##
## LEF for PtnCells ;
## created by Encounter v13.10-p003_1 on Wed Aug 21 15:55:13 2013
##

VERSION 5.6 ;

BUSBITCHARS "[]" ;
DIVIDERCHAR "/" ;

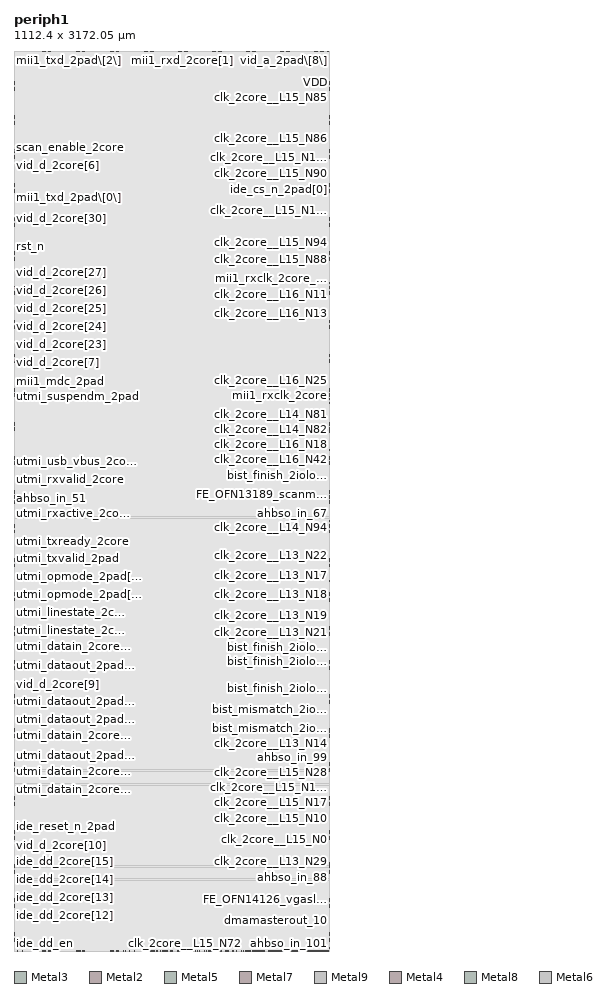
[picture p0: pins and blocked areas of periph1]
MACRO periph1
  CLASS BLOCK ;
  FOREIGN periph1 0 0 ;
  ORIGIN 0.0000 0.0000 ;
  SIZE 1112.4000 BY 3172.0500 ;
  SYMMETRY X Y R90 ;
  PIN n_28347
    DIRECTION OUTPUT ;
    USE SIGNAL ;
    PORT
      LAYER Metal3 ;
        RECT 1112.1100 1866.4300 1112.4000 1866.5000 ;
    END
  END n_28347
  PIN n_28315
    DIRECTION OUTPUT ;
    USE SIGNAL ;
    PORT
      LAYER Metal3 ;
        RECT 1112.1100 1633.8700 1112.4000 1633.9400 ;
    END
  END n_28315
  PIN n_28247
    DIRECTION OUTPUT ;
    USE SIGNAL ;
    PORT
      LAYER Metal3 ;
        RECT 1112.1100 1931.4100 1112.4000 1931.4800 ;
    END
  END n_28247
  PIN n_28215
    DIRECTION OUTPUT ;
    USE SIGNAL ;
    PORT
      LAYER Metal3 ;
        RECT 1112.1100 1936.3500 1112.4000 1936.4200 ;
    END
  END n_28215
  PIN n_27984
    DIRECTION OUTPUT ;
    USE SIGNAL ;
    PORT
      LAYER Metal2 ;
        RECT 1034.8650 0.0000 1034.9350 0.2900 ;
    END
  END n_27984
  PIN n_27896
    DIRECTION OUTPUT ;
    USE SIGNAL ;
    PORT
      LAYER Metal3 ;
        RECT 1112.1100 1681.9400 1112.4000 1682.0100 ;
    END
  END n_27896
  PIN n_27776
    DIRECTION OUTPUT ;
    USE SIGNAL ;
    PORT
      LAYER Metal5 ;
        RECT 1112.1100 1669.7800 1112.4000 1669.8500 ;
    END
  END n_27776
  PIN n_27342
    DIRECTION OUTPUT ;
    USE SIGNAL ;
    PORT
      LAYER Metal7 ;
        RECT 1112.1100 1657.7150 1112.4000 1657.7850 ;
    END
  END n_27342
  PIN n_27252
    DIRECTION OUTPUT ;
    USE SIGNAL ;
    PORT
      LAYER Metal3 ;
        RECT 1112.1100 1649.2600 1112.4000 1649.3300 ;
    END
  END n_27252
  PIN n_27085
    DIRECTION OUTPUT ;
    USE SIGNAL ;
    PORT
      LAYER Metal3 ;
        RECT 1112.1100 845.3700 1112.4000 845.4400 ;
    END
  END n_27085
  PIN n_26776
    DIRECTION OUTPUT ;
    USE SIGNAL ;
    PORT
      LAYER Metal3 ;
        RECT 1112.1100 1197.8200 1112.4000 1197.8900 ;
    END
  END n_26776
  PIN n_20111
    DIRECTION INPUT ;
    USE SIGNAL ;
    PORT
      LAYER Metal5 ;
        RECT 1112.1100 1.0100 1112.4000 1.0800 ;
    END
  END n_20111
  PIN mii2_mdio_en_n
    DIRECTION OUTPUT ;
    USE SIGNAL ;
    PORT
      LAYER Metal9 ;
        RECT 1112.1100 1817.7900 1112.4000 1817.8600 ;
    END
  END mii2_mdio_en_n
  PIN mii2_mdio_2pad
    DIRECTION OUTPUT ;
    USE SIGNAL ;
    PORT
      LAYER Metal9 ;
        RECT 1112.1100 1819.3100 1112.4000 1819.3800 ;
    END
  END mii2_mdio_2pad
  PIN mii2_mdc_2pad
    DIRECTION OUTPUT ;
    USE SIGNAL ;
    PORT
      LAYER Metal9 ;
        RECT 1112.1100 1805.2500 1112.4000 1805.3200 ;
    END
  END mii2_mdc_2pad
  PIN mii2_mdio_2core
    DIRECTION INPUT ;
    USE SIGNAL ;
    PORT
      LAYER Metal9 ;
        RECT 1112.1100 1822.7300 1112.4000 1822.8000 ;
    END
  END mii2_mdio_2core
  PIN mii2_rxerr_2core
    DIRECTION INPUT ;
    USE SIGNAL ;
    PORT
      LAYER Metal4 ;
        RECT 1106.6650 3171.7600 1106.7350 3172.0500 ;
    END
  END mii2_rxerr_2core
  PIN mii2_rxdv_2core
    DIRECTION INPUT ;
    USE SIGNAL ;
    PORT
      LAYER Metal3 ;
        RECT 1112.1100 2779.5700 1112.4000 2779.6400 ;
    END
  END mii2_rxdv_2core
  PIN mii2_rxclk_2core
    DIRECTION INPUT ;
    USE SIGNAL ;
    PORT
      LAYER Metal5 ;
        RECT 1112.1100 1593.2100 1112.4000 1593.2800 ;
    END
  END mii2_rxclk_2core
  PIN mii2_crs_2core
    DIRECTION INPUT ;
    USE SIGNAL ;
    PORT
      LAYER Metal9 ;
        RECT 1112.1100 1874.4100 1112.4000 1874.4800 ;
    END
  END mii2_crs_2core
  PIN mii2_col_2core
    DIRECTION INPUT ;
    USE SIGNAL ;
    PORT
      LAYER Metal9 ;
        RECT 1112.1100 1527.4700 1112.4000 1527.5400 ;
    END
  END mii2_col_2core
  PIN n_28314
    DIRECTION OUTPUT ;
    USE SIGNAL ;
    PORT
      LAYER Metal5 ;
        RECT 1112.1100 1634.0600 1112.4000 1634.1300 ;
    END
  END n_28314
  PIN n_28346
    DIRECTION OUTPUT ;
    USE SIGNAL ;
    PORT
      LAYER Metal5 ;
        RECT 1112.1100 1866.6200 1112.4000 1866.6900 ;
    END
  END n_28346
  PIN mii2_txclk_2core
    DIRECTION INPUT ;
    USE SIGNAL ;
    PORT
      LAYER Metal3 ;
        RECT 1112.1100 1444.2500 1112.4000 1444.3200 ;
    END
  END mii2_txclk_2core
  PIN mii1_mdio_en_n
    DIRECTION OUTPUT ;
    USE SIGNAL ;
    PORT
      LAYER Metal9 ;
        RECT 1112.1100 1786.2500 1112.4000 1786.3200 ;
    END
  END mii1_mdio_en_n
  PIN mii1_mdio_2pad
    DIRECTION OUTPUT ;
    USE SIGNAL ;
    PORT
      LAYER Metal9 ;
        RECT 1112.1100 1772.9500 1112.4000 1773.0200 ;
    END
  END mii1_mdio_2pad
  PIN mii1_mdc_2pad
    DIRECTION OUTPUT ;
    USE SIGNAL ;
    PORT
      LAYER Metal9 ;
        RECT 0.0000 2036.2900 0.2900 2036.3600 ;
    END
  END mii1_mdc_2pad
  PIN mii1_mdio_2core
    DIRECTION INPUT ;
    USE SIGNAL ;
    PORT
      LAYER Metal9 ;
        RECT 1112.1100 1791.9500 1112.4000 1792.0200 ;
    END
  END mii1_mdio_2core
  PIN mii1_rxerr_2core
    DIRECTION INPUT ;
    USE SIGNAL ;
    PORT
      LAYER Metal8 ;
        RECT 977.6650 3171.7600 977.7350 3172.0500 ;
    END
  END mii1_rxerr_2core
  PIN mii1_rxdv_2core
    DIRECTION INPUT ;
    USE SIGNAL ;
    PORT
      LAYER Metal8 ;
        RECT 900.8650 3171.7600 900.9350 3172.0500 ;
    END
  END mii1_rxdv_2core
  PIN mii1_rxclk_2core
    DIRECTION INPUT ;
    USE SIGNAL ;
    PORT
      LAYER Metal3 ;
        RECT 1112.1100 1956.6800 1112.4000 1956.7500 ;
    END
  END mii1_rxclk_2core
  PIN mii1_crs_2core
    DIRECTION INPUT ;
    USE SIGNAL ;
    PORT
      LAYER Metal9 ;
        RECT 1112.1100 1846.2900 1112.4000 1846.3600 ;
    END
  END mii1_crs_2core
  PIN mii1_col_2core
    DIRECTION INPUT ;
    USE SIGNAL ;
    PORT
      LAYER Metal2 ;
        RECT 363.0650 3171.7600 363.1350 3172.0500 ;
    END
  END mii1_col_2core
  PIN n_28214
    DIRECTION OUTPUT ;
    USE SIGNAL ;
    PORT
      LAYER Metal5 ;
        RECT 1112.1100 1936.3500 1112.4000 1936.4200 ;
    END
  END n_28214
  PIN n_28246
    DIRECTION OUTPUT ;
    USE SIGNAL ;
    PORT
      LAYER Metal5 ;
        RECT 1112.1100 1931.6000 1112.4000 1931.6700 ;
    END
  END n_28246
  PIN mii1_txclk_2core
    DIRECTION INPUT ;
    USE SIGNAL ;
    PORT
      LAYER Metal3 ;
        RECT 1112.1100 1553.1200 1112.4000 1553.1900 ;
    END
  END mii1_txclk_2core
  PIN dma_irq
    DIRECTION OUTPUT ;
    USE SIGNAL ;
    PORT
      LAYER Metal3 ;
        RECT 1112.1100 561.1300 1112.4000 561.2000 ;
    END
  END dma_irq
  PIN pio_2pad_1
    DIRECTION INPUT ;
    USE SIGNAL ;
    PORT
      LAYER Metal4 ;
        RECT 1056.8650 0.0000 1056.9350 0.2900 ;
    END
  END pio_2pad_1
  PIN dmaslavein_0
    DIRECTION INPUT ;
    USE SIGNAL ;
    PORT
      LAYER Metal2 ;
        RECT 990.4650 0.0000 990.5350 0.2900 ;
    END
  END dmaslavein_0
  PIN dmaslavein_1
    DIRECTION INPUT ;
    USE SIGNAL ;
    PORT
      LAYER Metal2 ;
        RECT 975.0650 0.0000 975.1350 0.2900 ;
    END
  END dmaslavein_1
  PIN dmaslavein_2
    DIRECTION INPUT ;
    USE SIGNAL ;
    PORT
      LAYER Metal4 ;
        RECT 975.4650 0.0000 975.5350 0.2900 ;
    END
  END dmaslavein_2
  PIN dmaslavein_3
    DIRECTION INPUT ;
    USE SIGNAL ;
    PORT
      LAYER Metal6 ;
        RECT 975.2650 0.0000 975.3350 0.2900 ;
    END
  END dmaslavein_3
  PIN dmaslavein_4
    DIRECTION INPUT ;
    USE SIGNAL ;
    PORT
      LAYER Metal2 ;
        RECT 972.2650 0.0000 972.3350 0.2900 ;
    END
  END dmaslavein_4
  PIN dmaslavein_5
    DIRECTION INPUT ;
    USE SIGNAL ;
    PORT
      LAYER Metal4 ;
        RECT 972.4650 0.0000 972.5350 0.2900 ;
    END
  END dmaslavein_5
  PIN dmaslavein_6
    DIRECTION INPUT ;
    USE SIGNAL ;
    PORT
      LAYER Metal2 ;
        RECT 982.8650 0.0000 982.9350 0.2900 ;
    END
  END dmaslavein_6
  PIN dmaslavein_7
    DIRECTION INPUT ;
    USE SIGNAL ;
    PORT
      LAYER Metal2 ;
        RECT 978.8650 0.0000 978.9350 0.2900 ;
    END
  END dmaslavein_7
  PIN dmaslavein_8
    DIRECTION INPUT ;
    USE SIGNAL ;
    PORT
      LAYER Metal3 ;
        RECT 1112.1100 335.4100 1112.4000 335.4800 ;
    END
  END dmaslavein_8
  PIN dmaslavein_9
    DIRECTION INPUT ;
    USE SIGNAL ;
    PORT
      LAYER Metal2 ;
        RECT 977.4650 0.0000 977.5350 0.2900 ;
    END
  END dmaslavein_9
  PIN dmaslavein_10
    DIRECTION INPUT ;
    USE SIGNAL ;
    PORT
      LAYER Metal3 ;
        RECT 1112.1100 329.3300 1112.4000 329.4000 ;
    END
  END dmaslavein_10
  PIN dmaslavein_11
    DIRECTION INPUT ;
    USE SIGNAL ;
    PORT
      LAYER Metal2 ;
        RECT 975.6650 0.0000 975.7350 0.2900 ;
    END
  END dmaslavein_11
  PIN dmaslavein_12
    DIRECTION INPUT ;
    USE SIGNAL ;
    PORT
      LAYER Metal4 ;
        RECT 973.4650 0.0000 973.5350 0.2900 ;
    END
  END dmaslavein_12
  PIN dmaslavein_13
    DIRECTION INPUT ;
    USE SIGNAL ;
    PORT
      LAYER Metal3 ;
        RECT 1112.1100 316.4100 1112.4000 316.4800 ;
    END
  END dmaslavein_13
  PIN dmaslavein_14
    DIRECTION INPUT ;
    USE SIGNAL ;
    PORT
      LAYER Metal2 ;
        RECT 976.6650 0.0000 976.7350 0.2900 ;
    END
  END dmaslavein_14
  PIN dmaslavein_15
    DIRECTION INPUT ;
    USE SIGNAL ;
    PORT
      LAYER Metal4 ;
        RECT 977.8650 0.0000 977.9350 0.2900 ;
    END
  END dmaslavein_15
  PIN dmaslavein_16
    DIRECTION INPUT ;
    USE SIGNAL ;
    PORT
      LAYER Metal2 ;
        RECT 985.8650 0.0000 985.9350 0.2900 ;
    END
  END dmaslavein_16
  PIN dmaslavein_17
    DIRECTION INPUT ;
    USE SIGNAL ;
    PORT
      LAYER Metal2 ;
        RECT 987.8650 0.0000 987.9350 0.2900 ;
    END
  END dmaslavein_17
  PIN dmaslavein_18
    DIRECTION INPUT ;
    USE SIGNAL ;
    PORT
      LAYER Metal2 ;
        RECT 988.8650 0.0000 988.9350 0.2900 ;
    END
  END dmaslavein_18
  PIN dmaslavein_19
    DIRECTION INPUT ;
    USE SIGNAL ;
    PORT
      LAYER Metal2 ;
        RECT 987.4650 0.0000 987.5350 0.2900 ;
    END
  END dmaslavein_19
  PIN dmaslavein_20
    DIRECTION INPUT ;
    USE SIGNAL ;
    PORT
      LAYER Metal2 ;
        RECT 988.4650 0.0000 988.5350 0.2900 ;
    END
  END dmaslavein_20
  PIN dmaslavein_21
    DIRECTION INPUT ;
    USE SIGNAL ;
    PORT
      LAYER Metal2 ;
        RECT 991.8650 0.0000 991.9350 0.2900 ;
    END
  END dmaslavein_21
  PIN dmaslavein_22
    DIRECTION INPUT ;
    USE SIGNAL ;
    PORT
      LAYER Metal2 ;
        RECT 991.4650 0.0000 991.5350 0.2900 ;
    END
  END dmaslavein_22
  PIN dmaslavein_23
    DIRECTION INPUT ;
    USE SIGNAL ;
    PORT
      LAYER Metal4 ;
        RECT 990.6650 0.0000 990.7350 0.2900 ;
    END
  END dmaslavein_23
  PIN dmaslavein_24
    DIRECTION INPUT ;
    USE SIGNAL ;
    PORT
      LAYER Metal4 ;
        RECT 986.0650 0.0000 986.1350 0.2900 ;
    END
  END dmaslavein_24
  PIN dmaslavein_25
    DIRECTION INPUT ;
    USE SIGNAL ;
    PORT
      LAYER Metal2 ;
        RECT 980.2650 0.0000 980.3350 0.2900 ;
    END
  END dmaslavein_25
  PIN dmaslavein_26
    DIRECTION INPUT ;
    USE SIGNAL ;
    PORT
      LAYER Metal2 ;
        RECT 983.2650 0.0000 983.3350 0.2900 ;
    END
  END dmaslavein_26
  PIN dmaslavein_27
    DIRECTION INPUT ;
    USE SIGNAL ;
    PORT
      LAYER Metal3 ;
        RECT 1112.1100 268.5300 1112.4000 268.6000 ;
    END
  END dmaslavein_27
  PIN dmaslavein_28
    DIRECTION INPUT ;
    USE SIGNAL ;
    PORT
      LAYER Metal2 ;
        RECT 981.6650 0.0000 981.7350 0.2900 ;
    END
  END dmaslavein_28
  PIN dmaslavein_29
    DIRECTION INPUT ;
    USE SIGNAL ;
    PORT
      LAYER Metal4 ;
        RECT 987.6650 0.0000 987.7350 0.2900 ;
    END
  END dmaslavein_29
  PIN dmaslavein_30
    DIRECTION INPUT ;
    USE SIGNAL ;
    PORT
      LAYER Metal4 ;
        RECT 986.6650 0.0000 986.7350 0.2900 ;
    END
  END dmaslavein_30
  PIN dmaslavein_31
    DIRECTION INPUT ;
    USE SIGNAL ;
    PORT
      LAYER Metal2 ;
        RECT 984.8650 0.0000 984.9350 0.2900 ;
    END
  END dmaslavein_31
  PIN dmaslavein_32
    DIRECTION INPUT ;
    USE SIGNAL ;
    PORT
      LAYER Metal2 ;
        RECT 1101.8650 0.0000 1101.9350 0.2900 ;
    END
  END dmaslavein_32
  PIN dmaslavein_33
    DIRECTION INPUT ;
    USE SIGNAL ;
    PORT
      LAYER Metal3 ;
        RECT 1112.1100 10.5100 1112.4000 10.5800 ;
    END
  END dmaslavein_33
  PIN dmaslavein_34
    DIRECTION INPUT ;
    USE SIGNAL ;
    PORT
      LAYER Metal3 ;
        RECT 1112.1100 225.9700 1112.4000 226.0400 ;
    END
  END dmaslavein_34
  PIN dmaslavein_35
    DIRECTION INPUT ;
    USE SIGNAL ;
    PORT
      LAYER Metal2 ;
        RECT 1077.8650 0.0000 1077.9350 0.2900 ;
    END
  END dmaslavein_35
  PIN dmaslavein_36
    DIRECTION INPUT ;
    USE SIGNAL ;
    PORT
      LAYER Metal2 ;
        RECT 1078.4650 0.0000 1078.5350 0.2900 ;
    END
  END dmaslavein_36
  PIN dmaslavein_37
    DIRECTION INPUT ;
    USE SIGNAL ;
    PORT
      LAYER Metal2 ;
        RECT 1095.4650 0.0000 1095.5350 0.2900 ;
    END
  END dmaslavein_37
  PIN dmaslavein_38
    DIRECTION INPUT ;
    USE SIGNAL ;
    PORT
      LAYER Metal2 ;
        RECT 1095.0650 0.0000 1095.1350 0.2900 ;
    END
  END dmaslavein_38
  PIN dmaslavein_39
    DIRECTION INPUT ;
    USE SIGNAL ;
    PORT
      LAYER Metal2 ;
        RECT 1096.0650 0.0000 1096.1350 0.2900 ;
    END
  END dmaslavein_39
  PIN dmaslavein_40
    DIRECTION INPUT ;
    USE SIGNAL ;
    PORT
      LAYER Metal2 ;
        RECT 1089.0650 0.0000 1089.1350 0.2900 ;
    END
  END dmaslavein_40
  PIN dmaslavein_41
    DIRECTION INPUT ;
    USE SIGNAL ;
    PORT
      LAYER Metal4 ;
        RECT 1089.0650 0.0000 1089.1350 0.2900 ;
    END
  END dmaslavein_41
  PIN dmaslavein_42
    DIRECTION INPUT ;
    USE SIGNAL ;
    PORT
      LAYER Metal2 ;
        RECT 1090.2650 0.0000 1090.3350 0.2900 ;
    END
  END dmaslavein_42
  PIN dmaslavein_43
    DIRECTION INPUT ;
    USE SIGNAL ;
    PORT
      LAYER Metal6 ;
        RECT 1098.8650 0.0000 1098.9350 0.2900 ;
    END
  END dmaslavein_43
  PIN dmaslavein_44
    DIRECTION INPUT ;
    USE SIGNAL ;
    PORT
      LAYER Metal3 ;
        RECT 1112.1100 7.2800 1112.4000 7.3500 ;
    END
  END dmaslavein_44
  PIN dmaslavein_45
    DIRECTION INPUT ;
    USE SIGNAL ;
    PORT
      LAYER Metal5 ;
        RECT 1112.1100 7.0900 1112.4000 7.1600 ;
    END
  END dmaslavein_45
  PIN dmaslavein_46
    DIRECTION INPUT ;
    USE SIGNAL ;
    PORT
      LAYER Metal5 ;
        RECT 1112.1100 7.8500 1112.4000 7.9200 ;
    END
  END dmaslavein_46
  PIN dmaslavein_47
    DIRECTION INPUT ;
    USE SIGNAL ;
    PORT
      LAYER Metal2 ;
        RECT 1106.8650 0.0000 1106.9350 0.2900 ;
    END
  END dmaslavein_47
  PIN dmaslavein_48
    DIRECTION INPUT ;
    USE SIGNAL ;
    PORT
      LAYER Metal3 ;
        RECT 1112.1100 9.7500 1112.4000 9.8200 ;
    END
  END dmaslavein_48
  PIN dmaslavein_49
    DIRECTION INPUT ;
    USE SIGNAL ;
    PORT
      LAYER Metal4 ;
        RECT 1102.0650 0.0000 1102.1350 0.2900 ;
    END
  END dmaslavein_49
  PIN dmaslavein_50
    DIRECTION INPUT ;
    USE SIGNAL ;
    PORT
      LAYER Metal5 ;
        RECT 1112.1100 9.3700 1112.4000 9.4400 ;
    END
  END dmaslavein_50
  PIN dmaslavein_51
    DIRECTION INPUT ;
    USE SIGNAL ;
    PORT
      LAYER Metal4 ;
        RECT 1102.6650 0.0000 1102.7350 0.2900 ;
    END
  END dmaslavein_51
  PIN dmaslavein_52
    DIRECTION INPUT ;
    USE SIGNAL ;
    PORT
      LAYER Metal4 ;
        RECT 1106.6650 0.0000 1106.7350 0.2900 ;
    END
  END dmaslavein_52
  PIN dmaslavein_53
    DIRECTION INPUT ;
    USE SIGNAL ;
    PORT
      LAYER Metal2 ;
        RECT 1106.4650 0.0000 1106.5350 0.2900 ;
    END
  END dmaslavein_53
  PIN dmaslavein_54
    DIRECTION INPUT ;
    USE SIGNAL ;
    PORT
      LAYER Metal2 ;
        RECT 1105.4650 0.0000 1105.5350 0.2900 ;
    END
  END dmaslavein_54
  PIN dmaslavein_55
    DIRECTION INPUT ;
    USE SIGNAL ;
    PORT
      LAYER Metal3 ;
        RECT 1112.1100 8.9900 1112.4000 9.0600 ;
    END
  END dmaslavein_55
  PIN dmaslavein_56
    DIRECTION INPUT ;
    USE SIGNAL ;
    PORT
      LAYER Metal4 ;
        RECT 1106.2650 0.0000 1106.3350 0.2900 ;
    END
  END dmaslavein_56
  PIN dmaslavein_57
    DIRECTION INPUT ;
    USE SIGNAL ;
    PORT
      LAYER Metal6 ;
        RECT 1106.8650 0.0000 1106.9350 0.2900 ;
    END
  END dmaslavein_57
  PIN dmaslavein_58
    DIRECTION INPUT ;
    USE SIGNAL ;
    PORT
      LAYER Metal3 ;
        RECT 1112.1100 10.8900 1112.4000 10.9600 ;
    END
  END dmaslavein_58
  PIN dmaslavein_59
    DIRECTION INPUT ;
    USE SIGNAL ;
    PORT
      LAYER Metal4 ;
        RECT 1105.2650 0.0000 1105.3350 0.2900 ;
    END
  END dmaslavein_59
  PIN dmaslavein_60
    DIRECTION INPUT ;
    USE SIGNAL ;
    PORT
      LAYER Metal8 ;
        RECT 1103.6650 0.0000 1103.7350 0.2900 ;
    END
  END dmaslavein_60
  PIN dmaslavein_61
    DIRECTION INPUT ;
    USE SIGNAL ;
    PORT
      LAYER Metal3 ;
        RECT 1112.1100 8.2300 1112.4000 8.3000 ;
    END
  END dmaslavein_61
  PIN dmaslavein_62
    DIRECTION INPUT ;
    USE SIGNAL ;
    PORT
      LAYER Metal5 ;
        RECT 1112.1100 7.4700 1112.4000 7.5400 ;
    END
  END dmaslavein_62
  PIN dmaslavein_63
    DIRECTION INPUT ;
    USE SIGNAL ;
    PORT
      LAYER Metal6 ;
        RECT 1102.8650 0.0000 1102.9350 0.2900 ;
    END
  END dmaslavein_63
  PIN dmaslavein_73
    DIRECTION INPUT ;
    USE SIGNAL ;
    PORT
      LAYER Metal3 ;
        RECT 1112.1100 232.0500 1112.4000 232.1200 ;
    END
  END dmaslavein_73
  PIN dmaslavein_74
    DIRECTION INPUT ;
    USE SIGNAL ;
    PORT
      LAYER Metal2 ;
        RECT 1091.4650 0.0000 1091.5350 0.2900 ;
    END
  END dmaslavein_74
  PIN dmaslavein_75
    DIRECTION INPUT ;
    USE SIGNAL ;
    PORT
      LAYER Metal2 ;
        RECT 1083.4650 0.0000 1083.5350 0.2900 ;
    END
  END dmaslavein_75
  PIN dmaslavein_76
    DIRECTION INPUT ;
    USE SIGNAL ;
    PORT
      LAYER Metal3 ;
        RECT 1112.1100 229.3900 1112.4000 229.4600 ;
    END
  END dmaslavein_76
  PIN dmaslavein_77
    DIRECTION INPUT ;
    USE SIGNAL ;
    PORT
      LAYER Metal2 ;
        RECT 1090.8650 0.0000 1090.9350 0.2900 ;
    END
  END dmaslavein_77
  PIN dmaslavein_78
    DIRECTION INPUT ;
    USE SIGNAL ;
    PORT
      LAYER Metal4 ;
        RECT 1091.6650 0.0000 1091.7350 0.2900 ;
    END
  END dmaslavein_78
  PIN dmaslavein_80
    DIRECTION INPUT ;
    USE SIGNAL ;
    PORT
      LAYER Metal2 ;
        RECT 1081.6650 0.0000 1081.7350 0.2900 ;
    END
  END dmaslavein_80
  PIN dmaslavein_81
    DIRECTION INPUT ;
    USE SIGNAL ;
    PORT
      LAYER Metal2 ;
        RECT 1071.8650 0.0000 1071.9350 0.2900 ;
    END
  END dmaslavein_81
  PIN dmaslavein_82
    DIRECTION INPUT ;
    USE SIGNAL ;
    PORT
      LAYER Metal6 ;
        RECT 1091.4650 0.0000 1091.5350 0.2900 ;
    END
  END dmaslavein_82
  PIN dmaslavein_83
    DIRECTION INPUT ;
    USE SIGNAL ;
    PORT
      LAYER Metal3 ;
        RECT 1112.1100 244.5900 1112.4000 244.6600 ;
    END
  END dmaslavein_83
  PIN dmamasterout_0
    DIRECTION OUTPUT ;
    USE SIGNAL ;
    PORT
      LAYER Metal6 ;
        RECT 1091.8650 0.0000 1091.9350 0.2900 ;
    END
  END dmamasterout_0
  PIN dmamasterout_1
    DIRECTION OUTPUT ;
    USE SIGNAL ;
    PORT
      LAYER Metal4 ;
        RECT 1099.0650 0.0000 1099.1350 0.2900 ;
    END
  END dmamasterout_1
  PIN dmamasterout_2
    DIRECTION OUTPUT ;
    USE SIGNAL ;
    PORT
      LAYER Metal8 ;
        RECT 1098.2650 0.0000 1098.3350 0.2900 ;
    END
  END dmamasterout_2
  PIN dmamasterout_3
    DIRECTION OUTPUT ;
    USE SIGNAL ;
    PORT
      LAYER Metal6 ;
        RECT 1101.6650 0.0000 1101.7350 0.2900 ;
    END
  END dmamasterout_3
  PIN dmamasterout_4
    DIRECTION OUTPUT ;
    USE SIGNAL ;
    PORT
      LAYER Metal6 ;
        RECT 1095.0650 0.0000 1095.1350 0.2900 ;
    END
  END dmamasterout_4
  PIN dmamasterout_5
    DIRECTION OUTPUT ;
    USE SIGNAL ;
    PORT
      LAYER Metal8 ;
        RECT 1101.6650 0.0000 1101.7350 0.2900 ;
    END
  END dmamasterout_5
  PIN dmamasterout_6
    DIRECTION OUTPUT ;
    USE SIGNAL ;
    PORT
      LAYER Metal2 ;
        RECT 1096.8650 0.0000 1096.9350 0.2900 ;
    END
  END dmamasterout_6
  PIN dmamasterout_7
    DIRECTION OUTPUT ;
    USE SIGNAL ;
    PORT
      LAYER Metal8 ;
        RECT 1101.2650 0.0000 1101.3350 0.2900 ;
    END
  END dmamasterout_7
  PIN dmamasterout_8
    DIRECTION OUTPUT ;
    USE SIGNAL ;
    PORT
      LAYER Metal4 ;
        RECT 1095.4650 0.0000 1095.5350 0.2900 ;
    END
  END dmamasterout_8
  PIN dmamasterout_9
    DIRECTION OUTPUT ;
    USE SIGNAL ;
    PORT
      LAYER Metal8 ;
        RECT 1100.8650 0.0000 1100.9350 0.2900 ;
    END
  END dmamasterout_9
  PIN dmamasterout_10
    DIRECTION OUTPUT ;
    USE SIGNAL ;
    PORT
      LAYER Metal3 ;
        RECT 1112.1100 135.1500 1112.4000 135.2200 ;
    END
  END dmamasterout_10
  PIN dmamasterout_11
    DIRECTION OUTPUT ;
    USE SIGNAL ;
    PORT
      LAYER Metal2 ;
        RECT 1099.8650 0.0000 1099.9350 0.2900 ;
    END
  END dmamasterout_11
  PIN dmamasterout_12
    DIRECTION OUTPUT ;
    USE SIGNAL ;
    PORT
      LAYER Metal6 ;
        RECT 1100.6650 0.0000 1100.7350 0.2900 ;
    END
  END dmamasterout_12
  PIN dmamasterout_13
    DIRECTION OUTPUT ;
    USE SIGNAL ;
    PORT
      LAYER Metal8 ;
        RECT 1100.4650 0.0000 1100.5350 0.2900 ;
    END
  END dmamasterout_13
  PIN dmamasterout_14
    DIRECTION OUTPUT ;
    USE SIGNAL ;
    PORT
      LAYER Metal4 ;
        RECT 1096.6650 0.0000 1096.7350 0.2900 ;
    END
  END dmamasterout_14
  PIN dmamasterout_15
    DIRECTION OUTPUT ;
    USE SIGNAL ;
    PORT
      LAYER Metal6 ;
        RECT 1100.2650 0.0000 1100.3350 0.2900 ;
    END
  END dmamasterout_15
  PIN dmamasterout_16
    DIRECTION OUTPUT ;
    USE SIGNAL ;
    PORT
      LAYER Metal8 ;
        RECT 1100.0650 0.0000 1100.1350 0.2900 ;
    END
  END dmamasterout_16
  PIN dmamasterout_17
    DIRECTION OUTPUT ;
    USE SIGNAL ;
    PORT
      LAYER Metal6 ;
        RECT 1099.8650 0.0000 1099.9350 0.2900 ;
    END
  END dmamasterout_17
  PIN dmamasterout_18
    DIRECTION OUTPUT ;
    USE SIGNAL ;
    PORT
      LAYER Metal2 ;
        RECT 1094.0650 0.0000 1094.1350 0.2900 ;
    END
  END dmamasterout_18
  PIN dmamasterout_19
    DIRECTION OUTPUT ;
    USE SIGNAL ;
    PORT
      LAYER Metal4 ;
        RECT 1096.2650 0.0000 1096.3350 0.2900 ;
    END
  END dmamasterout_19
  PIN dmamasterout_20
    DIRECTION OUTPUT ;
    USE SIGNAL ;
    PORT
      LAYER Metal8 ;
        RECT 1099.6650 0.0000 1099.7350 0.2900 ;
    END
  END dmamasterout_20
  PIN dmamasterout_21
    DIRECTION OUTPUT ;
    USE SIGNAL ;
    PORT
      LAYER Metal6 ;
        RECT 1099.4650 0.0000 1099.5350 0.2900 ;
    END
  END dmamasterout_21
  PIN dmamasterout_22
    DIRECTION OUTPUT ;
    USE SIGNAL ;
    PORT
      LAYER Metal4 ;
        RECT 1090.4650 0.0000 1090.5350 0.2900 ;
    END
  END dmamasterout_22
  PIN dmamasterout_23
    DIRECTION OUTPUT ;
    USE SIGNAL ;
    PORT
      LAYER Metal8 ;
        RECT 1099.2650 0.0000 1099.3350 0.2900 ;
    END
  END dmamasterout_23
  PIN dmamasterout_24
    DIRECTION OUTPUT ;
    USE SIGNAL ;
    PORT
      LAYER Metal4 ;
        RECT 1097.0650 0.0000 1097.1350 0.2900 ;
    END
  END dmamasterout_24
  PIN dmamasterout_25
    DIRECTION OUTPUT ;
    USE SIGNAL ;
    PORT
      LAYER Metal3 ;
        RECT 1112.1100 137.0500 1112.4000 137.1200 ;
    END
  END dmamasterout_25
  PIN dmamasterout_26
    DIRECTION OUTPUT ;
    USE SIGNAL ;
    PORT
      LAYER Metal6 ;
        RECT 1108.4650 0.0000 1108.5350 0.2900 ;
    END
  END dmamasterout_26
  PIN dmamasterout_27
    DIRECTION OUTPUT ;
    USE SIGNAL ;
    PORT
      LAYER Metal6 ;
        RECT 1097.8650 0.0000 1097.9350 0.2900 ;
    END
  END dmamasterout_27
  PIN dmamasterout_28
    DIRECTION OUTPUT ;
    USE SIGNAL ;
    PORT
      LAYER Metal3 ;
        RECT 1112.1100 131.7300 1112.4000 131.8000 ;
    END
  END dmamasterout_28
  PIN dmamasterout_29
    DIRECTION OUTPUT ;
    USE SIGNAL ;
    PORT
      LAYER Metal8 ;
        RECT 1108.4650 0.0000 1108.5350 0.2900 ;
    END
  END dmamasterout_29
  PIN dmamasterout_30
    DIRECTION OUTPUT ;
    USE SIGNAL ;
    PORT
      LAYER Metal3 ;
        RECT 1112.1100 130.2100 1112.4000 130.2800 ;
    END
  END dmamasterout_30
  PIN dmamasterout_31
    DIRECTION OUTPUT ;
    USE SIGNAL ;
    PORT
      LAYER Metal8 ;
        RECT 1097.8650 0.0000 1097.9350 0.2900 ;
    END
  END dmamasterout_31
  PIN dmamasterout_32
    DIRECTION OUTPUT ;
    USE SIGNAL ;
    PORT
      LAYER Metal4 ;
        RECT 1094.2650 0.0000 1094.3350 0.2900 ;
    END
  END dmamasterout_32
  PIN dmamasterout_33
    DIRECTION OUTPUT ;
    USE SIGNAL ;
    PORT
      LAYER Metal4 ;
        RECT 1097.4650 0.0000 1097.5350 0.2900 ;
    END
  END dmamasterout_33
  PIN dmamasterout_34
    DIRECTION OUTPUT ;
    USE SIGNAL ;
    PORT
      LAYER Metal6 ;
        RECT 1097.4650 0.0000 1097.5350 0.2900 ;
    END
  END dmamasterout_34
  PIN dmamasterout_35
    DIRECTION OUTPUT ;
    USE SIGNAL ;
    PORT
      LAYER Metal6 ;
        RECT 1094.4650 0.0000 1094.5350 0.2900 ;
    END
  END dmamasterout_35
  PIN dmamasterout_36
    DIRECTION OUTPUT ;
    USE SIGNAL ;
    PORT
      LAYER Metal8 ;
        RECT 1097.2650 0.0000 1097.3350 0.2900 ;
    END
  END dmamasterout_36
  PIN dmamasterout_37
    DIRECTION OUTPUT ;
    USE SIGNAL ;
    PORT
      LAYER Metal6 ;
        RECT 1096.0650 0.0000 1096.1350 0.2900 ;
    END
  END dmamasterout_37
  PIN dmamasterout_38
    DIRECTION OUTPUT ;
    USE SIGNAL ;
    PORT
      LAYER Metal4 ;
        RECT 1092.8650 0.0000 1092.9350 0.2900 ;
    END
  END dmamasterout_38
  PIN dmamasterout_39
    DIRECTION OUTPUT ;
    USE SIGNAL ;
    PORT
      LAYER Metal2 ;
        RECT 1108.6650 0.0000 1108.7350 0.2900 ;
    END
  END dmamasterout_39
  PIN dmamasterout_40
    DIRECTION OUTPUT ;
    USE SIGNAL ;
    PORT
      LAYER Metal6 ;
        RECT 1097.0650 0.0000 1097.1350 0.2900 ;
    END
  END dmamasterout_40
  PIN dmamasterout_41
    DIRECTION OUTPUT ;
    USE SIGNAL ;
    PORT
      LAYER Metal8 ;
        RECT 1094.8650 0.0000 1094.9350 0.2900 ;
    END
  END dmamasterout_41
  PIN dmamasterout_42
    DIRECTION OUTPUT ;
    USE SIGNAL ;
    PORT
      LAYER Metal8 ;
        RECT 1094.4650 0.0000 1094.5350 0.2900 ;
    END
  END dmamasterout_42
  PIN dmamasterout_43
    DIRECTION OUTPUT ;
    USE SIGNAL ;
    PORT
      LAYER Metal4 ;
        RECT 1093.6650 0.0000 1093.7350 0.2900 ;
    END
  END dmamasterout_43
  PIN dmamasterout_44
    DIRECTION OUTPUT ;
    USE SIGNAL ;
    PORT
      LAYER Metal4 ;
        RECT 1108.6650 0.0000 1108.7350 0.2900 ;
    END
  END dmamasterout_44
  PIN dmamasterout_45
    DIRECTION OUTPUT ;
    USE SIGNAL ;
    PORT
      LAYER Metal3 ;
        RECT 1112.1100 142.3700 1112.4000 142.4400 ;
    END
  END dmamasterout_45
  PIN dmamasterout_46
    DIRECTION OUTPUT ;
    USE SIGNAL ;
    PORT
      LAYER Metal3 ;
        RECT 1112.1100 141.9900 1112.4000 142.0600 ;
    END
  END dmamasterout_46
  PIN dmamasterout_47
    DIRECTION OUTPUT ;
    USE SIGNAL ;
    PORT
      LAYER Metal3 ;
        RECT 1112.1100 140.4700 1112.4000 140.5400 ;
    END
  END dmamasterout_47
  PIN dmamasterout_48
    DIRECTION OUTPUT ;
    USE SIGNAL ;
    PORT
      LAYER Metal6 ;
        RECT 1093.8650 0.0000 1093.9350 0.2900 ;
    END
  END dmamasterout_48
  PIN dmamasterout_49
    DIRECTION OUTPUT ;
    USE SIGNAL ;
    PORT
      LAYER Metal8 ;
        RECT 1096.8650 0.0000 1096.9350 0.2900 ;
    END
  END dmamasterout_49
  PIN dmamasterout_50
    DIRECTION OUTPUT ;
    USE SIGNAL ;
    PORT
      LAYER Metal3 ;
        RECT 1112.1100 147.3100 1112.4000 147.3800 ;
    END
  END dmamasterout_50
  PIN dmamasterout_51
    DIRECTION OUTPUT ;
    USE SIGNAL ;
    PORT
      LAYER Metal8 ;
        RECT 1095.4650 0.0000 1095.5350 0.2900 ;
    END
  END dmamasterout_51
  PIN dmamasterout_52
    DIRECTION OUTPUT ;
    USE SIGNAL ;
    PORT
      LAYER Metal6 ;
        RECT 1096.6650 0.0000 1096.7350 0.2900 ;
    END
  END dmamasterout_52
  PIN dmamasterout_53
    DIRECTION OUTPUT ;
    USE SIGNAL ;
    PORT
      LAYER Metal8 ;
        RECT 1096.4650 0.0000 1096.5350 0.2900 ;
    END
  END dmamasterout_53
  PIN dmamasterout_54
    DIRECTION OUTPUT ;
    USE SIGNAL ;
    PORT
      LAYER Metal8 ;
        RECT 1094.0650 0.0000 1094.1350 0.2900 ;
    END
  END dmamasterout_54
  PIN dmamasterout_55
    DIRECTION OUTPUT ;
    USE SIGNAL ;
    PORT
      LAYER Metal6 ;
        RECT 1108.8650 0.0000 1108.9350 0.2900 ;
    END
  END dmamasterout_55
  PIN dmamasterout_56
    DIRECTION OUTPUT ;
    USE SIGNAL ;
    PORT
      LAYER Metal3 ;
        RECT 1112.1100 149.2100 1112.4000 149.2800 ;
    END
  END dmamasterout_56
  PIN dmamasterout_57
    DIRECTION OUTPUT ;
    USE SIGNAL ;
    PORT
      LAYER Metal8 ;
        RECT 1093.6650 0.0000 1093.7350 0.2900 ;
    END
  END dmamasterout_57
  PIN dmamasterout_58
    DIRECTION OUTPUT ;
    USE SIGNAL ;
    PORT
      LAYER Metal6 ;
        RECT 1093.4650 0.0000 1093.5350 0.2900 ;
    END
  END dmamasterout_58
  PIN dmamasterout_59
    DIRECTION OUTPUT ;
    USE SIGNAL ;
    PORT
      LAYER Metal8 ;
        RECT 1108.8650 0.0000 1108.9350 0.2900 ;
    END
  END dmamasterout_59
  PIN dmamasterout_60
    DIRECTION OUTPUT ;
    USE SIGNAL ;
    PORT
      LAYER Metal4 ;
        RECT 1093.2650 0.0000 1093.3350 0.2900 ;
    END
  END dmamasterout_60
  PIN dmamasterout_61
    DIRECTION OUTPUT ;
    USE SIGNAL ;
    PORT
      LAYER Metal8 ;
        RECT 1093.2650 0.0000 1093.3350 0.2900 ;
    END
  END dmamasterout_61
  PIN dmamasterout_62
    DIRECTION OUTPUT ;
    USE SIGNAL ;
    PORT
      LAYER Metal3 ;
        RECT 1112.1100 148.8300 1112.4000 148.9000 ;
    END
  END dmamasterout_62
  PIN dmamasterout_63
    DIRECTION OUTPUT ;
    USE SIGNAL ;
    PORT
      LAYER Metal8 ;
        RECT 1091.8650 0.0000 1091.9350 0.2900 ;
    END
  END dmamasterout_63
  PIN dmamasterout_64
    DIRECTION OUTPUT ;
    USE SIGNAL ;
    PORT
      LAYER Metal3 ;
        RECT 1112.1100 224.0700 1112.4000 224.1400 ;
    END
  END dmamasterout_64
  PIN dmamasterout_65
    DIRECTION OUTPUT ;
    USE SIGNAL ;
    PORT
      LAYER Metal3 ;
        RECT 1112.1100 222.9300 1112.4000 223.0000 ;
    END
  END dmamasterout_65
  PIN dmamasterout_66
    DIRECTION OUTPUT ;
    USE SIGNAL ;
    PORT
      LAYER Metal3 ;
        RECT 1112.1100 143.8900 1112.4000 143.9600 ;
    END
  END dmamasterout_66
  PIN dmamasterout_67
    DIRECTION OUTPUT ;
    USE SIGNAL ;
    PORT
      LAYER Metal2 ;
        RECT 1109.0650 0.0000 1109.1350 0.2900 ;
    END
  END dmamasterout_67
  PIN dmamasterout_68
    DIRECTION OUTPUT ;
    USE SIGNAL ;
    PORT
      LAYER Metal4 ;
        RECT 1032.8650 0.0000 1032.9350 0.2900 ;
    END
  END dmamasterout_68
  PIN dmamasterout_71
    DIRECTION OUTPUT ;
    USE SIGNAL ;
    PORT
      LAYER Metal4 ;
        RECT 1057.8650 0.0000 1057.9350 0.2900 ;
    END
  END dmamasterout_71
  PIN dmamasterout_72
    DIRECTION OUTPUT ;
    USE SIGNAL ;
    PORT
      LAYER Metal6 ;
        RECT 1047.6650 0.0000 1047.7350 0.2900 ;
    END
  END dmamasterout_72
  PIN dmamasterout_73
    DIRECTION OUTPUT ;
    USE SIGNAL ;
    PORT
      LAYER Metal4 ;
        RECT 1048.8650 0.0000 1048.9350 0.2900 ;
    END
  END dmamasterout_73
  PIN dmamasterout_74
    DIRECTION OUTPUT ;
    USE SIGNAL ;
    PORT
      LAYER Metal3 ;
        RECT 1112.1100 150.7300 1112.4000 150.8000 ;
    END
  END dmamasterout_74
  PIN dmamasterout_75
    DIRECTION OUTPUT ;
    USE SIGNAL ;
    PORT
      LAYER Metal8 ;
        RECT 1091.4650 0.0000 1091.5350 0.2900 ;
    END
  END dmamasterout_75
  PIN dmamasterout_76
    DIRECTION OUTPUT ;
    USE SIGNAL ;
    PORT
      LAYER Metal2 ;
        RECT 1093.0650 0.0000 1093.1350 0.2900 ;
    END
  END dmamasterout_76
  PIN dmamasterout_77
    DIRECTION OUTPUT ;
    USE SIGNAL ;
    PORT
      LAYER Metal3 ;
        RECT 1112.1100 340.3500 1112.4000 340.4200 ;
    END
  END dmamasterout_77
  PIN dmamasterout_78
    DIRECTION OUTPUT ;
    USE SIGNAL ;
    PORT
      LAYER Metal6 ;
        RECT 1092.4650 0.0000 1092.5350 0.2900 ;
    END
  END dmamasterout_78
  PIN dmamasterin_0
    DIRECTION INPUT ;
    USE SIGNAL ;
    PORT
      LAYER Metal3 ;
        RECT 1112.1100 1516.8300 1112.4000 1516.9000 ;
    END
  END dmamasterin_0
  PIN dmamasterin_1
    DIRECTION INPUT ;
    USE SIGNAL ;
    PORT
      LAYER Metal2 ;
        RECT 875.2650 0.0000 875.3350 0.2900 ;
    END
  END dmamasterin_1
  PIN dmamasterin_2
    DIRECTION INPUT ;
    USE SIGNAL ;
    PORT
      LAYER Metal2 ;
        RECT 878.8650 0.0000 878.9350 0.2900 ;
    END
  END dmamasterin_2
  PIN dmamasterin_3
    DIRECTION INPUT ;
    USE SIGNAL ;
    PORT
      LAYER Metal2 ;
        RECT 876.6650 0.0000 876.7350 0.2900 ;
    END
  END dmamasterin_3
  PIN dmamasterin_4
    DIRECTION INPUT ;
    USE SIGNAL ;
    PORT
      LAYER Metal4 ;
        RECT 875.4650 0.0000 875.5350 0.2900 ;
    END
  END dmamasterin_4
  PIN dmamasterin_5
    DIRECTION INPUT ;
    USE SIGNAL ;
    PORT
      LAYER Metal2 ;
        RECT 875.6650 0.0000 875.7350 0.2900 ;
    END
  END dmamasterin_5
  PIN dmamasterin_6
    DIRECTION INPUT ;
    USE SIGNAL ;
    PORT
      LAYER Metal2 ;
        RECT 862.8650 0.0000 862.9350 0.2900 ;
    END
  END dmamasterin_6
  PIN dmamasterin_7
    DIRECTION INPUT ;
    USE SIGNAL ;
    PORT
      LAYER Metal4 ;
        RECT 853.6650 0.0000 853.7350 0.2900 ;
    END
  END dmamasterin_7
  PIN dmamasterin_8
    DIRECTION INPUT ;
    USE SIGNAL ;
    PORT
      LAYER Metal5 ;
        RECT 1112.1100 1491.7500 1112.4000 1491.8200 ;
    END
  END dmamasterin_8
  PIN dmamasterin_9
    DIRECTION INPUT ;
    USE SIGNAL ;
    PORT
      LAYER Metal7 ;
        RECT 1112.1100 1492.1300 1112.4000 1492.2000 ;
    END
  END dmamasterin_9
  PIN dmamasterin_10
    DIRECTION INPUT ;
    USE SIGNAL ;
    PORT
      LAYER Metal2 ;
        RECT 851.8650 0.0000 851.9350 0.2900 ;
    END
  END dmamasterin_10
  PIN dmamasterin_11
    DIRECTION INPUT ;
    USE SIGNAL ;
    PORT
      LAYER Metal3 ;
        RECT 1112.1100 1491.7500 1112.4000 1491.8200 ;
    END
  END dmamasterin_11
  PIN dmamasterin_12
    DIRECTION INPUT ;
    USE SIGNAL ;
    PORT
      LAYER Metal3 ;
        RECT 1112.1100 232.8100 1112.4000 232.8800 ;
    END
  END dmamasterin_12
  PIN dmamasterin_13
    DIRECTION INPUT ;
    USE SIGNAL ;
    PORT
      LAYER Metal3 ;
        RECT 1112.1100 1491.3700 1112.4000 1491.4400 ;
    END
  END dmamasterin_13
  PIN dmamasterin_14
    DIRECTION INPUT ;
    USE SIGNAL ;
    PORT
      LAYER Metal5 ;
        RECT 1112.1100 1492.1300 1112.4000 1492.2000 ;
    END
  END dmamasterin_14
  PIN dmamasterin_15
    DIRECTION INPUT ;
    USE SIGNAL ;
    PORT
      LAYER Metal2 ;
        RECT 851.4650 0.0000 851.5350 0.2900 ;
    END
  END dmamasterin_15
  PIN dmamasterin_16
    DIRECTION INPUT ;
    USE SIGNAL ;
    PORT
      LAYER Metal4 ;
        RECT 851.6650 0.0000 851.7350 0.2900 ;
    END
  END dmamasterin_16
  PIN dmamasterin_17
    DIRECTION INPUT ;
    USE SIGNAL ;
    PORT
      LAYER Metal3 ;
        RECT 1112.1100 1485.2900 1112.4000 1485.3600 ;
    END
  END dmamasterin_17
  PIN dmamasterin_18
    DIRECTION INPUT ;
    USE SIGNAL ;
    PORT
      LAYER Metal3 ;
        RECT 1112.1100 1471.9900 1112.4000 1472.0600 ;
    END
  END dmamasterin_18
  PIN dmamasterin_19
    DIRECTION INPUT ;
    USE SIGNAL ;
    PORT
      LAYER Metal3 ;
        RECT 1112.1100 1471.6100 1112.4000 1471.6800 ;
    END
  END dmamasterin_19
  PIN dmamasterin_20
    DIRECTION INPUT ;
    USE SIGNAL ;
    PORT
      LAYER Metal3 ;
        RECT 1112.1100 1471.2300 1112.4000 1471.3000 ;
    END
  END dmamasterin_20
  PIN dmamasterin_21
    DIRECTION INPUT ;
    USE SIGNAL ;
    PORT
      LAYER Metal3 ;
        RECT 1112.1100 1470.8500 1112.4000 1470.9200 ;
    END
  END dmamasterin_21
  PIN dmamasterin_22
    DIRECTION INPUT ;
    USE SIGNAL ;
    PORT
      LAYER Metal6 ;
        RECT 851.4650 0.0000 851.5350 0.2900 ;
    END
  END dmamasterin_22
  PIN dmamasterin_23
    DIRECTION INPUT ;
    USE SIGNAL ;
    PORT
      LAYER Metal3 ;
        RECT 1112.1100 233.9500 1112.4000 234.0200 ;
    END
  END dmamasterin_23
  PIN dmamasterin_24
    DIRECTION INPUT ;
    USE SIGNAL ;
    PORT
      LAYER Metal4 ;
        RECT 856.6650 0.0000 856.7350 0.2900 ;
    END
  END dmamasterin_24
  PIN dmamasterin_25
    DIRECTION INPUT ;
    USE SIGNAL ;
    PORT
      LAYER Metal4 ;
        RECT 860.6650 0.0000 860.7350 0.2900 ;
    END
  END dmamasterin_25
  PIN dmamasterin_26
    DIRECTION INPUT ;
    USE SIGNAL ;
    PORT
      LAYER Metal4 ;
        RECT 863.4650 0.0000 863.5350 0.2900 ;
    END
  END dmamasterin_26
  PIN dmamasterin_27
    DIRECTION INPUT ;
    USE SIGNAL ;
    PORT
      LAYER Metal2 ;
        RECT 867.8650 0.0000 867.9350 0.2900 ;
    END
  END dmamasterin_27
  PIN dmamasterin_28
    DIRECTION INPUT ;
    USE SIGNAL ;
    PORT
      LAYER Metal5 ;
        RECT 1112.1100 1491.3700 1112.4000 1491.4400 ;
    END
  END dmamasterin_28
  PIN dmamasterin_29
    DIRECTION INPUT ;
    USE SIGNAL ;
    PORT
      LAYER Metal2 ;
        RECT 874.8650 0.0000 874.9350 0.2900 ;
    END
  END dmamasterin_29
  PIN dmamasterin_30
    DIRECTION INPUT ;
    USE SIGNAL ;
    PORT
      LAYER Metal4 ;
        RECT 876.8650 0.0000 876.9350 0.2900 ;
    END
  END dmamasterin_30
  PIN dmamasterin_31
    DIRECTION INPUT ;
    USE SIGNAL ;
    PORT
      LAYER Metal2 ;
        RECT 986.4650 0.0000 986.5350 0.2900 ;
    END
  END dmamasterin_31
  PIN dmamasterin_32
    DIRECTION INPUT ;
    USE SIGNAL ;
    PORT
      LAYER Metal2 ;
        RECT 1099.4650 0.0000 1099.5350 0.2900 ;
    END
  END dmamasterin_32
  PIN dmamasterin_33
    DIRECTION INPUT ;
    USE SIGNAL ;
    PORT
      LAYER Metal4 ;
        RECT 1099.6650 0.0000 1099.7350 0.2900 ;
    END
  END dmamasterin_33
  PIN dmamasterin_35
    DIRECTION INPUT ;
    USE SIGNAL ;
    PORT
      LAYER Metal2 ;
        RECT 1036.6650 0.0000 1036.7350 0.2900 ;
    END
  END dmamasterin_35
  PIN dmamasterin_36
    DIRECTION INPUT ;
    USE SIGNAL ;
    PORT
      LAYER Metal2 ;
        RECT 1055.8650 0.0000 1055.9350 0.2900 ;
    END
  END dmamasterin_36
  PIN n_20008
    DIRECTION INPUT ;
    USE SIGNAL ;
    PORT
      LAYER Metal5 ;
        RECT 1112.1100 1.3900 1112.4000 1.4600 ;
    END
  END n_20008
  PIN n_28353
    DIRECTION OUTPUT ;
    USE SIGNAL ;
    PORT
      LAYER Metal3 ;
        RECT 1112.1100 857.7200 1112.4000 857.7900 ;
    END
  END n_28353
  PIN n_26795
    DIRECTION OUTPUT ;
    USE SIGNAL ;
    PORT
      LAYER Metal3 ;
        RECT 1112.1100 511.3500 1112.4000 511.4200 ;
    END
  END n_26795
  PIN n_26787
    DIRECTION INPUT ;
    USE SIGNAL ;
    PORT
      LAYER Metal4 ;
        RECT 1054.8650 0.0000 1054.9350 0.2900 ;
    END
  END n_26787
  PIN utmi_usb_vbus_2core
    DIRECTION INPUT ;
    USE SIGNAL ;
    PORT
      LAYER Metal9 ;
        RECT 0.0000 1696.5700 0.2900 1696.6400 ;
    END
  END utmi_usb_vbus_2core
  PIN utmi_suspendm_2pad
    DIRECTION OUTPUT ;
    USE SIGNAL ;
    PORT
      LAYER Metal9 ;
        RECT 0.0000 1952.6900 0.2900 1952.7600 ;
    END
  END utmi_suspendm_2pad
  PIN n_28391
    DIRECTION OUTPUT ;
    USE SIGNAL ;
    PORT
      LAYER Metal3 ;
        RECT 1112.1100 900.0900 1112.4000 900.1600 ;
    END
  END n_28391
  PIN n_28352
    DIRECTION OUTPUT ;
    USE SIGNAL ;
    PORT
      LAYER Metal5 ;
        RECT 1112.1100 857.7200 1112.4000 857.7900 ;
    END
  END n_28352
  PIN utmi_rxactive_2core
    DIRECTION INPUT ;
    USE SIGNAL ;
    PORT
      LAYER Metal9 ;
        RECT 0.0000 1570.4100 0.2900 1570.4800 ;
    END
  END utmi_rxactive_2core
  PIN utmi_rxvalid_2core
    DIRECTION INPUT ;
    USE SIGNAL ;
    PORT
      LAYER Metal9 ;
        RECT 0.0000 1633.4900 0.2900 1633.5600 ;
    END
  END utmi_rxvalid_2core
  PIN utmi_txready_2core
    DIRECTION INPUT ;
    USE SIGNAL ;
    PORT
      LAYER Metal9 ;
        RECT 0.0000 1443.8700 0.2900 1443.9400 ;
    END
  END utmi_txready_2core
  PIN utmi_txvalid_2pad
    DIRECTION OUTPUT ;
    USE SIGNAL ;
    PORT
      LAYER Metal9 ;
        RECT 0.0000 1384.2100 0.2900 1384.2800 ;
    END
  END utmi_txvalid_2pad
  PIN utmi_phy_rst_2pad
    DIRECTION OUTPUT ;
    USE SIGNAL ;
    PORT
      LAYER Metal7 ;
        RECT 0.0000 1588.1750 0.2900 1588.2450 ;
    END
  END utmi_phy_rst_2pad
  PIN utmi_phy_clk_2core
    DIRECTION INPUT ;
    USE SIGNAL ;
    PORT
      LAYER Metal8 ;
        RECT 423.6650 0.0000 423.7350 0.2900 ;
    END
  END utmi_phy_clk_2core
  PIN usbslaveout_0
    DIRECTION OUTPUT ;
    USE SIGNAL ;
    PORT
      LAYER Metal7 ;
        RECT 1112.1100 10.4150 1112.4000 10.4850 ;
    END
  END usbslaveout_0
  PIN usbslaveout_1
    DIRECTION OUTPUT ;
    USE SIGNAL ;
    PORT
      LAYER Metal3 ;
        RECT 1112.1100 8.6100 1112.4000 8.6800 ;
    END
  END usbslaveout_1
  PIN usbslaveout_2
    DIRECTION OUTPUT ;
    USE SIGNAL ;
    PORT
      LAYER Metal2 ;
        RECT 947.2650 0.0000 947.3350 0.2900 ;
    END
  END usbslaveout_2
  PIN usbslaveout_3
    DIRECTION OUTPUT ;
    USE SIGNAL ;
    PORT
      LAYER Metal4 ;
        RECT 947.8650 0.0000 947.9350 0.2900 ;
    END
  END usbslaveout_3
  PIN usbslaveout_4
    DIRECTION OUTPUT ;
    USE SIGNAL ;
    PORT
      LAYER Metal5 ;
        RECT 1112.1100 15.0700 1112.4000 15.1400 ;
    END
  END usbslaveout_4
  PIN usbslaveout_5
    DIRECTION OUTPUT ;
    USE SIGNAL ;
    PORT
      LAYER Metal3 ;
        RECT 1112.1100 15.4500 1112.4000 15.5200 ;
    END
  END usbslaveout_5
  PIN usbslaveout_6
    DIRECTION OUTPUT ;
    USE SIGNAL ;
    PORT
      LAYER Metal2 ;
        RECT 941.0650 0.0000 941.1350 0.2900 ;
    END
  END usbslaveout_6
  PIN usbslaveout_7
    DIRECTION OUTPUT ;
    USE SIGNAL ;
    PORT
      LAYER Metal2 ;
        RECT 936.8650 0.0000 936.9350 0.2900 ;
    END
  END usbslaveout_7
  PIN usbslaveout_8
    DIRECTION OUTPUT ;
    USE SIGNAL ;
    PORT
      LAYER Metal2 ;
        RECT 932.8650 0.0000 932.9350 0.2900 ;
    END
  END usbslaveout_8
  PIN usbslaveout_9
    DIRECTION OUTPUT ;
    USE SIGNAL ;
    PORT
      LAYER Metal2 ;
        RECT 925.8650 0.0000 925.9350 0.2900 ;
    END
  END usbslaveout_9
  PIN usbslaveout_10
    DIRECTION OUTPUT ;
    USE SIGNAL ;
    PORT
      LAYER Metal2 ;
        RECT 924.8650 0.0000 924.9350 0.2900 ;
    END
  END usbslaveout_10
  PIN usbslaveout_11
    DIRECTION OUTPUT ;
    USE SIGNAL ;
    PORT
      LAYER Metal4 ;
        RECT 918.6650 0.0000 918.7350 0.2900 ;
    END
  END usbslaveout_11
  PIN usbslaveout_12
    DIRECTION OUTPUT ;
    USE SIGNAL ;
    PORT
      LAYER Metal2 ;
        RECT 920.8650 0.0000 920.9350 0.2900 ;
    END
  END usbslaveout_12
  PIN usbslaveout_13
    DIRECTION OUTPUT ;
    USE SIGNAL ;
    PORT
      LAYER Metal2 ;
        RECT 929.8650 0.0000 929.9350 0.2900 ;
    END
  END usbslaveout_13
  PIN usbslaveout_14
    DIRECTION OUTPUT ;
    USE SIGNAL ;
    PORT
      LAYER Metal2 ;
        RECT 934.0650 0.0000 934.1350 0.2900 ;
    END
  END usbslaveout_14
  PIN usbslaveout_15
    DIRECTION OUTPUT ;
    USE SIGNAL ;
    PORT
      LAYER Metal2 ;
        RECT 941.8650 0.0000 941.9350 0.2900 ;
    END
  END usbslaveout_15
  PIN usbslaveout_16
    DIRECTION OUTPUT ;
    USE SIGNAL ;
    PORT
      LAYER Metal4 ;
        RECT 940.4650 0.0000 940.5350 0.2900 ;
    END
  END usbslaveout_16
  PIN usbslaveout_17
    DIRECTION OUTPUT ;
    USE SIGNAL ;
    PORT
      LAYER Metal6 ;
        RECT 940.6650 0.0000 940.7350 0.2900 ;
    END
  END usbslaveout_17
  PIN usbslaveout_18
    DIRECTION OUTPUT ;
    USE SIGNAL ;
    PORT
      LAYER Metal4 ;
        RECT 940.8650 0.0000 940.9350 0.2900 ;
    END
  END usbslaveout_18
  PIN usbslaveout_19
    DIRECTION OUTPUT ;
    USE SIGNAL ;
    PORT
      LAYER Metal2 ;
        RECT 940.0650 0.0000 940.1350 0.2900 ;
    END
  END usbslaveout_19
  PIN usbslaveout_20
    DIRECTION OUTPUT ;
    USE SIGNAL ;
    PORT
      LAYER Metal4 ;
        RECT 945.4650 0.0000 945.5350 0.2900 ;
    END
  END usbslaveout_20
  PIN usbslaveout_21
    DIRECTION OUTPUT ;
    USE SIGNAL ;
    PORT
      LAYER Metal4 ;
        RECT 947.4650 0.0000 947.5350 0.2900 ;
    END
  END usbslaveout_21
  PIN usbslaveout_22
    DIRECTION OUTPUT ;
    USE SIGNAL ;
    PORT
      LAYER Metal6 ;
        RECT 940.2650 0.0000 940.3350 0.2900 ;
    END
  END usbslaveout_22
  PIN usbslaveout_23
    DIRECTION OUTPUT ;
    USE SIGNAL ;
    PORT
      LAYER Metal3 ;
        RECT 1112.1100 25.7100 1112.4000 25.7800 ;
    END
  END usbslaveout_23
  PIN usbslaveout_24
    DIRECTION OUTPUT ;
    USE SIGNAL ;
    PORT
      LAYER Metal4 ;
        RECT 933.8650 0.0000 933.9350 0.2900 ;
    END
  END usbslaveout_24
  PIN usbslaveout_25
    DIRECTION OUTPUT ;
    USE SIGNAL ;
    PORT
      LAYER Metal6 ;
        RECT 928.8650 0.0000 928.9350 0.2900 ;
    END
  END usbslaveout_25
  PIN usbslaveout_26
    DIRECTION OUTPUT ;
    USE SIGNAL ;
    PORT
      LAYER Metal2 ;
        RECT 927.8650 0.0000 927.9350 0.2900 ;
    END
  END usbslaveout_26
  PIN usbslaveout_27
    DIRECTION OUTPUT ;
    USE SIGNAL ;
    PORT
      LAYER Metal3 ;
        RECT 1112.1100 26.4700 1112.4000 26.5400 ;
    END
  END usbslaveout_27
  PIN usbslaveout_28
    DIRECTION OUTPUT ;
    USE SIGNAL ;
    PORT
      LAYER Metal3 ;
        RECT 1112.1100 21.1500 1112.4000 21.2200 ;
    END
  END usbslaveout_28
  PIN usbslaveout_29
    DIRECTION OUTPUT ;
    USE SIGNAL ;
    PORT
      LAYER Metal3 ;
        RECT 1112.1100 18.8700 1112.4000 18.9400 ;
    END
  END usbslaveout_29
  PIN usbslaveout_30
    DIRECTION OUTPUT ;
    USE SIGNAL ;
    PORT
      LAYER Metal7 ;
        RECT 1112.1100 15.8300 1112.4000 15.9000 ;
    END
  END usbslaveout_30
  PIN usbslaveout_31
    DIRECTION OUTPUT ;
    USE SIGNAL ;
    PORT
      LAYER Metal3 ;
        RECT 1112.1100 17.3500 1112.4000 17.4200 ;
    END
  END usbslaveout_31
  PIN usbslaveout_32
    DIRECTION OUTPUT ;
    USE SIGNAL ;
    PORT
      LAYER Metal3 ;
        RECT 0.0000 1588.2700 0.2900 1588.3400 ;
    END
  END usbslaveout_32
  PIN usbslaveout_33
    DIRECTION OUTPUT ;
    USE SIGNAL ;
    PORT
      LAYER Metal5 ;
        RECT 0.0000 1588.2700 0.2900 1588.3400 ;
    END
  END usbslaveout_33
  PIN usbslaveout_34
    DIRECTION OUTPUT ;
    USE SIGNAL ;
    PORT
      LAYER Metal9 ;
        RECT 0.0000 1583.7100 0.2900 1583.7800 ;
    END
  END usbslaveout_34
  PIN usbslaveout_35
    DIRECTION OUTPUT ;
    USE SIGNAL ;
    PORT
      LAYER Metal9 ;
        RECT 0.0000 1588.2700 0.2900 1588.3400 ;
    END
  END usbslaveout_35
  PIN usbslaveout_36
    DIRECTION OUTPUT ;
    USE SIGNAL ;
    PORT
      LAYER Metal7 ;
        RECT 0.0000 1583.6150 0.2900 1583.6850 ;
    END
  END usbslaveout_36
  PIN usbslaveout_37
    DIRECTION OUTPUT ;
    USE SIGNAL ;
    PORT
      LAYER Metal7 ;
        RECT 0.0000 1588.7450 0.2900 1588.8150 ;
    END
  END usbslaveout_37
  PIN usbslaveout_38
    DIRECTION OUTPUT ;
    USE SIGNAL ;
    PORT
      LAYER Metal7 ;
        RECT 0.0000 1583.0450 0.2900 1583.1150 ;
    END
  END usbslaveout_38
  PIN usbslaveout_39
    DIRECTION OUTPUT ;
    USE SIGNAL ;
    PORT
      LAYER Metal9 ;
        RECT 0.0000 1582.9500 0.2900 1583.0200 ;
    END
  END usbslaveout_39
  PIN usbslaveout_40
    DIRECTION OUTPUT ;
    USE SIGNAL ;
    PORT
      LAYER Metal9 ;
        RECT 0.0000 1589.0300 0.2900 1589.1000 ;
    END
  END usbslaveout_40
  PIN usbslaveout_41
    DIRECTION OUTPUT ;
    USE SIGNAL ;
    PORT
      LAYER Metal3 ;
        RECT 0.0000 1582.7600 0.2900 1582.8300 ;
    END
  END usbslaveout_41
  PIN usbslaveout_42
    DIRECTION OUTPUT ;
    USE SIGNAL ;
    PORT
      LAYER Metal5 ;
        RECT 0.0000 1582.7600 0.2900 1582.8300 ;
    END
  END usbslaveout_42
  PIN usbslaveout_43
    DIRECTION OUTPUT ;
    USE SIGNAL ;
    PORT
      LAYER Metal7 ;
        RECT 0.0000 1589.3150 0.2900 1589.3850 ;
    END
  END usbslaveout_43
  PIN usbslaveout_44
    DIRECTION OUTPUT ;
    USE SIGNAL ;
    PORT
      LAYER Metal7 ;
        RECT 0.0000 1582.4750 0.2900 1582.5450 ;
    END
  END usbslaveout_44
  PIN usbslaveout_45
    DIRECTION OUTPUT ;
    USE SIGNAL ;
    PORT
      LAYER Metal9 ;
        RECT 0.0000 1582.1900 0.2900 1582.2600 ;
    END
  END usbslaveout_45
  PIN usbslaveout_46
    DIRECTION OUTPUT ;
    USE SIGNAL ;
    PORT
      LAYER Metal9 ;
        RECT 0.0000 1589.7900 0.2900 1589.8600 ;
    END
  END usbslaveout_46
  PIN usbslaveout_47
    DIRECTION OUTPUT ;
    USE SIGNAL ;
    PORT
      LAYER Metal7 ;
        RECT 0.0000 1589.8850 0.2900 1589.9550 ;
    END
  END usbslaveout_47
  PIN usbslaveout_48
    DIRECTION OUTPUT ;
    USE SIGNAL ;
    PORT
      LAYER Metal2 ;
        RECT 1067.2650 0.0000 1067.3350 0.2900 ;
    END
  END usbslaveout_48
  PIN usbslaveout_50
    DIRECTION OUTPUT ;
    USE SIGNAL ;
    PORT
      LAYER Metal4 ;
        RECT 1068.6650 0.0000 1068.7350 0.2900 ;
    END
  END usbslaveout_50
  PIN usbslavein_0
    DIRECTION INPUT ;
    USE SIGNAL ;
    PORT
      LAYER Metal3 ;
        RECT 1112.1100 26.0900 1112.4000 26.1600 ;
    END
  END usbslavein_0
  PIN usbslavein_1
    DIRECTION INPUT ;
    USE SIGNAL ;
    PORT
      LAYER Metal3 ;
        RECT 1112.1100 22.6700 1112.4000 22.7400 ;
    END
  END usbslavein_1
  PIN usbslavein_2
    DIRECTION INPUT ;
    USE SIGNAL ;
    PORT
      LAYER Metal3 ;
        RECT 1112.1100 21.5300 1112.4000 21.6000 ;
    END
  END usbslavein_2
  PIN usbslavein_3
    DIRECTION INPUT ;
    USE SIGNAL ;
    PORT
      LAYER Metal3 ;
        RECT 1112.1100 22.2900 1112.4000 22.3600 ;
    END
  END usbslavein_3
  PIN usbslavein_4
    DIRECTION INPUT ;
    USE SIGNAL ;
    PORT
      LAYER Metal3 ;
        RECT 1112.1100 31.4100 1112.4000 31.4800 ;
    END
  END usbslavein_4
  PIN usbslavein_5
    DIRECTION INPUT ;
    USE SIGNAL ;
    PORT
      LAYER Metal3 ;
        RECT 1112.1100 24.5700 1112.4000 24.6400 ;
    END
  END usbslavein_5
  PIN usbslavein_6
    DIRECTION INPUT ;
    USE SIGNAL ;
    PORT
      LAYER Metal3 ;
        RECT 1112.1100 17.7300 1112.4000 17.8000 ;
    END
  END usbslavein_6
  PIN usbslavein_7
    DIRECTION INPUT ;
    USE SIGNAL ;
    PORT
      LAYER Metal3 ;
        RECT 1112.1100 14.3100 1112.4000 14.3800 ;
    END
  END usbslavein_7
  PIN usbslavein_8
    DIRECTION INPUT ;
    USE SIGNAL ;
    PORT
      LAYER Metal3 ;
        RECT 1112.1100 13.9300 1112.4000 14.0000 ;
    END
  END usbslavein_8
  PIN usbslavein_9
    DIRECTION INPUT ;
    USE SIGNAL ;
    PORT
      LAYER Metal2 ;
        RECT 698.4650 0.0000 698.5350 0.2900 ;
    END
  END usbslavein_9
  PIN usbslavein_10
    DIRECTION INPUT ;
    USE SIGNAL ;
    PORT
      LAYER Metal2 ;
        RECT 695.8650 0.0000 695.9350 0.2900 ;
    END
  END usbslavein_10
  PIN usbslavein_11
    DIRECTION INPUT ;
    USE SIGNAL ;
    PORT
      LAYER Metal2 ;
        RECT 693.8650 0.0000 693.9350 0.2900 ;
    END
  END usbslavein_11
  PIN usbslavein_12
    DIRECTION INPUT ;
    USE SIGNAL ;
    PORT
      LAYER Metal2 ;
        RECT 689.8650 0.0000 689.9350 0.2900 ;
    END
  END usbslavein_12
  PIN usbslavein_13
    DIRECTION INPUT ;
    USE SIGNAL ;
    PORT
      LAYER Metal2 ;
        RECT 685.8650 0.0000 685.9350 0.2900 ;
    END
  END usbslavein_13
  PIN usbslavein_14
    DIRECTION INPUT ;
    USE SIGNAL ;
    PORT
      LAYER Metal3 ;
        RECT 1112.1100 6.3300 1112.4000 6.4000 ;
    END
  END usbslavein_14
  PIN usbslavein_15
    DIRECTION INPUT ;
    USE SIGNAL ;
    PORT
      LAYER Metal3 ;
        RECT 1112.1100 16.2100 1112.4000 16.2800 ;
    END
  END usbslavein_15
  PIN usbslavein_16
    DIRECTION INPUT ;
    USE SIGNAL ;
    PORT
      LAYER Metal3 ;
        RECT 1112.1100 31.7900 1112.4000 31.8600 ;
    END
  END usbslavein_16
  PIN usbslavein_17
    DIRECTION INPUT ;
    USE SIGNAL ;
    PORT
      LAYER Metal3 ;
        RECT 1112.1100 45.0900 1112.4000 45.1600 ;
    END
  END usbslavein_17
  PIN usbslavein_18
    DIRECTION INPUT ;
    USE SIGNAL ;
    PORT
      LAYER Metal3 ;
        RECT 1112.1100 46.6100 1112.4000 46.6800 ;
    END
  END usbslavein_18
  PIN usbslavein_19
    DIRECTION INPUT ;
    USE SIGNAL ;
    PORT
      LAYER Metal3 ;
        RECT 1112.1100 46.2300 1112.4000 46.3000 ;
    END
  END usbslavein_19
  PIN usbslavein_20
    DIRECTION INPUT ;
    USE SIGNAL ;
    PORT
      LAYER Metal3 ;
        RECT 1112.1100 51.9300 1112.4000 52.0000 ;
    END
  END usbslavein_20
  PIN usbslavein_21
    DIRECTION INPUT ;
    USE SIGNAL ;
    PORT
      LAYER Metal3 ;
        RECT 1112.1100 51.5500 1112.4000 51.6200 ;
    END
  END usbslavein_21
  PIN usbslavein_22
    DIRECTION INPUT ;
    USE SIGNAL ;
    PORT
      LAYER Metal2 ;
        RECT 711.6650 0.0000 711.7350 0.2900 ;
    END
  END usbslavein_22
  PIN usbslavein_23
    DIRECTION INPUT ;
    USE SIGNAL ;
    PORT
      LAYER Metal4 ;
        RECT 711.8650 0.0000 711.9350 0.2900 ;
    END
  END usbslavein_23
  PIN usbslavein_24
    DIRECTION INPUT ;
    USE SIGNAL ;
    PORT
      LAYER Metal2 ;
        RECT 698.0650 0.0000 698.1350 0.2900 ;
    END
  END usbslavein_24
  PIN usbslavein_25
    DIRECTION INPUT ;
    USE SIGNAL ;
    PORT
      LAYER Metal6 ;
        RECT 711.6650 0.0000 711.7350 0.2900 ;
    END
  END usbslavein_25
  PIN usbslavein_26
    DIRECTION INPUT ;
    USE SIGNAL ;
    PORT
      LAYER Metal8 ;
        RECT 711.8650 0.0000 711.9350 0.2900 ;
    END
  END usbslavein_26
  PIN usbslavein_27
    DIRECTION INPUT ;
    USE SIGNAL ;
    PORT
      LAYER Metal4 ;
        RECT 711.4650 0.0000 711.5350 0.2900 ;
    END
  END usbslavein_27
  PIN usbslavein_28
    DIRECTION INPUT ;
    USE SIGNAL ;
    PORT
      LAYER Metal3 ;
        RECT 1112.1100 48.1300 1112.4000 48.2000 ;
    END
  END usbslavein_28
  PIN usbslavein_29
    DIRECTION INPUT ;
    USE SIGNAL ;
    PORT
      LAYER Metal4 ;
        RECT 698.2650 0.0000 698.3350 0.2900 ;
    END
  END usbslavein_29
  PIN usbslavein_30
    DIRECTION INPUT ;
    USE SIGNAL ;
    PORT
      LAYER Metal3 ;
        RECT 1112.1100 31.0300 1112.4000 31.1000 ;
    END
  END usbslavein_30
  PIN usbslavein_31
    DIRECTION INPUT ;
    USE SIGNAL ;
    PORT
      LAYER Metal8 ;
        RECT 711.4650 0.0000 711.5350 0.2900 ;
    END
  END usbslavein_31
  PIN usbslavein_34
    DIRECTION INPUT ;
    USE SIGNAL ;
    PORT
      LAYER Metal4 ;
        RECT 1051.8650 0.0000 1051.9350 0.2900 ;
    END
  END usbslavein_34
  PIN usbslavein_35
    DIRECTION INPUT ;
    USE SIGNAL ;
    PORT
      LAYER Metal2 ;
        RECT 1048.8650 0.0000 1048.9350 0.2900 ;
    END
  END usbslavein_35
  PIN usbslavein_36
    DIRECTION INPUT ;
    USE SIGNAL ;
    PORT
      LAYER Metal2 ;
        RECT 1049.2650 0.0000 1049.3350 0.2900 ;
    END
  END usbslavein_36
  PIN usbslavein_37
    DIRECTION INPUT ;
    USE SIGNAL ;
    PORT
      LAYER Metal4 ;
        RECT 1047.6650 0.0000 1047.7350 0.2900 ;
    END
  END usbslavein_37
  PIN usbslavein_38
    DIRECTION INPUT ;
    USE SIGNAL ;
    PORT
      LAYER Metal2 ;
        RECT 1038.4650 0.0000 1038.5350 0.2900 ;
    END
  END usbslavein_38
  PIN usbslavein_39
    DIRECTION INPUT ;
    USE SIGNAL ;
    PORT
      LAYER Metal2 ;
        RECT 1039.8650 0.0000 1039.9350 0.2900 ;
    END
  END usbslavein_39
  PIN usbslavein_40
    DIRECTION INPUT ;
    USE SIGNAL ;
    PORT
      LAYER Metal2 ;
        RECT 1043.0650 0.0000 1043.1350 0.2900 ;
    END
  END usbslavein_40
  PIN usbslavein_41
    DIRECTION INPUT ;
    USE SIGNAL ;
    PORT
      LAYER Metal2 ;
        RECT 1026.2650 0.0000 1026.3350 0.2900 ;
    END
  END usbslavein_41
  PIN usbslavein_42
    DIRECTION INPUT ;
    USE SIGNAL ;
    PORT
      LAYER Metal2 ;
        RECT 1024.4650 0.0000 1024.5350 0.2900 ;
    END
  END usbslavein_42
  PIN usbslavein_43
    DIRECTION INPUT ;
    USE SIGNAL ;
    PORT
      LAYER Metal2 ;
        RECT 1020.2650 0.0000 1020.3350 0.2900 ;
    END
  END usbslavein_43
  PIN usbslavein_48
    DIRECTION INPUT ;
    USE SIGNAL ;
    PORT
      LAYER Metal2 ;
        RECT 1014.6650 0.0000 1014.7350 0.2900 ;
    END
  END usbslavein_48
  PIN usbslavein_76
    DIRECTION INPUT ;
    USE SIGNAL ;
    PORT
      LAYER Metal4 ;
        RECT 1095.8650 0.0000 1095.9350 0.2900 ;
    END
  END usbslavein_76
  PIN usbslavein_77
    DIRECTION INPUT ;
    USE SIGNAL ;
    PORT
      LAYER Metal4 ;
        RECT 1094.8650 0.0000 1094.9350 0.2900 ;
    END
  END usbslavein_77
  PIN usbslavein_78
    DIRECTION INPUT ;
    USE SIGNAL ;
    PORT
      LAYER Metal2 ;
        RECT 1094.4650 0.0000 1094.5350 0.2900 ;
    END
  END usbslavein_78
  PIN usbslavein_79
    DIRECTION INPUT ;
    USE SIGNAL ;
    PORT
      LAYER Metal6 ;
        RECT 1095.6650 0.0000 1095.7350 0.2900 ;
    END
  END usbslavein_79
  PIN usbslavein_80
    DIRECTION INPUT ;
    USE SIGNAL ;
    PORT
      LAYER Metal8 ;
        RECT 1095.8650 0.0000 1095.9350 0.2900 ;
    END
  END usbslavein_80
  PIN usbslavein_81
    DIRECTION INPUT ;
    USE SIGNAL ;
    PORT
      LAYER Metal2 ;
        RECT 1068.8650 0.0000 1068.9350 0.2900 ;
    END
  END usbslavein_81
  PIN usbslavein_82
    DIRECTION INPUT ;
    USE SIGNAL ;
    PORT
      LAYER Metal2 ;
        RECT 1066.2650 0.0000 1066.3350 0.2900 ;
    END
  END usbslavein_82
  PIN usbslavein_83
    DIRECTION INPUT ;
    USE SIGNAL ;
    PORT
      LAYER Metal2 ;
        RECT 1061.6650 0.0000 1061.7350 0.2900 ;
    END
  END usbslavein_83
  PIN n_28141
    DIRECTION OUTPUT ;
    USE SIGNAL ;
    PORT
      LAYER Metal3 ;
        RECT 1112.1100 1703.7900 1112.4000 1703.8600 ;
    END
  END n_28141
  PIN ide_diow_n_2pad
    DIRECTION OUTPUT ;
    USE SIGNAL ;
    PORT
      LAYER Metal2 ;
        RECT 783.0650 0.0000 783.1350 0.2900 ;
    END
  END ide_diow_n_2pad
  PIN ide_dior_n_2pad
    DIRECTION OUTPUT ;
    USE SIGNAL ;
    PORT
      LAYER Metal2 ;
        RECT 748.0650 0.0000 748.1350 0.2900 ;
    END
  END ide_dior_n_2pad
  PIN ide_dmack_n_2pad
    DIRECTION OUTPUT ;
    USE SIGNAL ;
    PORT
      LAYER Metal2 ;
        RECT 756.0650 0.0000 756.1350 0.2900 ;
    END
  END ide_dmack_n_2pad
  PIN ide_dd_en
    DIRECTION OUTPUT ;
    USE SIGNAL ;
    PORT
      LAYER Metal8 ;
        RECT 90.6650 0.0000 90.7350 0.2900 ;
    END
  END ide_dd_en
  PIN ide_reset_n_2pad
    DIRECTION OUTPUT ;
    USE SIGNAL ;
    PORT
      LAYER Metal9 ;
        RECT 0.0000 437.2500 0.2900 437.3200 ;
    END
  END ide_reset_n_2pad
  PIN ataslaveout_0
    DIRECTION OUTPUT ;
    USE SIGNAL ;
    PORT
      LAYER Metal2 ;
        RECT 1008.2650 0.0000 1008.3350 0.2900 ;
    END
  END ataslaveout_0
  PIN ataslaveout_1
    DIRECTION OUTPUT ;
    USE SIGNAL ;
    PORT
      LAYER Metal2 ;
        RECT 993.8650 0.0000 993.9350 0.2900 ;
    END
  END ataslaveout_1
  PIN ataslaveout_2
    DIRECTION OUTPUT ;
    USE SIGNAL ;
    PORT
      LAYER Metal2 ;
        RECT 992.4650 0.0000 992.5350 0.2900 ;
    END
  END ataslaveout_2
  PIN ataslaveout_3
    DIRECTION OUTPUT ;
    USE SIGNAL ;
    PORT
      LAYER Metal5 ;
        RECT 1112.1100 10.7000 1112.4000 10.7700 ;
    END
  END ataslaveout_3
  PIN ataslaveout_4
    DIRECTION OUTPUT ;
    USE SIGNAL ;
    PORT
      LAYER Metal6 ;
        RECT 986.6650 0.0000 986.7350 0.2900 ;
    END
  END ataslaveout_4
  PIN ataslaveout_5
    DIRECTION OUTPUT ;
    USE SIGNAL ;
    PORT
      LAYER Metal4 ;
        RECT 981.6650 0.0000 981.7350 0.2900 ;
    END
  END ataslaveout_5
  PIN ataslaveout_6
    DIRECTION OUTPUT ;
    USE SIGNAL ;
    PORT
      LAYER Metal6 ;
        RECT 974.2650 0.0000 974.3350 0.2900 ;
    END
  END ataslaveout_6
  PIN ataslaveout_7
    DIRECTION OUTPUT ;
    USE SIGNAL ;
    PORT
      LAYER Metal2 ;
        RECT 968.8650 0.0000 968.9350 0.2900 ;
    END
  END ataslaveout_7
  PIN ataslaveout_8
    DIRECTION OUTPUT ;
    USE SIGNAL ;
    PORT
      LAYER Metal2 ;
        RECT 963.0650 0.0000 963.1350 0.2900 ;
    END
  END ataslaveout_8
  PIN ataslaveout_9
    DIRECTION OUTPUT ;
    USE SIGNAL ;
    PORT
      LAYER Metal2 ;
        RECT 957.6650 0.0000 957.7350 0.2900 ;
    END
  END ataslaveout_9
  PIN ataslaveout_10
    DIRECTION OUTPUT ;
    USE SIGNAL ;
    PORT
      LAYER Metal4 ;
        RECT 952.6650 0.0000 952.7350 0.2900 ;
    END
  END ataslaveout_10
  PIN ataslaveout_11
    DIRECTION OUTPUT ;
    USE SIGNAL ;
    PORT
      LAYER Metal4 ;
        RECT 955.8650 0.0000 955.9350 0.2900 ;
    END
  END ataslaveout_11
  PIN ataslaveout_12
    DIRECTION OUTPUT ;
    USE SIGNAL ;
    PORT
      LAYER Metal4 ;
        RECT 957.8650 0.0000 957.9350 0.2900 ;
    END
  END ataslaveout_12
  PIN ataslaveout_13
    DIRECTION OUTPUT ;
    USE SIGNAL ;
    PORT
      LAYER Metal4 ;
        RECT 962.8650 0.0000 962.9350 0.2900 ;
    END
  END ataslaveout_13
  PIN ataslaveout_14
    DIRECTION OUTPUT ;
    USE SIGNAL ;
    PORT
      LAYER Metal2 ;
        RECT 963.8650 0.0000 963.9350 0.2900 ;
    END
  END ataslaveout_14
  PIN ataslaveout_15
    DIRECTION OUTPUT ;
    USE SIGNAL ;
    PORT
      LAYER Metal2 ;
        RECT 968.0650 0.0000 968.1350 0.2900 ;
    END
  END ataslaveout_15
  PIN ataslaveout_16
    DIRECTION OUTPUT ;
    USE SIGNAL ;
    PORT
      LAYER Metal4 ;
        RECT 968.6650 0.0000 968.7350 0.2900 ;
    END
  END ataslaveout_16
  PIN ataslaveout_17
    DIRECTION OUTPUT ;
    USE SIGNAL ;
    PORT
      LAYER Metal2 ;
        RECT 974.6650 0.0000 974.7350 0.2900 ;
    END
  END ataslaveout_17
  PIN ataslaveout_18
    DIRECTION OUTPUT ;
    USE SIGNAL ;
    PORT
      LAYER Metal4 ;
        RECT 982.6650 0.0000 982.7350 0.2900 ;
    END
  END ataslaveout_18
  PIN ataslaveout_19
    DIRECTION OUTPUT ;
    USE SIGNAL ;
    PORT
      LAYER Metal7 ;
        RECT 1112.1100 9.5600 1112.4000 9.6300 ;
    END
  END ataslaveout_19
  PIN ataslaveout_20
    DIRECTION OUTPUT ;
    USE SIGNAL ;
    PORT
      LAYER Metal4 ;
        RECT 981.2650 0.0000 981.3350 0.2900 ;
    END
  END ataslaveout_20
  PIN ataslaveout_21
    DIRECTION OUTPUT ;
    USE SIGNAL ;
    PORT
      LAYER Metal6 ;
        RECT 981.6650 0.0000 981.7350 0.2900 ;
    END
  END ataslaveout_21
  PIN ataslaveout_22
    DIRECTION OUTPUT ;
    USE SIGNAL ;
    PORT
      LAYER Metal2 ;
        RECT 973.6650 0.0000 973.7350 0.2900 ;
    END
  END ataslaveout_22
  PIN ataslaveout_23
    DIRECTION OUTPUT ;
    USE SIGNAL ;
    PORT
      LAYER Metal6 ;
        RECT 973.8650 0.0000 973.9350 0.2900 ;
    END
  END ataslaveout_23
  PIN ataslaveout_24
    DIRECTION OUTPUT ;
    USE SIGNAL ;
    PORT
      LAYER Metal4 ;
        RECT 983.4650 0.0000 983.5350 0.2900 ;
    END
  END ataslaveout_24
  PIN ataslaveout_25
    DIRECTION OUTPUT ;
    USE SIGNAL ;
    PORT
      LAYER Metal6 ;
        RECT 987.8650 0.0000 987.9350 0.2900 ;
    END
  END ataslaveout_25
  PIN ataslaveout_26
    DIRECTION OUTPUT ;
    USE SIGNAL ;
    PORT
      LAYER Metal4 ;
        RECT 992.6650 0.0000 992.7350 0.2900 ;
    END
  END ataslaveout_26
  PIN ataslaveout_27
    DIRECTION OUTPUT ;
    USE SIGNAL ;
    PORT
      LAYER Metal5 ;
        RECT 1112.1100 20.7700 1112.4000 20.8400 ;
    END
  END ataslaveout_27
  PIN ataslaveout_28
    DIRECTION OUTPUT ;
    USE SIGNAL ;
    PORT
      LAYER Metal3 ;
        RECT 1112.1100 20.0100 1112.4000 20.0800 ;
    END
  END ataslaveout_28
  PIN ataslaveout_29
    DIRECTION OUTPUT ;
    USE SIGNAL ;
    PORT
      LAYER Metal2 ;
        RECT 914.0650 0.0000 914.1350 0.2900 ;
    END
  END ataslaveout_29
  PIN ataslaveout_30
    DIRECTION OUTPUT ;
    USE SIGNAL ;
    PORT
      LAYER Metal4 ;
        RECT 912.0650 0.0000 912.1350 0.2900 ;
    END
  END ataslaveout_30
  PIN ataslaveout_31
    DIRECTION OUTPUT ;
    USE SIGNAL ;
    PORT
      LAYER Metal2 ;
        RECT 912.8650 0.0000 912.9350 0.2900 ;
    END
  END ataslaveout_31
  PIN ataslaveout_32
    DIRECTION OUTPUT ;
    USE SIGNAL ;
    PORT
      LAYER Metal7 ;
        RECT 0.0000 1581.9050 0.2900 1581.9750 ;
    END
  END ataslaveout_32
  PIN ataslaveout_33
    DIRECTION OUTPUT ;
    USE SIGNAL ;
    PORT
      LAYER Metal3 ;
        RECT 0.0000 1590.1700 0.2900 1590.2400 ;
    END
  END ataslaveout_33
  PIN ataslaveout_34
    DIRECTION OUTPUT ;
    USE SIGNAL ;
    PORT
      LAYER Metal5 ;
        RECT 0.0000 1590.1700 0.2900 1590.2400 ;
    END
  END ataslaveout_34
  PIN ataslaveout_35
    DIRECTION OUTPUT ;
    USE SIGNAL ;
    PORT
      LAYER Metal7 ;
        RECT 0.0000 1590.4550 0.2900 1590.5250 ;
    END
  END ataslaveout_35
  PIN ataslaveout_36
    DIRECTION OUTPUT ;
    USE SIGNAL ;
    PORT
      LAYER Metal9 ;
        RECT 0.0000 1581.4300 0.2900 1581.5000 ;
    END
  END ataslaveout_36
  PIN ataslaveout_37
    DIRECTION OUTPUT ;
    USE SIGNAL ;
    PORT
      LAYER Metal9 ;
        RECT 0.0000 1590.5500 0.2900 1590.6200 ;
    END
  END ataslaveout_37
  PIN ataslaveout_38
    DIRECTION OUTPUT ;
    USE SIGNAL ;
    PORT
      LAYER Metal7 ;
        RECT 0.0000 1581.3350 0.2900 1581.4050 ;
    END
  END ataslaveout_38
  PIN ataslaveout_39
    DIRECTION OUTPUT ;
    USE SIGNAL ;
    PORT
      LAYER Metal7 ;
        RECT 0.0000 1591.0250 0.2900 1591.0950 ;
    END
  END ataslaveout_39
  PIN ataslaveout_40
    DIRECTION OUTPUT ;
    USE SIGNAL ;
    PORT
      LAYER Metal3 ;
        RECT 0.0000 1580.8600 0.2900 1580.9300 ;
    END
  END ataslaveout_40
  PIN ataslaveout_41
    DIRECTION OUTPUT ;
    USE SIGNAL ;
    PORT
      LAYER Metal5 ;
        RECT 0.0000 1580.8600 0.2900 1580.9300 ;
    END
  END ataslaveout_41
  PIN ataslaveout_42
    DIRECTION OUTPUT ;
    USE SIGNAL ;
    PORT
      LAYER Metal7 ;
        RECT 0.0000 1580.7650 0.2900 1580.8350 ;
    END
  END ataslaveout_42
  PIN ataslaveout_43
    DIRECTION OUTPUT ;
    USE SIGNAL ;
    PORT
      LAYER Metal9 ;
        RECT 0.0000 1580.6700 0.2900 1580.7400 ;
    END
  END ataslaveout_43
  PIN ataslaveout_44
    DIRECTION OUTPUT ;
    USE SIGNAL ;
    PORT
      LAYER Metal9 ;
        RECT 0.0000 1591.3100 0.2900 1591.3800 ;
    END
  END ataslaveout_44
  PIN ataslaveout_45
    DIRECTION OUTPUT ;
    USE SIGNAL ;
    PORT
      LAYER Metal7 ;
        RECT 0.0000 1591.5950 0.2900 1591.6650 ;
    END
  END ataslaveout_45
  PIN ataslaveout_46
    DIRECTION OUTPUT ;
    USE SIGNAL ;
    PORT
      LAYER Metal7 ;
        RECT 0.0000 1580.1950 0.2900 1580.2650 ;
    END
  END ataslaveout_46
  PIN ataslaveout_47
    DIRECTION OUTPUT ;
    USE SIGNAL ;
    PORT
      LAYER Metal3 ;
        RECT 0.0000 1592.0700 0.2900 1592.1400 ;
    END
  END ataslaveout_47
  PIN ataslaveout_48
    DIRECTION OUTPUT ;
    USE SIGNAL ;
    PORT
      LAYER Metal4 ;
        RECT 1039.8650 0.0000 1039.9350 0.2900 ;
    END
  END ataslaveout_48
  PIN ataslaveout_50
    DIRECTION OUTPUT ;
    USE SIGNAL ;
    PORT
      LAYER Metal2 ;
        RECT 1038.8650 0.0000 1038.9350 0.2900 ;
    END
  END ataslaveout_50
  PIN ide_intrq_n_2core
    DIRECTION INPUT ;
    USE SIGNAL ;
    PORT
      LAYER Metal8 ;
        RECT 29.8650 0.0000 29.9350 0.2900 ;
    END
  END ide_intrq_n_2core
  PIN ide_iordy_2core
    DIRECTION INPUT ;
    USE SIGNAL ;
    PORT
      LAYER Metal2 ;
        RECT 774.8650 0.0000 774.9350 0.2900 ;
    END
  END ide_iordy_2core
  PIN ide_dmarq_2core
    DIRECTION INPUT ;
    USE SIGNAL ;
    PORT
      LAYER Metal2 ;
        RECT 774.2650 0.0000 774.3350 0.2900 ;
    END
  END ide_dmarq_2core
  PIN ataslavein_0
    DIRECTION INPUT ;
    USE SIGNAL ;
    PORT
      LAYER Metal2 ;
        RECT 879.6650 0.0000 879.7350 0.2900 ;
    END
  END ataslavein_0
  PIN ataslavein_1
    DIRECTION INPUT ;
    USE SIGNAL ;
    PORT
      LAYER Metal2 ;
        RECT 871.4650 0.0000 871.5350 0.2900 ;
    END
  END ataslavein_1
  PIN ataslavein_2
    DIRECTION INPUT ;
    USE SIGNAL ;
    PORT
      LAYER Metal2 ;
        RECT 864.8650 0.0000 864.9350 0.2900 ;
    END
  END ataslavein_2
  PIN ataslavein_3
    DIRECTION INPUT ;
    USE SIGNAL ;
    PORT
      LAYER Metal2 ;
        RECT 858.6650 0.0000 858.7350 0.2900 ;
    END
  END ataslavein_3
  PIN ataslavein_4
    DIRECTION INPUT ;
    USE SIGNAL ;
    PORT
      LAYER Metal2 ;
        RECT 860.8650 0.0000 860.9350 0.2900 ;
    END
  END ataslavein_4
  PIN ataslavein_5
    DIRECTION INPUT ;
    USE SIGNAL ;
    PORT
      LAYER Metal4 ;
        RECT 858.8650 0.0000 858.9350 0.2900 ;
    END
  END ataslavein_5
  PIN ataslavein_6
    DIRECTION INPUT ;
    USE SIGNAL ;
    PORT
      LAYER Metal3 ;
        RECT 1112.1100 23.8100 1112.4000 23.8800 ;
    END
  END ataslavein_6
  PIN ataslavein_7
    DIRECTION INPUT ;
    USE SIGNAL ;
    PORT
      LAYER Metal2 ;
        RECT 863.6650 0.0000 863.7350 0.2900 ;
    END
  END ataslavein_7
  PIN ataslavein_8
    DIRECTION INPUT ;
    USE SIGNAL ;
    PORT
      LAYER Metal5 ;
        RECT 1112.1100 5.5700 1112.4000 5.6400 ;
    END
  END ataslavein_8
  PIN ataslavein_9
    DIRECTION INPUT ;
    USE SIGNAL ;
    PORT
      LAYER Metal2 ;
        RECT 853.8650 0.0000 853.9350 0.2900 ;
    END
  END ataslavein_9
  PIN ataslavein_10
    DIRECTION INPUT ;
    USE SIGNAL ;
    PORT
      LAYER Metal2 ;
        RECT 856.8650 0.0000 856.9350 0.2900 ;
    END
  END ataslavein_10
  PIN ataslavein_11
    DIRECTION INPUT ;
    USE SIGNAL ;
    PORT
      LAYER Metal2 ;
        RECT 861.6650 0.0000 861.7350 0.2900 ;
    END
  END ataslavein_11
  PIN ataslavein_12
    DIRECTION INPUT ;
    USE SIGNAL ;
    PORT
      LAYER Metal3 ;
        RECT 1112.1100 5.1900 1112.4000 5.2600 ;
    END
  END ataslavein_12
  PIN ataslavein_13
    DIRECTION INPUT ;
    USE SIGNAL ;
    PORT
      LAYER Metal4 ;
        RECT 861.8650 0.0000 861.9350 0.2900 ;
    END
  END ataslavein_13
  PIN ataslavein_14
    DIRECTION INPUT ;
    USE SIGNAL ;
    PORT
      LAYER Metal2 ;
        RECT 880.8650 0.0000 880.9350 0.2900 ;
    END
  END ataslavein_14
  PIN ataslavein_15
    DIRECTION INPUT ;
    USE SIGNAL ;
    PORT
      LAYER Metal2 ;
        RECT 881.8650 0.0000 881.9350 0.2900 ;
    END
  END ataslavein_15
  PIN ataslavein_16
    DIRECTION INPUT ;
    USE SIGNAL ;
    PORT
      LAYER Metal2 ;
        RECT 974.2650 0.0000 974.3350 0.2900 ;
    END
  END ataslavein_16
  PIN ataslavein_17
    DIRECTION INPUT ;
    USE SIGNAL ;
    PORT
      LAYER Metal2 ;
        RECT 901.8650 0.0000 901.9350 0.2900 ;
    END
  END ataslavein_17
  PIN ataslavein_18
    DIRECTION INPUT ;
    USE SIGNAL ;
    PORT
      LAYER Metal2 ;
        RECT 903.8650 0.0000 903.9350 0.2900 ;
    END
  END ataslavein_18
  PIN ataslavein_19
    DIRECTION INPUT ;
    USE SIGNAL ;
    PORT
      LAYER Metal2 ;
        RECT 903.4650 0.0000 903.5350 0.2900 ;
    END
  END ataslavein_19
  PIN ataslavein_20
    DIRECTION INPUT ;
    USE SIGNAL ;
    PORT
      LAYER Metal2 ;
        RECT 904.6650 0.0000 904.7350 0.2900 ;
    END
  END ataslavein_20
  PIN ataslavein_21
    DIRECTION INPUT ;
    USE SIGNAL ;
    PORT
      LAYER Metal3 ;
        RECT 1112.1100 14.6900 1112.4000 14.7600 ;
    END
  END ataslavein_21
  PIN ataslavein_22
    DIRECTION INPUT ;
    USE SIGNAL ;
    PORT
      LAYER Metal2 ;
        RECT 905.6650 0.0000 905.7350 0.2900 ;
    END
  END ataslavein_22
  PIN ataslavein_23
    DIRECTION INPUT ;
    USE SIGNAL ;
    PORT
      LAYER Metal2 ;
        RECT 906.8650 0.0000 906.9350 0.2900 ;
    END
  END ataslavein_23
  PIN ataslavein_24
    DIRECTION INPUT ;
    USE SIGNAL ;
    PORT
      LAYER Metal4 ;
        RECT 904.8650 0.0000 904.9350 0.2900 ;
    END
  END ataslavein_24
  PIN ataslavein_25
    DIRECTION INPUT ;
    USE SIGNAL ;
    PORT
      LAYER Metal3 ;
        RECT 1112.1100 20.7700 1112.4000 20.8400 ;
    END
  END ataslavein_25
  PIN ataslavein_26
    DIRECTION INPUT ;
    USE SIGNAL ;
    PORT
      LAYER Metal3 ;
        RECT 1112.1100 24.1900 1112.4000 24.2600 ;
    END
  END ataslavein_26
  PIN ataslavein_27
    DIRECTION INPUT ;
    USE SIGNAL ;
    PORT
      LAYER Metal2 ;
        RECT 938.4650 0.0000 938.5350 0.2900 ;
    END
  END ataslavein_27
  PIN ataslavein_28
    DIRECTION INPUT ;
    USE SIGNAL ;
    PORT
      LAYER Metal2 ;
        RECT 928.4650 0.0000 928.5350 0.2900 ;
    END
  END ataslavein_28
  PIN ataslavein_29
    DIRECTION INPUT ;
    USE SIGNAL ;
    PORT
      LAYER Metal2 ;
        RECT 913.2650 0.0000 913.3350 0.2900 ;
    END
  END ataslavein_29
  PIN ataslavein_30
    DIRECTION INPUT ;
    USE SIGNAL ;
    PORT
      LAYER Metal2 ;
        RECT 906.4650 0.0000 906.5350 0.2900 ;
    END
  END ataslavein_30
  PIN ataslavein_31
    DIRECTION INPUT ;
    USE SIGNAL ;
    PORT
      LAYER Metal2 ;
        RECT 945.4650 0.0000 945.5350 0.2900 ;
    END
  END ataslavein_31
  PIN ataslavein_34
    DIRECTION INPUT ;
    USE SIGNAL ;
    PORT
      LAYER Metal2 ;
        RECT 1046.0650 0.0000 1046.1350 0.2900 ;
    END
  END ataslavein_34
  PIN ataslavein_35
    DIRECTION INPUT ;
    USE SIGNAL ;
    PORT
      LAYER Metal2 ;
        RECT 1047.6650 0.0000 1047.7350 0.2900 ;
    END
  END ataslavein_35
  PIN ataslavein_36
    DIRECTION INPUT ;
    USE SIGNAL ;
    PORT
      LAYER Metal3 ;
        RECT 1112.1100 7.6600 1112.4000 7.7300 ;
    END
  END ataslavein_36
  PIN ataslavein_37
    DIRECTION INPUT ;
    USE SIGNAL ;
    PORT
      LAYER Metal3 ;
        RECT 1112.1100 9.3700 1112.4000 9.4400 ;
    END
  END ataslavein_37
  PIN ataslavein_38
    DIRECTION INPUT ;
    USE SIGNAL ;
    PORT
      LAYER Metal2 ;
        RECT 1047.0650 0.0000 1047.1350 0.2900 ;
    END
  END ataslavein_38
  PIN ataslavein_76
    DIRECTION INPUT ;
    USE SIGNAL ;
    PORT
      LAYER Metal3 ;
        RECT 1112.1100 5.5700 1112.4000 5.6400 ;
    END
  END ataslavein_76
  PIN ataslavein_77
    DIRECTION INPUT ;
    USE SIGNAL ;
    PORT
      LAYER Metal2 ;
        RECT 1097.8650 0.0000 1097.9350 0.2900 ;
    END
  END ataslavein_77
  PIN ataslavein_78
    DIRECTION INPUT ;
    USE SIGNAL ;
    PORT
      LAYER Metal4 ;
        RECT 1098.0650 0.0000 1098.1350 0.2900 ;
    END
  END ataslavein_78
  PIN ataslavein_79
    DIRECTION INPUT ;
    USE SIGNAL ;
    PORT
      LAYER Metal2 ;
        RECT 1042.2650 0.0000 1042.3350 0.2900 ;
    END
  END ataslavein_79
  PIN ataslavein_80
    DIRECTION INPUT ;
    USE SIGNAL ;
    PORT
      LAYER Metal3 ;
        RECT 1112.1100 5.9500 1112.4000 6.0200 ;
    END
  END ataslavein_80
  PIN ataslavein_81
    DIRECTION INPUT ;
    USE SIGNAL ;
    PORT
      LAYER Metal3 ;
        RECT 1112.1100 11.2700 1112.4000 11.3400 ;
    END
  END ataslavein_81
  PIN ataslavein_82
    DIRECTION INPUT ;
    USE SIGNAL ;
    PORT
      LAYER Metal2 ;
        RECT 1034.0650 0.0000 1034.1350 0.2900 ;
    END
  END ataslavein_82
  PIN ataslavein_83
    DIRECTION INPUT ;
    USE SIGNAL ;
    PORT
      LAYER Metal4 ;
        RECT 1047.2650 0.0000 1047.3350 0.2900 ;
    END
  END ataslavein_83
  PIN uart_rxd_2core
    DIRECTION INPUT ;
    USE SIGNAL ;
    PORT
      LAYER Metal8 ;
        RECT 1107.2650 0.0000 1107.3350 0.2900 ;
    END
  END uart_rxd_2core
  PIN n_28010
    DIRECTION OUTPUT ;
    USE SIGNAL ;
    PORT
      LAYER Metal4 ;
        RECT 1109.0650 0.0000 1109.1350 0.2900 ;
    END
  END n_28010
  PIN n_27992
    DIRECTION OUTPUT ;
    USE SIGNAL ;
    PORT
      LAYER Metal3 ;
        RECT 1112.1100 1695.4300 1112.4000 1695.5000 ;
    END
  END n_27992
  PIN n_27782
    DIRECTION OUTPUT ;
    USE SIGNAL ;
    PORT
      LAYER Metal5 ;
        RECT 1112.1100 1676.6200 1112.4000 1676.6900 ;
    END
  END n_27782
  PIN n_27348
    DIRECTION OUTPUT ;
    USE SIGNAL ;
    PORT
      LAYER Metal3 ;
        RECT 1112.1100 1658.0000 1112.4000 1658.0700 ;
    END
  END n_27348
  PIN n_27258
    DIRECTION OUTPUT ;
    USE SIGNAL ;
    PORT
      LAYER Metal3 ;
        RECT 1112.1100 1652.6800 1112.4000 1652.7500 ;
    END
  END n_27258
  PIN n_27091
    DIRECTION OUTPUT ;
    USE SIGNAL ;
    PORT
      LAYER Metal3 ;
        RECT 1112.1100 1642.4200 1112.4000 1642.4900 ;
    END
  END n_27091
  PIN n_26809
    DIRECTION OUTPUT ;
    USE SIGNAL ;
    PORT
      LAYER Metal3 ;
        RECT 1112.1100 1148.2300 1112.4000 1148.3000 ;
    END
  END n_26809
  PIN n_26803
    DIRECTION OUTPUT ;
    USE SIGNAL ;
    PORT
      LAYER Metal3 ;
        RECT 1112.1100 1288.4500 1112.4000 1288.5200 ;
    END
  END n_26803
  PIN vid_blank_2pad
    DIRECTION OUTPUT ;
    USE SIGNAL ;
    PORT
      LAYER Metal8 ;
        RECT 1104.0650 0.0000 1104.1350 0.2900 ;
    END
  END vid_blank_2pad
  PIN vid_csync_2pad
    DIRECTION OUTPUT ;
    USE SIGNAL ;
    PORT
      LAYER Metal9 ;
        RECT 1112.1100 1613.3500 1112.4000 1613.4200 ;
    END
  END vid_csync_2pad
  PIN vid_vsync_2pad
    DIRECTION OUTPUT ;
    USE SIGNAL ;
    PORT
      LAYER Metal5 ;
        RECT 1112.1100 1613.5400 1112.4000 1613.6100 ;
    END
  END vid_vsync_2pad
  PIN n_28400
    DIRECTION OUTPUT ;
    USE SIGNAL ;
    PORT
      LAYER Metal7 ;
        RECT 1112.1100 1613.5400 1112.4000 1613.6100 ;
    END
  END n_28400
  PIN vid_pclk_2core
    DIRECTION INPUT ;
    USE SIGNAL ;
    PORT
      LAYER Metal3 ;
        RECT 1112.1100 1617.1500 1112.4000 1617.2200 ;
    END
  END vid_pclk_2core
  PIN vid_ack_2core
    DIRECTION INPUT ;
    USE SIGNAL ;
    PORT
      LAYER Metal2 ;
        RECT 1068.4650 0.0000 1068.5350 0.2900 ;
    END
  END vid_ack_2core
  PIN n_26775
    DIRECTION OUTPUT ;
    USE SIGNAL ;
    PORT
      LAYER Metal5 ;
        RECT 1112.1100 1197.6300 1112.4000 1197.7000 ;
    END
  END n_26775
  PIN n_26802
    DIRECTION OUTPUT ;
    USE SIGNAL ;
    PORT
      LAYER Metal5 ;
        RECT 1112.1100 1288.6400 1112.4000 1288.7100 ;
    END
  END n_26802
  PIN n_26796
    DIRECTION OUTPUT ;
    USE SIGNAL ;
    PORT
      LAYER Metal3 ;
        RECT 1112.1100 1818.7400 1112.4000 1818.8100 ;
    END
  END n_26796
  PIN n_28140
    DIRECTION OUTPUT ;
    USE SIGNAL ;
    PORT
      LAYER Metal5 ;
        RECT 1112.1100 1703.7900 1112.4000 1703.8600 ;
    END
  END n_28140
  PIN n_28056
    DIRECTION OUTPUT ;
    USE SIGNAL ;
    PORT
      LAYER Metal3 ;
        RECT 1112.1100 1714.0500 1112.4000 1714.1200 ;
    END
  END n_28056
  PIN n_28049
    DIRECTION OUTPUT ;
    USE SIGNAL ;
    PORT
      LAYER Metal3 ;
        RECT 1112.1100 1705.8800 1112.4000 1705.9500 ;
    END
  END n_28049
  PIN n_28017
    DIRECTION OUTPUT ;
    USE SIGNAL ;
    PORT
      LAYER Metal5 ;
        RECT 1112.1100 1693.5300 1112.4000 1693.6000 ;
    END
  END n_28017
  PIN n_28011
    DIRECTION OUTPUT ;
    USE SIGNAL ;
    PORT
      LAYER Metal3 ;
        RECT 1112.1100 1700.5600 1112.4000 1700.6300 ;
    END
  END n_28011
  PIN n_27991
    DIRECTION OUTPUT ;
    USE SIGNAL ;
    PORT
      LAYER Metal5 ;
        RECT 1112.1100 1695.6200 1112.4000 1695.6900 ;
    END
  END n_27991
  PIN n_27985
    DIRECTION OUTPUT ;
    USE SIGNAL ;
    PORT
      LAYER Metal3 ;
        RECT 1112.1100 1685.3600 1112.4000 1685.4300 ;
    END
  END n_27985
  PIN n_27895
    DIRECTION OUTPUT ;
    USE SIGNAL ;
    PORT
      LAYER Metal5 ;
        RECT 1112.1100 1681.9400 1112.4000 1682.0100 ;
    END
  END n_27895
  PIN n_27822
    DIRECTION OUTPUT ;
    USE SIGNAL ;
    PORT
      LAYER Metal5 ;
        RECT 1112.1100 1683.4600 1112.4000 1683.5300 ;
    END
  END n_27822
  PIN n_27799
    DIRECTION OUTPUT ;
    USE SIGNAL ;
    PORT
      LAYER Metal3 ;
        RECT 1112.1100 1725.2600 1112.4000 1725.3300 ;
    END
  END n_27799
  PIN n_27788
    DIRECTION OUTPUT ;
    USE SIGNAL ;
    PORT
      LAYER Metal5 ;
        RECT 1112.1100 1716.1400 1112.4000 1716.2100 ;
    END
  END n_27788
  PIN n_27781
    DIRECTION OUTPUT ;
    USE SIGNAL ;
    PORT
      LAYER Metal3 ;
        RECT 1112.1100 1676.4300 1112.4000 1676.5000 ;
    END
  END n_27781
  PIN n_27775
    DIRECTION OUTPUT ;
    USE SIGNAL ;
    PORT
      LAYER Metal3 ;
        RECT 1112.1100 1669.5900 1112.4000 1669.6600 ;
    END
  END n_27775
  PIN n_27347
    DIRECTION OUTPUT ;
    USE SIGNAL ;
    PORT
      LAYER Metal5 ;
        RECT 1112.1100 1658.0000 1112.4000 1658.0700 ;
    END
  END n_27347
  PIN n_27341
    DIRECTION OUTPUT ;
    USE SIGNAL ;
    PORT
      LAYER Metal7 ;
        RECT 1112.1100 1658.2850 1112.4000 1658.3550 ;
    END
  END n_27341
  PIN n_27257
    DIRECTION OUTPUT ;
    USE SIGNAL ;
    PORT
      LAYER Metal5 ;
        RECT 1112.1100 1652.4900 1112.4000 1652.5600 ;
    END
  END n_27257
  PIN n_27251
    DIRECTION OUTPUT ;
    USE SIGNAL ;
    PORT
      LAYER Metal5 ;
        RECT 1112.1100 1649.0700 1112.4000 1649.1400 ;
    END
  END n_27251
  PIN n_27090
    DIRECTION OUTPUT ;
    USE SIGNAL ;
    PORT
      LAYER Metal5 ;
        RECT 1112.1100 1642.2300 1112.4000 1642.3000 ;
    END
  END n_27090
  PIN n_27084
    DIRECTION OUTPUT ;
    USE SIGNAL ;
    PORT
      LAYER Metal5 ;
        RECT 1112.1100 845.3700 1112.4000 845.4400 ;
    END
  END n_27084
  PIN n_26808
    DIRECTION OUTPUT ;
    USE SIGNAL ;
    PORT
      LAYER Metal5 ;
        RECT 1112.1100 1148.4200 1112.4000 1148.4900 ;
    END
  END n_26808
  PIN n_20015
    DIRECTION INPUT ;
    USE SIGNAL ;
    PORT
      LAYER Metal5 ;
        RECT 1112.1100 1.7700 1112.4000 1.8400 ;
    END
  END n_20015
  PIN vgaslaveout_0
    DIRECTION OUTPUT ;
    USE SIGNAL ;
    PORT
      LAYER Metal6 ;
        RECT 1109.2650 0.0000 1109.3350 0.2900 ;
    END
  END vgaslaveout_0
  PIN vgaslaveout_1
    DIRECTION OUTPUT ;
    USE SIGNAL ;
    PORT
      LAYER Metal3 ;
        RECT 1112.1100 202.4100 1112.4000 202.4800 ;
    END
  END vgaslaveout_1
  PIN vgaslaveout_2
    DIRECTION OUTPUT ;
    USE SIGNAL ;
    PORT
      LAYER Metal6 ;
        RECT 1093.0650 0.0000 1093.1350 0.2900 ;
    END
  END vgaslaveout_2
  PIN vgaslaveout_3
    DIRECTION OUTPUT ;
    USE SIGNAL ;
    PORT
      LAYER Metal2 ;
        RECT 1087.8650 0.0000 1087.9350 0.2900 ;
    END
  END vgaslaveout_3
  PIN vgaslaveout_4
    DIRECTION OUTPUT ;
    USE SIGNAL ;
    PORT
      LAYER Metal6 ;
        RECT 1088.4650 0.0000 1088.5350 0.2900 ;
    END
  END vgaslaveout_4
  PIN vgaslaveout_5
    DIRECTION OUTPUT ;
    USE SIGNAL ;
    PORT
      LAYER Metal2 ;
        RECT 1085.4650 0.0000 1085.5350 0.2900 ;
    END
  END vgaslaveout_5
  PIN vgaslaveout_6
    DIRECTION OUTPUT ;
    USE SIGNAL ;
    PORT
      LAYER Metal2 ;
        RECT 1086.4650 0.0000 1086.5350 0.2900 ;
    END
  END vgaslaveout_6
  PIN vgaslaveout_7
    DIRECTION OUTPUT ;
    USE SIGNAL ;
    PORT
      LAYER Metal2 ;
        RECT 1082.8650 0.0000 1082.9350 0.2900 ;
    END
  END vgaslaveout_7
  PIN vgaslaveout_8
    DIRECTION OUTPUT ;
    USE SIGNAL ;
    PORT
      LAYER Metal2 ;
        RECT 1089.8650 0.0000 1089.9350 0.2900 ;
    END
  END vgaslaveout_8
  PIN vgaslaveout_9
    DIRECTION OUTPUT ;
    USE SIGNAL ;
    PORT
      LAYER Metal2 ;
        RECT 1084.8650 0.0000 1084.9350 0.2900 ;
    END
  END vgaslaveout_9
  PIN vgaslaveout_10
    DIRECTION OUTPUT ;
    USE SIGNAL ;
    PORT
      LAYER Metal2 ;
        RECT 1079.4650 0.0000 1079.5350 0.2900 ;
    END
  END vgaslaveout_10
  PIN vgaslaveout_11
    DIRECTION OUTPUT ;
    USE SIGNAL ;
    PORT
      LAYER Metal4 ;
        RECT 1079.2650 0.0000 1079.3350 0.2900 ;
    END
  END vgaslaveout_11
  PIN vgaslaveout_12
    DIRECTION OUTPUT ;
    USE SIGNAL ;
    PORT
      LAYER Metal8 ;
        RECT 1092.8650 0.0000 1092.9350 0.2900 ;
    END
  END vgaslaveout_12
  PIN vgaslaveout_13
    DIRECTION OUTPUT ;
    USE SIGNAL ;
    PORT
      LAYER Metal8 ;
        RECT 1092.4650 0.0000 1092.5350 0.2900 ;
    END
  END vgaslaveout_13
  PIN vgaslaveout_14
    DIRECTION OUTPUT ;
    USE SIGNAL ;
    PORT
      LAYER Metal3 ;
        RECT 1112.1100 196.7100 1112.4000 196.7800 ;
    END
  END vgaslaveout_14
  PIN vgaslaveout_15
    DIRECTION OUTPUT ;
    USE SIGNAL ;
    PORT
      LAYER Metal4 ;
        RECT 1091.2650 0.0000 1091.3350 0.2900 ;
    END
  END vgaslaveout_15
  PIN vgaslaveout_16
    DIRECTION OUTPUT ;
    USE SIGNAL ;
    PORT
      LAYER Metal4 ;
        RECT 1085.6650 0.0000 1085.7350 0.2900 ;
    END
  END vgaslaveout_16
  PIN vgaslaveout_17
    DIRECTION OUTPUT ;
    USE SIGNAL ;
    PORT
      LAYER Metal4 ;
        RECT 1083.2650 0.0000 1083.3350 0.2900 ;
    END
  END vgaslaveout_17
  PIN vgaslaveout_18
    DIRECTION OUTPUT ;
    USE SIGNAL ;
    PORT
      LAYER Metal4 ;
        RECT 1083.6650 0.0000 1083.7350 0.2900 ;
    END
  END vgaslaveout_18
  PIN vgaslaveout_19
    DIRECTION OUTPUT ;
    USE SIGNAL ;
    PORT
      LAYER Metal3 ;
        RECT 1112.1100 213.8100 1112.4000 213.8800 ;
    END
  END vgaslaveout_19
  PIN vgaslaveout_20
    DIRECTION OUTPUT ;
    USE SIGNAL ;
    PORT
      LAYER Metal4 ;
        RECT 1079.6650 0.0000 1079.7350 0.2900 ;
    END
  END vgaslaveout_20
  PIN vgaslaveout_21
    DIRECTION OUTPUT ;
    USE SIGNAL ;
    PORT
      LAYER Metal4 ;
        RECT 1089.6650 0.0000 1089.7350 0.2900 ;
    END
  END vgaslaveout_21
  PIN vgaslaveout_22
    DIRECTION OUTPUT ;
    USE SIGNAL ;
    PORT
      LAYER Metal6 ;
        RECT 1090.6650 0.0000 1090.7350 0.2900 ;
    END
  END vgaslaveout_22
  PIN vgaslaveout_23
    DIRECTION OUTPUT ;
    USE SIGNAL ;
    PORT
      LAYER Metal6 ;
        RECT 1091.0650 0.0000 1091.1350 0.2900 ;
    END
  END vgaslaveout_23
  PIN vgaslaveout_24
    DIRECTION OUTPUT ;
    USE SIGNAL ;
    PORT
      LAYER Metal8 ;
        RECT 1091.0650 0.0000 1091.1350 0.2900 ;
    END
  END vgaslaveout_24
  PIN vgaslaveout_25
    DIRECTION OUTPUT ;
    USE SIGNAL ;
    PORT
      LAYER Metal3 ;
        RECT 1112.1100 212.2900 1112.4000 212.3600 ;
    END
  END vgaslaveout_25
  PIN vgaslaveout_26
    DIRECTION OUTPUT ;
    USE SIGNAL ;
    PORT
      LAYER Metal4 ;
        RECT 1090.8650 0.0000 1090.9350 0.2900 ;
    END
  END vgaslaveout_26
  PIN vgaslaveout_27
    DIRECTION OUTPUT ;
    USE SIGNAL ;
    PORT
      LAYER Metal3 ;
        RECT 1112.1100 220.6500 1112.4000 220.7200 ;
    END
  END vgaslaveout_27
  PIN vgaslaveout_28
    DIRECTION OUTPUT ;
    USE SIGNAL ;
    PORT
      LAYER Metal3 ;
        RECT 1112.1100 222.5500 1112.4000 222.6200 ;
    END
  END vgaslaveout_28
  PIN vgaslaveout_29
    DIRECTION OUTPUT ;
    USE SIGNAL ;
    PORT
      LAYER Metal8 ;
        RECT 1090.6650 0.0000 1090.7350 0.2900 ;
    END
  END vgaslaveout_29
  PIN vgaslaveout_30
    DIRECTION OUTPUT ;
    USE SIGNAL ;
    PORT
      LAYER Metal6 ;
        RECT 1090.2650 0.0000 1090.3350 0.2900 ;
    END
  END vgaslaveout_30
  PIN vgaslaveout_31
    DIRECTION OUTPUT ;
    USE SIGNAL ;
    PORT
      LAYER Metal8 ;
        RECT 1090.2650 0.0000 1090.3350 0.2900 ;
    END
  END vgaslaveout_31
  PIN vgaslaveout_32
    DIRECTION OUTPUT ;
    USE SIGNAL ;
    PORT
      LAYER Metal5 ;
        RECT 0.0000 1592.0700 0.2900 1592.1400 ;
    END
  END vgaslaveout_32
  PIN vgaslaveout_33
    DIRECTION OUTPUT ;
    USE SIGNAL ;
    PORT
      LAYER Metal9 ;
        RECT 0.0000 1579.9100 0.2900 1579.9800 ;
    END
  END vgaslaveout_33
  PIN vgaslaveout_34
    DIRECTION OUTPUT ;
    USE SIGNAL ;
    PORT
      LAYER Metal9 ;
        RECT 0.0000 1592.0700 0.2900 1592.1400 ;
    END
  END vgaslaveout_34
  PIN vgaslaveout_35
    DIRECTION OUTPUT ;
    USE SIGNAL ;
    PORT
      LAYER Metal7 ;
        RECT 0.0000 1592.1650 0.2900 1592.2350 ;
    END
  END vgaslaveout_35
  PIN vgaslaveout_36
    DIRECTION OUTPUT ;
    USE SIGNAL ;
    PORT
      LAYER Metal7 ;
        RECT 0.0000 1579.6250 0.2900 1579.6950 ;
    END
  END vgaslaveout_36
  PIN vgaslaveout_37
    DIRECTION OUTPUT ;
    USE SIGNAL ;
    PORT
      LAYER Metal7 ;
        RECT 0.0000 1592.7350 0.2900 1592.8050 ;
    END
  END vgaslaveout_37
  PIN vgaslaveout_38
    DIRECTION OUTPUT ;
    USE SIGNAL ;
    PORT
      LAYER Metal9 ;
        RECT 0.0000 1579.1500 0.2900 1579.2200 ;
    END
  END vgaslaveout_38
  PIN vgaslaveout_39
    DIRECTION OUTPUT ;
    USE SIGNAL ;
    PORT
      LAYER Metal9 ;
        RECT 0.0000 1592.8300 0.2900 1592.9000 ;
    END
  END vgaslaveout_39
  PIN vgaslaveout_40
    DIRECTION OUTPUT ;
    USE SIGNAL ;
    PORT
      LAYER Metal7 ;
        RECT 0.0000 1579.0550 0.2900 1579.1250 ;
    END
  END vgaslaveout_40
  PIN vgaslaveout_41
    DIRECTION OUTPUT ;
    USE SIGNAL ;
    PORT
      LAYER Metal3 ;
        RECT 0.0000 1578.9600 0.2900 1579.0300 ;
    END
  END vgaslaveout_41
  PIN vgaslaveout_42
    DIRECTION OUTPUT ;
    USE SIGNAL ;
    PORT
      LAYER Metal5 ;
        RECT 0.0000 1578.9600 0.2900 1579.0300 ;
    END
  END vgaslaveout_42
  PIN vgaslaveout_43
    DIRECTION OUTPUT ;
    USE SIGNAL ;
    PORT
      LAYER Metal7 ;
        RECT 0.0000 1593.3050 0.2900 1593.3750 ;
    END
  END vgaslaveout_43
  PIN vgaslaveout_44
    DIRECTION OUTPUT ;
    USE SIGNAL ;
    PORT
      LAYER Metal7 ;
        RECT 0.0000 1578.4850 0.2900 1578.5550 ;
    END
  END vgaslaveout_44
  PIN vgaslaveout_45
    DIRECTION OUTPUT ;
    USE SIGNAL ;
    PORT
      LAYER Metal9 ;
        RECT 0.0000 1578.3900 0.2900 1578.4600 ;
    END
  END vgaslaveout_45
  PIN vgaslaveout_46
    DIRECTION OUTPUT ;
    USE SIGNAL ;
    PORT
      LAYER Metal7 ;
        RECT 0.0000 1593.8750 0.2900 1593.9450 ;
    END
  END vgaslaveout_46
  PIN vgaslaveout_47
    DIRECTION OUTPUT ;
    USE SIGNAL ;
    PORT
      LAYER Metal3 ;
        RECT 0.0000 1593.9700 0.2900 1594.0400 ;
    END
  END vgaslaveout_47
  PIN vgaslaveout_48
    DIRECTION OUTPUT ;
    USE SIGNAL ;
    PORT
      LAYER Metal8 ;
        RECT 1109.2650 0.0000 1109.3350 0.2900 ;
    END
  END vgaslaveout_48
  PIN vgaslaveout_50
    DIRECTION OUTPUT ;
    USE SIGNAL ;
    PORT
      LAYER Metal3 ;
        RECT 1112.1100 165.1700 1112.4000 165.2400 ;
    END
  END vgaslaveout_50
  PIN vgaslavein_0
    DIRECTION INPUT ;
    USE SIGNAL ;
    PORT
      LAYER Metal6 ;
        RECT 1101.0650 0.0000 1101.1350 0.2900 ;
    END
  END vgaslavein_0
  PIN vgaslavein_1
    DIRECTION INPUT ;
    USE SIGNAL ;
    PORT
      LAYER Metal3 ;
        RECT 1112.1100 233.5700 1112.4000 233.6400 ;
    END
  END vgaslavein_1
  PIN vgaslavein_2
    DIRECTION INPUT ;
    USE SIGNAL ;
    PORT
      LAYER Metal8 ;
        RECT 1098.6650 0.0000 1098.7350 0.2900 ;
    END
  END vgaslavein_2
  PIN vgaslavein_3
    DIRECTION INPUT ;
    USE SIGNAL ;
    PORT
      LAYER Metal4 ;
        RECT 1100.0650 0.0000 1100.1350 0.2900 ;
    END
  END vgaslavein_3
  PIN vgaslavein_4
    DIRECTION INPUT ;
    USE SIGNAL ;
    PORT
      LAYER Metal2 ;
        RECT 1089.4650 0.0000 1089.5350 0.2900 ;
    END
  END vgaslavein_4
  PIN vgaslavein_5
    DIRECTION INPUT ;
    USE SIGNAL ;
    PORT
      LAYER Metal6 ;
        RECT 1089.2650 0.0000 1089.3350 0.2900 ;
    END
  END vgaslavein_5
  PIN vgaslavein_6
    DIRECTION INPUT ;
    USE SIGNAL ;
    PORT
      LAYER Metal4 ;
        RECT 1092.2650 0.0000 1092.3350 0.2900 ;
    END
  END vgaslavein_6
  PIN vgaslavein_7
    DIRECTION INPUT ;
    USE SIGNAL ;
    PORT
      LAYER Metal3 ;
        RECT 1112.1100 677.7900 1112.4000 677.8600 ;
    END
  END vgaslavein_7
  PIN vgaslavein_8
    DIRECTION INPUT ;
    USE SIGNAL ;
    PORT
      LAYER Metal2 ;
        RECT 1096.4650 0.0000 1096.5350 0.2900 ;
    END
  END vgaslavein_8
  PIN vgaslavein_9
    DIRECTION INPUT ;
    USE SIGNAL ;
    PORT
      LAYER Metal2 ;
        RECT 1097.4650 0.0000 1097.5350 0.2900 ;
    END
  END vgaslavein_9
  PIN vgaslavein_10
    DIRECTION INPUT ;
    USE SIGNAL ;
    PORT
      LAYER Metal6 ;
        RECT 1098.2650 0.0000 1098.3350 0.2900 ;
    END
  END vgaslavein_10
  PIN vgaslavein_11
    DIRECTION INPUT ;
    USE SIGNAL ;
    PORT
      LAYER Metal4 ;
        RECT 1100.4650 0.0000 1100.5350 0.2900 ;
    END
  END vgaslavein_11
  PIN vgaslavein_12
    DIRECTION INPUT ;
    USE SIGNAL ;
    PORT
      LAYER Metal4 ;
        RECT 1105.6650 0.0000 1105.7350 0.2900 ;
    END
  END vgaslavein_12
  PIN vgaslavein_13
    DIRECTION INPUT ;
    USE SIGNAL ;
    PORT
      LAYER Metal4 ;
        RECT 1104.4650 0.0000 1104.5350 0.2900 ;
    END
  END vgaslavein_13
  PIN vgaslavein_14
    DIRECTION INPUT ;
    USE SIGNAL ;
    PORT
      LAYER Metal8 ;
        RECT 1103.2650 0.0000 1103.3350 0.2900 ;
    END
  END vgaslavein_14
  PIN vgaslavein_15
    DIRECTION INPUT ;
    USE SIGNAL ;
    PORT
      LAYER Metal2 ;
        RECT 1103.8650 0.0000 1103.9350 0.2900 ;
    END
  END vgaslavein_15
  PIN vgaslavein_16
    DIRECTION INPUT ;
    USE SIGNAL ;
    PORT
      LAYER Metal3 ;
        RECT 1112.1100 1409.2900 1112.4000 1409.3600 ;
    END
  END vgaslavein_16
  PIN vgaslavein_17
    DIRECTION INPUT ;
    USE SIGNAL ;
    PORT
      LAYER Metal3 ;
        RECT 1112.1100 234.7100 1112.4000 234.7800 ;
    END
  END vgaslavein_17
  PIN vgaslavein_18
    DIRECTION INPUT ;
    USE SIGNAL ;
    PORT
      LAYER Metal4 ;
        RECT 1104.8650 0.0000 1104.9350 0.2900 ;
    END
  END vgaslavein_18
  PIN vgaslavein_19
    DIRECTION INPUT ;
    USE SIGNAL ;
    PORT
      LAYER Metal6 ;
        RECT 1104.6650 0.0000 1104.7350 0.2900 ;
    END
  END vgaslavein_19
  PIN vgaslavein_20
    DIRECTION INPUT ;
    USE SIGNAL ;
    PORT
      LAYER Metal4 ;
        RECT 1104.0650 0.0000 1104.1350 0.2900 ;
    END
  END vgaslavein_20
  PIN vgaslavein_21
    DIRECTION INPUT ;
    USE SIGNAL ;
    PORT
      LAYER Metal3 ;
        RECT 1112.1100 583.9300 1112.4000 584.0000 ;
    END
  END vgaslavein_21
  PIN vgaslavein_22
    DIRECTION INPUT ;
    USE SIGNAL ;
    PORT
      LAYER Metal6 ;
        RECT 1105.4650 0.0000 1105.5350 0.2900 ;
    END
  END vgaslavein_22
  PIN vgaslavein_23
    DIRECTION INPUT ;
    USE SIGNAL ;
    PORT
      LAYER Metal2 ;
        RECT 1107.4650 0.0000 1107.5350 0.2900 ;
    END
  END vgaslavein_23
  PIN vgaslavein_24
    DIRECTION INPUT ;
    USE SIGNAL ;
    PORT
      LAYER Metal8 ;
        RECT 1106.8650 0.0000 1106.9350 0.2900 ;
    END
  END vgaslavein_24
  PIN vgaslavein_25
    DIRECTION INPUT ;
    USE SIGNAL ;
    PORT
      LAYER Metal6 ;
        RECT 1105.0650 0.0000 1105.1350 0.2900 ;
    END
  END vgaslavein_25
  PIN vgaslavein_26
    DIRECTION INPUT ;
    USE SIGNAL ;
    PORT
      LAYER Metal8 ;
        RECT 1105.2650 0.0000 1105.3350 0.2900 ;
    END
  END vgaslavein_26
  PIN vgaslavein_27
    DIRECTION INPUT ;
    USE SIGNAL ;
    PORT
      LAYER Metal3 ;
        RECT 1112.1100 233.1900 1112.4000 233.2600 ;
    END
  END vgaslavein_27
  PIN vgaslavein_28
    DIRECTION INPUT ;
    USE SIGNAL ;
    PORT
      LAYER Metal6 ;
        RECT 1106.4650 0.0000 1106.5350 0.2900 ;
    END
  END vgaslavein_28
  PIN vgaslavein_29
    DIRECTION INPUT ;
    USE SIGNAL ;
    PORT
      LAYER Metal6 ;
        RECT 1105.8650 0.0000 1105.9350 0.2900 ;
    END
  END vgaslavein_29
  PIN vgaslavein_30
    DIRECTION INPUT ;
    USE SIGNAL ;
    PORT
      LAYER Metal8 ;
        RECT 1106.4650 0.0000 1106.5350 0.2900 ;
    END
  END vgaslavein_30
  PIN vgaslavein_31
    DIRECTION INPUT ;
    USE SIGNAL ;
    PORT
      LAYER Metal8 ;
        RECT 1106.0650 0.0000 1106.1350 0.2900 ;
    END
  END vgaslavein_31
  PIN vgaslavein_34
    DIRECTION INPUT ;
    USE SIGNAL ;
    PORT
      LAYER Metal8 ;
        RECT 1105.6650 0.0000 1105.7350 0.2900 ;
    END
  END vgaslavein_34
  PIN vgaslavein_35
    DIRECTION INPUT ;
    USE SIGNAL ;
    PORT
      LAYER Metal2 ;
        RECT 1093.4650 0.0000 1093.5350 0.2900 ;
    END
  END vgaslavein_35
  PIN vgaslavein_36
    DIRECTION INPUT ;
    USE SIGNAL ;
    PORT
      LAYER Metal6 ;
        RECT 1088.8650 0.0000 1088.9350 0.2900 ;
    END
  END vgaslavein_36
  PIN vgaslavein_37
    DIRECTION INPUT ;
    USE SIGNAL ;
    PORT
      LAYER Metal2 ;
        RECT 1088.6650 0.0000 1088.7350 0.2900 ;
    END
  END vgaslavein_37
  PIN vgaslavein_38
    DIRECTION INPUT ;
    USE SIGNAL ;
    PORT
      LAYER Metal2 ;
        RECT 1092.0650 0.0000 1092.1350 0.2900 ;
    END
  END vgaslavein_38
  PIN vgaslavein_39
    DIRECTION INPUT ;
    USE SIGNAL ;
    PORT
      LAYER Metal2 ;
        RECT 1083.8650 0.0000 1083.9350 0.2900 ;
    END
  END vgaslavein_39
  PIN vgaslavein_40
    DIRECTION INPUT ;
    USE SIGNAL ;
    PORT
      LAYER Metal4 ;
        RECT 1088.6650 0.0000 1088.7350 0.2900 ;
    END
  END vgaslavein_40
  PIN vgaslavein_41
    DIRECTION INPUT ;
    USE SIGNAL ;
    PORT
      LAYER Metal2 ;
        RECT 1085.8650 0.0000 1085.9350 0.2900 ;
    END
  END vgaslavein_41
  PIN vgaslavein_42
    DIRECTION INPUT ;
    USE SIGNAL ;
    PORT
      LAYER Metal2 ;
        RECT 1092.6650 0.0000 1092.7350 0.2900 ;
    END
  END vgaslavein_42
  PIN vgaslavein_62
    DIRECTION INPUT ;
    USE SIGNAL ;
    PORT
      LAYER Metal6 ;
        RECT 1103.8650 0.0000 1103.9350 0.2900 ;
    END
  END vgaslavein_62
  PIN vgaslavein_63
    DIRECTION INPUT ;
    USE SIGNAL ;
    PORT
      LAYER Metal3 ;
        RECT 1112.1100 186.4500 1112.4000 186.5200 ;
    END
  END vgaslavein_63
  PIN vgaslavein_76
    DIRECTION INPUT ;
    USE SIGNAL ;
    PORT
      LAYER Metal8 ;
        RECT 1104.8650 0.0000 1104.9350 0.2900 ;
    END
  END vgaslavein_76
  PIN vgaslavein_77
    DIRECTION INPUT ;
    USE SIGNAL ;
    PORT
      LAYER Metal8 ;
        RECT 1102.8650 0.0000 1102.9350 0.2900 ;
    END
  END vgaslavein_77
  PIN vgaslavein_78
    DIRECTION INPUT ;
    USE SIGNAL ;
    PORT
      LAYER Metal8 ;
        RECT 1104.4650 0.0000 1104.5350 0.2900 ;
    END
  END vgaslavein_78
  PIN vgaslavein_79
    DIRECTION INPUT ;
    USE SIGNAL ;
    PORT
      LAYER Metal3 ;
        RECT 1112.1100 15.8300 1112.4000 15.9000 ;
    END
  END vgaslavein_79
  PIN vgaslavein_80
    DIRECTION INPUT ;
    USE SIGNAL ;
    PORT
      LAYER Metal5 ;
        RECT 1112.1100 15.6400 1112.4000 15.7100 ;
    END
  END vgaslavein_80
  PIN vgaslavein_81
    DIRECTION INPUT ;
    USE SIGNAL ;
    PORT
      LAYER Metal4 ;
        RECT 1107.0650 0.0000 1107.1350 0.2900 ;
    END
  END vgaslavein_81
  PIN vgaslavein_82
    DIRECTION INPUT ;
    USE SIGNAL ;
    PORT
      LAYER Metal6 ;
        RECT 1104.2650 0.0000 1104.3350 0.2900 ;
    END
  END vgaslavein_82
  PIN vgaslavein_83
    DIRECTION INPUT ;
    USE SIGNAL ;
    PORT
      LAYER Metal3 ;
        RECT 1112.1100 1.3900 1112.4000 1.4600 ;
    END
  END vgaslavein_83
  PIN n_28048
    DIRECTION OUTPUT ;
    USE SIGNAL ;
    PORT
      LAYER Metal3 ;
        RECT 1112.1100 518.3800 1112.4000 518.4500 ;
    END
  END n_28048
  PIN n_28018
    DIRECTION OUTPUT ;
    USE SIGNAL ;
    PORT
      LAYER Metal3 ;
        RECT 1112.1100 1693.7200 1112.4000 1693.7900 ;
    END
  END n_28018
  PIN n_27789
    DIRECTION OUTPUT ;
    USE SIGNAL ;
    PORT
      LAYER Metal3 ;
        RECT 1112.1100 1716.1400 1112.4000 1716.2100 ;
    END
  END n_27789
  PIN vid_err_2core
    DIRECTION INPUT ;
    USE SIGNAL ;
    PORT
      LAYER Metal4 ;
        RECT 1055.6650 0.0000 1055.7350 0.2900 ;
    END
  END vid_err_2core
  PIN scan_enable_2core
    DIRECTION INPUT ;
    USE SIGNAL ;
    PORT
      LAYER Metal9 ;
        RECT 0.0000 2833.1500 0.2900 2833.2200 ;
    END
  END scan_enable_2core
  PIN bist_start_2core
    DIRECTION INPUT ;
    USE SIGNAL ;
    PORT
      LAYER Metal4 ;
        RECT 808.6650 0.0000 808.7350 0.2900 ;
    END
  END bist_start_2core
  PIN bist_tsmd_2core
    DIRECTION INPUT ;
    USE SIGNAL ;
    PORT
      LAYER Metal2 ;
        RECT 1018.0650 0.0000 1018.1350 0.2900 ;
    END
  END bist_tsmd_2core
  PIN n_20014
    DIRECTION INPUT ;
    USE SIGNAL ;
    PORT
      LAYER Metal2 ;
        RECT 817.6650 0.0000 817.7350 0.2900 ;
    END
  END n_20014
  PIN ahbso_in_51
    DIRECTION OUTPUT ;
    USE SIGNAL ;
    PORT
      LAYER Metal5 ;
        RECT 0.0000 1593.9700 0.2900 1594.0400 ;
    END
  END ahbso_in_51
  PIN ahbso_in_52
    DIRECTION OUTPUT ;
    USE SIGNAL ;
    PORT
      LAYER Metal7 ;
        RECT 0.0000 1577.9150 0.2900 1577.9850 ;
    END
  END ahbso_in_52
  PIN ahbso_in_53
    DIRECTION OUTPUT ;
    USE SIGNAL ;
    PORT
      LAYER Metal9 ;
        RECT 0.0000 1577.6300 0.2900 1577.7000 ;
    END
  END ahbso_in_53
  PIN ahbso_in_54
    DIRECTION OUTPUT ;
    USE SIGNAL ;
    PORT
      LAYER Metal7 ;
        RECT 0.0000 1594.4450 0.2900 1594.5150 ;
    END
  END ahbso_in_54
  PIN ahbso_in_55
    DIRECTION OUTPUT ;
    USE SIGNAL ;
    PORT
      LAYER Metal7 ;
        RECT 0.0000 1577.3450 0.2900 1577.4150 ;
    END
  END ahbso_in_55
  PIN ahbso_in_56
    DIRECTION OUTPUT ;
    USE SIGNAL ;
    PORT
      LAYER Metal3 ;
        RECT 0.0000 1577.0600 0.2900 1577.1300 ;
    END
  END ahbso_in_56
  PIN ahbso_in_57
    DIRECTION OUTPUT ;
    USE SIGNAL ;
    PORT
      LAYER Metal5 ;
        RECT 0.0000 1577.0600 0.2900 1577.1300 ;
    END
  END ahbso_in_57
  PIN ahbso_in_58
    DIRECTION OUTPUT ;
    USE SIGNAL ;
    PORT
      LAYER Metal7 ;
        RECT 0.0000 1595.0150 0.2900 1595.0850 ;
    END
  END ahbso_in_58
  PIN ahbso_in_59
    DIRECTION OUTPUT ;
    USE SIGNAL ;
    PORT
      LAYER Metal9 ;
        RECT 0.0000 1576.8700 0.2900 1576.9400 ;
    END
  END ahbso_in_59
  PIN ahbso_in_60
    DIRECTION OUTPUT ;
    USE SIGNAL ;
    PORT
      LAYER Metal7 ;
        RECT 0.0000 1576.7750 0.2900 1576.8450 ;
    END
  END ahbso_in_60
  PIN ahbso_in_61
    DIRECTION OUTPUT ;
    USE SIGNAL ;
    PORT
      LAYER Metal7 ;
        RECT 0.0000 1595.5850 0.2900 1595.6550 ;
    END
  END ahbso_in_61
  PIN ahbso_in_62
    DIRECTION OUTPUT ;
    USE SIGNAL ;
    PORT
      LAYER Metal7 ;
        RECT 0.0000 1576.2050 0.2900 1576.2750 ;
    END
  END ahbso_in_62
  PIN ahbso_in_63
    DIRECTION OUTPUT ;
    USE SIGNAL ;
    PORT
      LAYER Metal3 ;
        RECT 0.0000 1595.8700 0.2900 1595.9400 ;
    END
  END ahbso_in_63
  PIN ahbso_in_64
    DIRECTION OUTPUT ;
    USE SIGNAL ;
    PORT
      LAYER Metal5 ;
        RECT 0.0000 1595.8700 0.2900 1595.9400 ;
    END
  END ahbso_in_64
  PIN ahbso_in_65
    DIRECTION OUTPUT ;
    USE SIGNAL ;
    PORT
      LAYER Metal9 ;
        RECT 0.0000 1576.1100 0.2900 1576.1800 ;
    END
  END ahbso_in_65
  PIN ahbso_in_66
    DIRECTION OUTPUT ;
    USE SIGNAL ;
    PORT
      LAYER Metal7 ;
        RECT 0.0000 1596.1550 0.2900 1596.2250 ;
    END
  END ahbso_in_66
  PIN ahbso_in_67
    DIRECTION OUTPUT ;
    USE SIGNAL ;
    PORT
      LAYER Metal3 ;
        RECT 1112.1100 1542.6700 1112.4000 1542.7400 ;
    END
  END ahbso_in_67
  PIN ahbso_in_68
    DIRECTION OUTPUT ;
    USE SIGNAL ;
    PORT
      LAYER Metal4 ;
        RECT 1107.4650 0.0000 1107.5350 0.2900 ;
    END
  END ahbso_in_68
  PIN ahbso_in_69
    DIRECTION OUTPUT ;
    USE SIGNAL ;
    PORT
      LAYER Metal2 ;
        RECT 947.6650 0.0000 947.7350 0.2900 ;
    END
  END ahbso_in_69
  PIN ahbso_in_70
    DIRECTION OUTPUT ;
    USE SIGNAL ;
    PORT
      LAYER Metal4 ;
        RECT 950.6650 0.0000 950.7350 0.2900 ;
    END
  END ahbso_in_70
  PIN ahbso_in_71
    DIRECTION OUTPUT ;
    USE SIGNAL ;
    PORT
      LAYER Metal2 ;
        RECT 1107.8650 0.0000 1107.9350 0.2900 ;
    END
  END ahbso_in_71
  PIN ahbso_in_72
    DIRECTION OUTPUT ;
    USE SIGNAL ;
    PORT
      LAYER Metal5 ;
        RECT 1112.1100 231.6700 1112.4000 231.7400 ;
    END
  END ahbso_in_72
  PIN ahbso_in_73
    DIRECTION OUTPUT ;
    USE SIGNAL ;
    PORT
      LAYER Metal2 ;
        RECT 1101.4650 0.0000 1101.5350 0.2900 ;
    END
  END ahbso_in_73
  PIN ahbso_in_74
    DIRECTION OUTPUT ;
    USE SIGNAL ;
    PORT
      LAYER Metal6 ;
        RECT 1107.6650 0.0000 1107.7350 0.2900 ;
    END
  END ahbso_in_74
  PIN ahbso_in_75
    DIRECTION OUTPUT ;
    USE SIGNAL ;
    PORT
      LAYER Metal4 ;
        RECT 928.6650 0.0000 928.7350 0.2900 ;
    END
  END ahbso_in_75
  PIN ahbso_in_76
    DIRECTION OUTPUT ;
    USE SIGNAL ;
    PORT
      LAYER Metal2 ;
        RECT 921.8650 0.0000 921.9350 0.2900 ;
    END
  END ahbso_in_76
  PIN ahbso_in_77
    DIRECTION OUTPUT ;
    USE SIGNAL ;
    PORT
      LAYER Metal6 ;
        RECT 1102.4650 0.0000 1102.5350 0.2900 ;
    END
  END ahbso_in_77
  PIN ahbso_in_78
    DIRECTION OUTPUT ;
    USE SIGNAL ;
    PORT
      LAYER Metal4 ;
        RECT 904.4650 0.0000 904.5350 0.2900 ;
    END
  END ahbso_in_78
  PIN ahbso_in_79
    DIRECTION OUTPUT ;
    USE SIGNAL ;
    PORT
      LAYER Metal8 ;
        RECT 1102.4650 0.0000 1102.5350 0.2900 ;
    END
  END ahbso_in_79
  PIN ahbso_in_80
    DIRECTION OUTPUT ;
    USE SIGNAL ;
    PORT
      LAYER Metal6 ;
        RECT 1102.0650 0.0000 1102.1350 0.2900 ;
    END
  END ahbso_in_80
  PIN ahbso_in_81
    DIRECTION OUTPUT ;
    USE SIGNAL ;
    PORT
      LAYER Metal8 ;
        RECT 1107.6650 0.0000 1107.7350 0.2900 ;
    END
  END ahbso_in_81
  PIN ahbso_in_82
    DIRECTION OUTPUT ;
    USE SIGNAL ;
    PORT
      LAYER Metal8 ;
        RECT 1102.0650 0.0000 1102.1350 0.2900 ;
    END
  END ahbso_in_82
  PIN ahbso_in_83
    DIRECTION OUTPUT ;
    USE SIGNAL ;
    PORT
      LAYER Metal4 ;
        RECT 1107.8650 0.0000 1107.9350 0.2900 ;
    END
  END ahbso_in_83
  PIN ahbso_in_84
    DIRECTION OUTPUT ;
    USE SIGNAL ;
    PORT
      LAYER Metal4 ;
        RECT 1101.6650 0.0000 1101.7350 0.2900 ;
    END
  END ahbso_in_84
  PIN ahbso_in_85
    DIRECTION OUTPUT ;
    USE SIGNAL ;
    PORT
      LAYER Metal6 ;
        RECT 1108.0650 0.0000 1108.1350 0.2900 ;
    END
  END ahbso_in_85
  PIN ahbso_in_86
    DIRECTION OUTPUT ;
    USE SIGNAL ;
    PORT
      LAYER Metal4 ;
        RECT 1101.2650 0.0000 1101.3350 0.2900 ;
    END
  END ahbso_in_86
  PIN ahbso_in_87
    DIRECTION OUTPUT ;
    USE SIGNAL ;
    PORT
      LAYER Metal4 ;
        RECT 901.6650 0.0000 901.7350 0.2900 ;
    END
  END ahbso_in_87
  PIN ahbso_in_88
    DIRECTION OUTPUT ;
    USE SIGNAL ;
    PORT
      LAYER Metal3 ;
        RECT 1112.1100 230.9100 1112.4000 230.9800 ;
    END
  END ahbso_in_88
  PIN ahbso_in_89
    DIRECTION OUTPUT ;
    USE SIGNAL ;
    PORT
      LAYER Metal2 ;
        RECT 908.6650 0.0000 908.7350 0.2900 ;
    END
  END ahbso_in_89
  PIN ahbso_in_90
    DIRECTION OUTPUT ;
    USE SIGNAL ;
    PORT
      LAYER Metal2 ;
        RECT 910.8650 0.0000 910.9350 0.2900 ;
    END
  END ahbso_in_90
  PIN ahbso_in_91
    DIRECTION OUTPUT ;
    USE SIGNAL ;
    PORT
      LAYER Metal3 ;
        RECT 1112.1100 50.7900 1112.4000 50.8600 ;
    END
  END ahbso_in_91
  PIN ahbso_in_92
    DIRECTION OUTPUT ;
    USE SIGNAL ;
    PORT
      LAYER Metal3 ;
        RECT 1112.1100 1547.6100 1112.4000 1547.6800 ;
    END
  END ahbso_in_92
  PIN ahbso_in_93
    DIRECTION OUTPUT ;
    USE SIGNAL ;
    PORT
      LAYER Metal3 ;
        RECT 1112.1100 229.7700 1112.4000 229.8400 ;
    END
  END ahbso_in_93
  PIN ahbso_in_94
    DIRECTION OUTPUT ;
    USE SIGNAL ;
    PORT
      LAYER Metal2 ;
        RECT 913.6650 0.0000 913.7350 0.2900 ;
    END
  END ahbso_in_94
  PIN ahbso_in_95
    DIRECTION OUTPUT ;
    USE SIGNAL ;
    PORT
      LAYER Metal2 ;
        RECT 919.6650 0.0000 919.7350 0.2900 ;
    END
  END ahbso_in_95
  PIN ahbso_in_96
    DIRECTION OUTPUT ;
    USE SIGNAL ;
    PORT
      LAYER Metal8 ;
        RECT 1108.0650 0.0000 1108.1350 0.2900 ;
    END
  END ahbso_in_96
  PIN ahbso_in_97
    DIRECTION OUTPUT ;
    USE SIGNAL ;
    PORT
      LAYER Metal2 ;
        RECT 1108.2650 0.0000 1108.3350 0.2900 ;
    END
  END ahbso_in_97
  PIN ahbso_in_98
    DIRECTION OUTPUT ;
    USE SIGNAL ;
    PORT
      LAYER Metal4 ;
        RECT 1108.2650 0.0000 1108.3350 0.2900 ;
    END
  END ahbso_in_98
  PIN ahbso_in_99
    DIRECTION OUTPUT ;
    USE SIGNAL ;
    PORT
      LAYER Metal3 ;
        RECT 1112.1100 682.3500 1112.4000 682.4200 ;
    END
  END ahbso_in_99
  PIN ahbso_in_101
    DIRECTION OUTPUT ;
    USE SIGNAL ;
    PORT
      LAYER Metal2 ;
        RECT 1057.6650 0.0000 1057.7350 0.2900 ;
    END
  END ahbso_in_101
  PIN desslavein_5
    DIRECTION INPUT ;
    USE SIGNAL ;
    PORT
      LAYER Metal2 ;
        RECT 1105.8650 0.0000 1105.9350 0.2900 ;
    END
  END desslavein_5
  PIN desslavein_10
    DIRECTION INPUT ;
    USE SIGNAL ;
    PORT
      LAYER Metal3 ;
        RECT 1112.1100 1513.4100 1112.4000 1513.4800 ;
    END
  END desslavein_10
  PIN desslavein_11
    DIRECTION INPUT ;
    USE SIGNAL ;
    PORT
      LAYER Metal2 ;
        RECT 973.2650 0.0000 973.3350 0.2900 ;
    END
  END desslavein_11
  PIN desslavein_12
    DIRECTION INPUT ;
    USE SIGNAL ;
    PORT
      LAYER Metal2 ;
        RECT 998.6650 0.0000 998.7350 0.2900 ;
    END
  END desslavein_12
  PIN desslavein_13
    DIRECTION INPUT ;
    USE SIGNAL ;
    PORT
      LAYER Metal2 ;
        RECT 978.0650 0.0000 978.1350 0.2900 ;
    END
  END desslavein_13
  PIN desslavein_14
    DIRECTION INPUT ;
    USE SIGNAL ;
    PORT
      LAYER Metal2 ;
        RECT 944.2650 0.0000 944.3350 0.2900 ;
    END
  END desslavein_14
  PIN desslavein_15
    DIRECTION INPUT ;
    USE SIGNAL ;
    PORT
      LAYER Metal2 ;
        RECT 935.0650 0.0000 935.1350 0.2900 ;
    END
  END desslavein_15
  PIN desslavein_16
    DIRECTION INPUT ;
    USE SIGNAL ;
    PORT
      LAYER Metal2 ;
        RECT 929.0650 0.0000 929.1350 0.2900 ;
    END
  END desslavein_16
  PIN desslavein_17
    DIRECTION INPUT ;
    USE SIGNAL ;
    PORT
      LAYER Metal3 ;
        RECT 1112.1100 1557.1100 1112.4000 1557.1800 ;
    END
  END desslavein_17
  PIN desslavein_18
    DIRECTION INPUT ;
    USE SIGNAL ;
    PORT
      LAYER Metal2 ;
        RECT 930.8650 0.0000 930.9350 0.2900 ;
    END
  END desslavein_18
  PIN desslavein_19
    DIRECTION INPUT ;
    USE SIGNAL ;
    PORT
      LAYER Metal2 ;
        RECT 923.4650 0.0000 923.5350 0.2900 ;
    END
  END desslavein_19
  PIN desslavein_20
    DIRECTION INPUT ;
    USE SIGNAL ;
    PORT
      LAYER Metal2 ;
        RECT 918.4650 0.0000 918.5350 0.2900 ;
    END
  END desslavein_20
  PIN desslavein_21
    DIRECTION INPUT ;
    USE SIGNAL ;
    PORT
      LAYER Metal3 ;
        RECT 1112.1100 1559.7700 1112.4000 1559.8400 ;
    END
  END desslavein_21
  PIN desslavein_22
    DIRECTION INPUT ;
    USE SIGNAL ;
    PORT
      LAYER Metal3 ;
        RECT 1112.1100 1567.3700 1112.4000 1567.4400 ;
    END
  END desslavein_22
  PIN desslavein_23
    DIRECTION INPUT ;
    USE SIGNAL ;
    PORT
      LAYER Metal2 ;
        RECT 898.0650 0.0000 898.1350 0.2900 ;
    END
  END desslavein_23
  PIN desslavein_24
    DIRECTION INPUT ;
    USE SIGNAL ;
    PORT
      LAYER Metal3 ;
        RECT 1112.1100 1560.5300 1112.4000 1560.6000 ;
    END
  END desslavein_24
  PIN desslavein_25
    DIRECTION INPUT ;
    USE SIGNAL ;
    PORT
      LAYER Metal4 ;
        RECT 897.8650 0.0000 897.9350 0.2900 ;
    END
  END desslavein_25
  PIN desslavein_26
    DIRECTION INPUT ;
    USE SIGNAL ;
    PORT
      LAYER Metal3 ;
        RECT 1112.1100 1551.0300 1112.4000 1551.1000 ;
    END
  END desslavein_26
  PIN desslavein_27
    DIRECTION INPUT ;
    USE SIGNAL ;
    PORT
      LAYER Metal4 ;
        RECT 899.0650 0.0000 899.1350 0.2900 ;
    END
  END desslavein_27
  PIN desslavein_28
    DIRECTION INPUT ;
    USE SIGNAL ;
    PORT
      LAYER Metal5 ;
        RECT 1112.1100 1565.4700 1112.4000 1565.5400 ;
    END
  END desslavein_28
  PIN desslavein_29
    DIRECTION INPUT ;
    USE SIGNAL ;
    PORT
      LAYER Metal2 ;
        RECT 896.2650 0.0000 896.3350 0.2900 ;
    END
  END desslavein_29
  PIN desslavein_30
    DIRECTION INPUT ;
    USE SIGNAL ;
    PORT
      LAYER Metal4 ;
        RECT 904.0650 0.0000 904.1350 0.2900 ;
    END
  END desslavein_30
  PIN desslavein_31
    DIRECTION INPUT ;
    USE SIGNAL ;
    PORT
      LAYER Metal2 ;
        RECT 907.4650 0.0000 907.5350 0.2900 ;
    END
  END desslavein_31
  PIN desslavein_32
    DIRECTION INPUT ;
    USE SIGNAL ;
    PORT
      LAYER Metal2 ;
        RECT 911.6650 0.0000 911.7350 0.2900 ;
    END
  END desslavein_32
  PIN desslavein_33
    DIRECTION INPUT ;
    USE SIGNAL ;
    PORT
      LAYER Metal2 ;
        RECT 916.8650 0.0000 916.9350 0.2900 ;
    END
  END desslavein_33
  PIN desslavein_34
    DIRECTION INPUT ;
    USE SIGNAL ;
    PORT
      LAYER Metal2 ;
        RECT 917.8650 0.0000 917.9350 0.2900 ;
    END
  END desslavein_34
  PIN desslavein_35
    DIRECTION INPUT ;
    USE SIGNAL ;
    PORT
      LAYER Metal2 ;
        RECT 915.0650 0.0000 915.1350 0.2900 ;
    END
  END desslavein_35
  PIN desslavein_36
    DIRECTION INPUT ;
    USE SIGNAL ;
    PORT
      LAYER Metal2 ;
        RECT 912.2650 0.0000 912.3350 0.2900 ;
    END
  END desslavein_36
  PIN desslavein_37
    DIRECTION INPUT ;
    USE SIGNAL ;
    PORT
      LAYER Metal2 ;
        RECT 920.0650 0.0000 920.1350 0.2900 ;
    END
  END desslavein_37
  PIN desslavein_38
    DIRECTION INPUT ;
    USE SIGNAL ;
    PORT
      LAYER Metal2 ;
        RECT 926.6650 0.0000 926.7350 0.2900 ;
    END
  END desslavein_38
  PIN desslavein_39
    DIRECTION INPUT ;
    USE SIGNAL ;
    PORT
      LAYER Metal2 ;
        RECT 937.6650 0.0000 937.7350 0.2900 ;
    END
  END desslavein_39
  PIN desslavein_40
    DIRECTION INPUT ;
    USE SIGNAL ;
    PORT
      LAYER Metal2 ;
        RECT 940.4650 0.0000 940.5350 0.2900 ;
    END
  END desslavein_40
  PIN desslavein_41
    DIRECTION INPUT ;
    USE SIGNAL ;
    PORT
      LAYER Metal4 ;
        RECT 944.0650 0.0000 944.1350 0.2900 ;
    END
  END desslavein_41
  PIN desslavein_42
    DIRECTION INPUT ;
    USE SIGNAL ;
    PORT
      LAYER Metal2 ;
        RECT 1104.8650 0.0000 1104.9350 0.2900 ;
    END
  END desslavein_42
  PIN desslavein_43
    DIRECTION INPUT ;
    USE SIGNAL ;
    PORT
      LAYER Metal2 ;
        RECT 1103.4650 0.0000 1103.5350 0.2900 ;
    END
  END desslavein_43
  PIN desslavein_44
    DIRECTION INPUT ;
    USE SIGNAL ;
    PORT
      LAYER Metal4 ;
        RECT 1103.6650 0.0000 1103.7350 0.2900 ;
    END
  END desslavein_44
  PIN desslavein_45
    DIRECTION INPUT ;
    USE SIGNAL ;
    PORT
      LAYER Metal2 ;
        RECT 1102.8650 0.0000 1102.9350 0.2900 ;
    END
  END desslavein_45
  PIN desslavein_46
    DIRECTION INPUT ;
    USE SIGNAL ;
    PORT
      LAYER Metal2 ;
        RECT 1102.4650 0.0000 1102.5350 0.2900 ;
    END
  END desslavein_46
  PIN desslavein_47
    DIRECTION INPUT ;
    USE SIGNAL ;
    PORT
      LAYER Metal3 ;
        RECT 1112.1100 15.0700 1112.4000 15.1400 ;
    END
  END desslavein_47
  PIN desslavein_48
    DIRECTION INPUT ;
    USE SIGNAL ;
    PORT
      LAYER Metal6 ;
        RECT 1103.4650 0.0000 1103.5350 0.2900 ;
    END
  END desslavein_48
  PIN desslavein_49
    DIRECTION INPUT ;
    USE SIGNAL ;
    PORT
      LAYER Metal3 ;
        RECT 1112.1100 12.2200 1112.4000 12.2900 ;
    END
  END desslavein_49
  PIN desslavein_50
    DIRECTION INPUT ;
    USE SIGNAL ;
    PORT
      LAYER Metal4 ;
        RECT 1103.2650 0.0000 1103.3350 0.2900 ;
    END
  END desslavein_50
  PIN desslavein_53
    DIRECTION INPUT ;
    USE SIGNAL ;
    PORT
      LAYER Metal2 ;
        RECT 1054.6650 0.0000 1054.7350 0.2900 ;
    END
  END desslavein_53
  PIN desslavein_54
    DIRECTION INPUT ;
    USE SIGNAL ;
    PORT
      LAYER Metal2 ;
        RECT 1056.6650 0.0000 1056.7350 0.2900 ;
    END
  END desslavein_54
  PIN desslavein_55
    DIRECTION INPUT ;
    USE SIGNAL ;
    PORT
      LAYER Metal3 ;
        RECT 1112.1100 700.9700 1112.4000 701.0400 ;
    END
  END desslavein_55
  PIN desslavein_56
    DIRECTION INPUT ;
    USE SIGNAL ;
    PORT
      LAYER Metal2 ;
        RECT 1100.2650 0.0000 1100.3350 0.2900 ;
    END
  END desslavein_56
  PIN desslavein_57
    DIRECTION INPUT ;
    USE SIGNAL ;
    PORT
      LAYER Metal2 ;
        RECT 1098.8650 0.0000 1098.9350 0.2900 ;
    END
  END desslavein_57
  PIN desslavein_58
    DIRECTION INPUT ;
    USE SIGNAL ;
    PORT
      LAYER Metal2 ;
        RECT 1100.8650 0.0000 1100.9350 0.2900 ;
    END
  END desslavein_58
  PIN desslavein_59
    DIRECTION INPUT ;
    USE SIGNAL ;
    PORT
      LAYER Metal7 ;
        RECT 1112.1100 5.2850 1112.4000 5.3550 ;
    END
  END desslavein_59
  PIN desslavein_60
    DIRECTION INPUT ;
    USE SIGNAL ;
    PORT
      LAYER Metal4 ;
        RECT 1100.8650 0.0000 1100.9350 0.2900 ;
    END
  END desslavein_60
  PIN desslavein_61
    DIRECTION INPUT ;
    USE SIGNAL ;
    PORT
      LAYER Metal2 ;
        RECT 1098.2650 0.0000 1098.3350 0.2900 ;
    END
  END desslavein_61
  PIN desslavein_62
    DIRECTION INPUT ;
    USE SIGNAL ;
    PORT
      LAYER Metal4 ;
        RECT 1098.6650 0.0000 1098.7350 0.2900 ;
    END
  END desslavein_62
  PIN desslavein_83
    DIRECTION INPUT ;
    USE SIGNAL ;
    PORT
      LAYER Metal2 ;
        RECT 1104.2650 0.0000 1104.3350 0.2900 ;
    END
  END desslavein_83
  PIN n_20005
    DIRECTION INPUT ;
    USE SIGNAL ;
    PORT
      LAYER Metal3 ;
        RECT 1112.1100 1607.8400 1112.4000 1607.9100 ;
    END
  END n_20005
  PIN clk
    DIRECTION INPUT ;
    USE SIGNAL ;
    PORT
      LAYER Metal3 ;
        RECT 1112.1100 743.1500 1112.4000 743.2200 ;
    END
  END clk
  PIN rst_n
    DIRECTION INPUT ;
    USE SIGNAL ;
    PORT
      LAYER Metal9 ;
        RECT 0.0000 2482.0300 0.2900 2482.1000 ;
    END
  END rst_n
  PIN bist_mismatch_2iologic\[13\]
    DIRECTION OUTPUT ;
    USE SIGNAL ;
    PORT
      LAYER Metal9 ;
        RECT 1112.1100 1585.9900 1112.4000 1586.0600 ;
    END
  END bist_mismatch_2iologic\[13\]
  PIN bist_mismatch_2iologic\[12\]
    DIRECTION OUTPUT ;
    USE SIGNAL ;
    PORT
      LAYER Metal5 ;
        RECT 1112.1100 811.3600 1112.4000 811.4300 ;
    END
  END bist_mismatch_2iologic\[12\]
  PIN bist_mismatch_2iologic\[11\]
    DIRECTION OUTPUT ;
    USE SIGNAL ;
    PORT
      LAYER Metal5 ;
        RECT 1112.1100 1023.4000 1112.4000 1023.4700 ;
    END
  END bist_mismatch_2iologic\[11\]
  PIN bist_mismatch_2iologic\[10\]
    DIRECTION OUTPUT ;
    USE SIGNAL ;
    PORT
      LAYER Metal5 ;
        RECT 1112.1100 1045.6300 1112.4000 1045.7000 ;
    END
  END bist_mismatch_2iologic\[10\]
  PIN bist_mismatch_2iologic\[9\]
    DIRECTION OUTPUT ;
    USE SIGNAL ;
    PORT
      LAYER Metal3 ;
        RECT 1112.1100 1611.6400 1112.4000 1611.7100 ;
    END
  END bist_mismatch_2iologic\[9\]
  PIN bist_mismatch_2iologic\[8\]
    DIRECTION OUTPUT ;
    USE SIGNAL ;
    PORT
      LAYER Metal3 ;
        RECT 1112.1100 1613.3500 1112.4000 1613.4200 ;
    END
  END bist_mismatch_2iologic\[8\]
  PIN bist_mismatch_2iologic\[7\]
    DIRECTION OUTPUT ;
    USE SIGNAL ;
    PORT
      LAYER Metal5 ;
        RECT 1112.1100 922.7000 1112.4000 922.7700 ;
    END
  END bist_mismatch_2iologic\[7\]
  PIN bist_mismatch_2iologic\[1\]
    DIRECTION OUTPUT ;
    USE SIGNAL ;
    PORT
      LAYER Metal7 ;
        RECT 1112.1100 687.0050 1112.4000 687.0750 ;
    END
  END bist_mismatch_2iologic\[1\]
  PIN bist_mismatch_2iologic\[0\]
    DIRECTION OUTPUT ;
    USE SIGNAL ;
    PORT
      LAYER Metal5 ;
        RECT 1112.1100 879.5700 1112.4000 879.6400 ;
    END
  END bist_mismatch_2iologic\[0\]
  PIN bist_mismatch_2iologic\[6\]
    DIRECTION OUTPUT ;
    USE SIGNAL ;
    PORT
      LAYER Metal5 ;
        RECT 1112.1100 888.3100 1112.4000 888.3800 ;
    END
  END bist_mismatch_2iologic\[6\]
  PIN bist_mismatch_2iologic\[5\]
    DIRECTION OUTPUT ;
    USE SIGNAL ;
    PORT
      LAYER Metal5 ;
        RECT 1112.1100 881.4700 1112.4000 881.5400 ;
    END
  END bist_mismatch_2iologic\[5\]
  PIN bist_mismatch_2iologic\[4\]
    DIRECTION OUTPUT ;
    USE SIGNAL ;
    PORT
      LAYER Metal3 ;
        RECT 1112.1100 1162.1000 1112.4000 1162.1700 ;
    END
  END bist_mismatch_2iologic\[4\]
  PIN bist_mismatch_2iologic\[3\]
    DIRECTION OUTPUT ;
    USE SIGNAL ;
    PORT
      LAYER Metal5 ;
        RECT 1112.1100 907.1200 1112.4000 907.1900 ;
    END
  END bist_mismatch_2iologic\[3\]
  PIN bist_mismatch_2iologic\[2\]
    DIRECTION OUTPUT ;
    USE SIGNAL ;
    PORT
      LAYER Metal5 ;
        RECT 1112.1100 893.4400 1112.4000 893.5100 ;
    END
  END bist_mismatch_2iologic\[2\]
  PIN bist_finish_2iologic\[13\]
    DIRECTION OUTPUT ;
    USE SIGNAL ;
    PORT
      LAYER Metal9 ;
        RECT 1112.1100 1648.6900 1112.4000 1648.7600 ;
    END
  END bist_finish_2iologic\[13\]
  PIN bist_finish_2iologic\[12\]
    DIRECTION OUTPUT ;
    USE SIGNAL ;
    PORT
      LAYER Metal5 ;
        RECT 1112.1100 797.6800 1112.4000 797.7500 ;
    END
  END bist_finish_2iologic\[12\]
  PIN bist_finish_2iologic\[11\]
    DIRECTION OUTPUT ;
    USE SIGNAL ;
    PORT
      LAYER Metal5 ;
        RECT 1112.1100 910.5400 1112.4000 910.6100 ;
    END
  END bist_finish_2iologic\[11\]
  PIN bist_finish_2iologic\[10\]
    DIRECTION OUTPUT ;
    USE SIGNAL ;
    PORT
      LAYER Metal7 ;
        RECT 1112.1100 886.5050 1112.4000 886.5750 ;
    END
  END bist_finish_2iologic\[10\]
  PIN bist_finish_2iologic\[9\]
    DIRECTION OUTPUT ;
    USE SIGNAL ;
    PORT
      LAYER Metal9 ;
        RECT 1112.1100 886.4100 1112.4000 886.4800 ;
    END
  END bist_finish_2iologic\[9\]
  PIN bist_finish_2iologic\[8\]
    DIRECTION OUTPUT ;
    USE SIGNAL ;
    PORT
      LAYER Metal5 ;
        RECT 1112.1100 924.2200 1112.4000 924.2900 ;
    END
  END bist_finish_2iologic\[8\]
  PIN bist_finish_2iologic\[7\]
    DIRECTION OUTPUT ;
    USE SIGNAL ;
    PORT
      LAYER Metal5 ;
        RECT 1112.1100 971.9100 1112.4000 971.9800 ;
    END
  END bist_finish_2iologic\[7\]
  PIN bist_finish_2iologic\[1\]
    DIRECTION OUTPUT ;
    USE SIGNAL ;
    PORT
      LAYER Metal7 ;
        RECT 1112.1100 686.4350 1112.4000 686.5050 ;
    END
  END bist_finish_2iologic\[1\]
  PIN bist_finish_2iologic\[0\]
    DIRECTION OUTPUT ;
    USE SIGNAL ;
    PORT
      LAYER Metal5 ;
        RECT 1112.1100 1013.1400 1112.4000 1013.2100 ;
    END
  END bist_finish_2iologic\[0\]
  PIN bist_finish_2iologic\[6\]
    DIRECTION OUTPUT ;
    USE SIGNAL ;
    PORT
      LAYER Metal5 ;
        RECT 1112.1100 1021.8800 1112.4000 1021.9500 ;
    END
  END bist_finish_2iologic\[6\]
  PIN bist_finish_2iologic\[5\]
    DIRECTION OUTPUT ;
    USE SIGNAL ;
    PORT
      LAYER Metal5 ;
        RECT 1112.1100 1016.3700 1112.4000 1016.4400 ;
    END
  END bist_finish_2iologic\[5\]
  PIN bist_finish_2iologic\[4\]
    DIRECTION OUTPUT ;
    USE SIGNAL ;
    PORT
      LAYER Metal5 ;
        RECT 1112.1100 1071.2800 1112.4000 1071.3500 ;
    END
  END bist_finish_2iologic\[4\]
  PIN bist_finish_2iologic\[3\]
    DIRECTION OUTPUT ;
    USE SIGNAL ;
    PORT
      LAYER Metal5 ;
        RECT 1112.1100 1059.3100 1112.4000 1059.3800 ;
    END
  END bist_finish_2iologic\[3\]
  PIN bist_finish_2iologic\[2\]
    DIRECTION OUTPUT ;
    USE SIGNAL ;
    PORT
      LAYER Metal5 ;
        RECT 1112.1100 1019.9800 1112.4000 1020.0500 ;
    END
  END bist_finish_2iologic\[2\]
  PIN mii2_rxd_2core[3]
    DIRECTION INPUT ;
    USE SIGNAL ;
    PORT
      LAYER Metal2 ;
        RECT 1107.6650 3171.7600 1107.7350 3172.0500 ;
    END
  END mii2_rxd_2core[3]
  PIN mii2_rxd_2core[2]
    DIRECTION INPUT ;
    USE SIGNAL ;
    PORT
      LAYER Metal9 ;
        RECT 1112.1100 2779.9500 1112.4000 2780.0200 ;
    END
  END mii2_rxd_2core[2]
  PIN mii2_rxd_2core[1]
    DIRECTION INPUT ;
    USE SIGNAL ;
    PORT
      LAYER Metal4 ;
        RECT 1107.4650 3171.7600 1107.5350 3172.0500 ;
    END
  END mii2_rxd_2core[1]
  PIN mii2_rxd_2core[0]
    DIRECTION INPUT ;
    USE SIGNAL ;
    PORT
      LAYER Metal9 ;
        RECT 1112.1100 2784.5100 1112.4000 2784.5800 ;
    END
  END mii2_rxd_2core[0]
  PIN mii2_txd_2pad\[0\]
    DIRECTION OUTPUT ;
    USE SIGNAL ;
    PORT
      LAYER Metal2 ;
        RECT 1025.8650 3171.7600 1025.9350 3172.0500 ;
    END
  END mii2_txd_2pad\[0\]
  PIN mii2_txd_2pad\[1\]
    DIRECTION OUTPUT ;
    USE SIGNAL ;
    PORT
      LAYER Metal9 ;
        RECT 1112.1100 1893.0300 1112.4000 1893.1000 ;
    END
  END mii2_txd_2pad\[1\]
  PIN mii2_txd_2pad\[2\]
    DIRECTION OUTPUT ;
    USE SIGNAL ;
    PORT
      LAYER Metal9 ;
        RECT 1112.1100 1889.6100 1112.4000 1889.6800 ;
    END
  END mii2_txd_2pad\[2\]
  PIN mii1_rxd_2core[3]
    DIRECTION INPUT ;
    USE SIGNAL ;
    PORT
      LAYER Metal2 ;
        RECT 747.0650 3171.7600 747.1350 3172.0500 ;
    END
  END mii1_rxd_2core[3]
  PIN mii1_rxd_2core[2]
    DIRECTION INPUT ;
    USE SIGNAL ;
    PORT
      LAYER Metal8 ;
        RECT 670.2650 3171.7600 670.3350 3172.0500 ;
    END
  END mii1_rxd_2core[2]
  PIN mii1_rxd_2core[1]
    DIRECTION INPUT ;
    USE SIGNAL ;
    PORT
      LAYER Metal8 ;
        RECT 593.4650 3171.7600 593.5350 3172.0500 ;
    END
  END mii1_rxd_2core[1]
  PIN mii1_rxd_2core[0]
    DIRECTION INPUT ;
    USE SIGNAL ;
    PORT
      LAYER Metal8 ;
        RECT 439.6650 3171.7600 439.7350 3172.0500 ;
    END
  END mii1_rxd_2core[0]
  PIN mii1_txd_2pad\[0\]
    DIRECTION OUTPUT ;
    USE SIGNAL ;
    PORT
      LAYER Metal9 ;
        RECT 0.0000 2654.9300 0.2900 2655.0000 ;
    END
  END mii1_txd_2pad\[0\]
  PIN mii1_txd_2pad\[1\]
    DIRECTION OUTPUT ;
    USE SIGNAL ;
    PORT
      LAYER Metal2 ;
        RECT 59.0650 3171.7600 59.1350 3172.0500 ;
    END
  END mii1_txd_2pad\[1\]
  PIN mii1_txd_2pad\[2\]
    DIRECTION OUTPUT ;
    USE SIGNAL ;
    PORT
      LAYER Metal8 ;
        RECT 135.8650 3171.7600 135.9350 3172.0500 ;
    END
  END mii1_txd_2pad\[2\]
  PIN dmaslaveout[50]
    DIRECTION OUTPUT ;
    USE SIGNAL ;
    PORT
      LAYER Metal2 ;
        RECT 1063.8650 0.0000 1063.9350 0.2900 ;
    END
  END dmaslaveout[50]
  PIN dmaslaveout[49]
    DIRECTION OUTPUT ;
    USE SIGNAL ;
    PORT
      LAYER Metal2 ;
        RECT 1064.8650 0.0000 1064.9350 0.2900 ;
    END
  END dmaslaveout[49]
  PIN dmaslaveout[48]
    DIRECTION OUTPUT ;
    USE SIGNAL ;
    PORT
      LAYER Metal2 ;
        RECT 1065.8650 0.0000 1065.9350 0.2900 ;
    END
  END dmaslaveout[48]
  PIN dmaslaveout[47]
    DIRECTION OUTPUT ;
    USE SIGNAL ;
    PORT
      LAYER Metal7 ;
        RECT 0.0000 1585.8950 0.2900 1585.9650 ;
    END
  END dmaslaveout[47]
  PIN dmaslaveout[46]
    DIRECTION OUTPUT ;
    USE SIGNAL ;
    PORT
      LAYER Metal9 ;
        RECT 0.0000 1585.9900 0.2900 1586.0600 ;
    END
  END dmaslaveout[46]
  PIN dmaslaveout[45]
    DIRECTION OUTPUT ;
    USE SIGNAL ;
    PORT
      LAYER Metal3 ;
        RECT 0.0000 1586.3700 0.2900 1586.4400 ;
    END
  END dmaslaveout[45]
  PIN dmaslaveout[44]
    DIRECTION OUTPUT ;
    USE SIGNAL ;
    PORT
      LAYER Metal5 ;
        RECT 0.0000 1586.3700 0.2900 1586.4400 ;
    END
  END dmaslaveout[44]
  PIN dmaslaveout[43]
    DIRECTION OUTPUT ;
    USE SIGNAL ;
    PORT
      LAYER Metal7 ;
        RECT 0.0000 1586.4650 0.2900 1586.5350 ;
    END
  END dmaslaveout[43]
  PIN dmaslaveout[42]
    DIRECTION OUTPUT ;
    USE SIGNAL ;
    PORT
      LAYER Metal7 ;
        RECT 0.0000 1585.3250 0.2900 1585.3950 ;
    END
  END dmaslaveout[42]
  PIN dmaslaveout[41]
    DIRECTION OUTPUT ;
    USE SIGNAL ;
    PORT
      LAYER Metal9 ;
        RECT 0.0000 1585.2300 0.2900 1585.3000 ;
    END
  END dmaslaveout[41]
  PIN dmaslaveout[40]
    DIRECTION OUTPUT ;
    USE SIGNAL ;
    PORT
      LAYER Metal9 ;
        RECT 0.0000 1586.7500 0.2900 1586.8200 ;
    END
  END dmaslaveout[40]
  PIN dmaslaveout[39]
    DIRECTION OUTPUT ;
    USE SIGNAL ;
    PORT
      LAYER Metal7 ;
        RECT 0.0000 1587.0350 0.2900 1587.1050 ;
    END
  END dmaslaveout[39]
  PIN dmaslaveout[38]
    DIRECTION OUTPUT ;
    USE SIGNAL ;
    PORT
      LAYER Metal7 ;
        RECT 0.0000 1584.7550 0.2900 1584.8250 ;
    END
  END dmaslaveout[38]
  PIN dmaslaveout[37]
    DIRECTION OUTPUT ;
    USE SIGNAL ;
    PORT
      LAYER Metal3 ;
        RECT 0.0000 1584.6600 0.2900 1584.7300 ;
    END
  END dmaslaveout[37]
  PIN dmaslaveout[36]
    DIRECTION OUTPUT ;
    USE SIGNAL ;
    PORT
      LAYER Metal5 ;
        RECT 0.0000 1584.6600 0.2900 1584.7300 ;
    END
  END dmaslaveout[36]
  PIN dmaslaveout[35]
    DIRECTION OUTPUT ;
    USE SIGNAL ;
    PORT
      LAYER Metal9 ;
        RECT 0.0000 1584.4700 0.2900 1584.5400 ;
    END
  END dmaslaveout[35]
  PIN dmaslaveout[34]
    DIRECTION OUTPUT ;
    USE SIGNAL ;
    PORT
      LAYER Metal9 ;
        RECT 0.0000 1587.5100 0.2900 1587.5800 ;
    END
  END dmaslaveout[34]
  PIN dmaslaveout[33]
    DIRECTION OUTPUT ;
    USE SIGNAL ;
    PORT
      LAYER Metal7 ;
        RECT 0.0000 1587.6050 0.2900 1587.6750 ;
    END
  END dmaslaveout[33]
  PIN dmaslaveout[32]
    DIRECTION OUTPUT ;
    USE SIGNAL ;
    PORT
      LAYER Metal7 ;
        RECT 0.0000 1584.1850 0.2900 1584.2550 ;
    END
  END dmaslaveout[32]
  PIN dmaslaveout[31]
    DIRECTION OUTPUT ;
    USE SIGNAL ;
    PORT
      LAYER Metal2 ;
        RECT 952.4650 0.0000 952.5350 0.2900 ;
    END
  END dmaslaveout[31]
  PIN dmaslaveout[30]
    DIRECTION OUTPUT ;
    USE SIGNAL ;
    PORT
      LAYER Metal4 ;
        RECT 976.4650 0.0000 976.5350 0.2900 ;
    END
  END dmaslaveout[30]
  PIN dmaslaveout[29]
    DIRECTION OUTPUT ;
    USE SIGNAL ;
    PORT
      LAYER Metal3 ;
        RECT 1112.1100 309.5700 1112.4000 309.6400 ;
    END
  END dmaslaveout[29]
  PIN dmaslaveout[28]
    DIRECTION OUTPUT ;
    USE SIGNAL ;
    PORT
      LAYER Metal2 ;
        RECT 948.8650 0.0000 948.9350 0.2900 ;
    END
  END dmaslaveout[28]
  PIN dmaslaveout[27]
    DIRECTION OUTPUT ;
    USE SIGNAL ;
    PORT
      LAYER Metal3 ;
        RECT 1112.1100 287.5300 1112.4000 287.6000 ;
    END
  END dmaslaveout[27]
  PIN dmaslaveout[26]
    DIRECTION OUTPUT ;
    USE SIGNAL ;
    PORT
      LAYER Metal2 ;
        RECT 950.8650 0.0000 950.9350 0.2900 ;
    END
  END dmaslaveout[26]
  PIN dmaslaveout[25]
    DIRECTION OUTPUT ;
    USE SIGNAL ;
    PORT
      LAYER Metal4 ;
        RECT 958.4650 0.0000 958.5350 0.2900 ;
    END
  END dmaslaveout[25]
  PIN dmaslaveout[24]
    DIRECTION OUTPUT ;
    USE SIGNAL ;
    PORT
      LAYER Metal2 ;
        RECT 963.4650 0.0000 963.5350 0.2900 ;
    END
  END dmaslaveout[24]
  PIN dmaslaveout[23]
    DIRECTION OUTPUT ;
    USE SIGNAL ;
    PORT
      LAYER Metal2 ;
        RECT 958.4650 0.0000 958.5350 0.2900 ;
    END
  END dmaslaveout[23]
  PIN dmaslaveout[22]
    DIRECTION OUTPUT ;
    USE SIGNAL ;
    PORT
      LAYER Metal3 ;
        RECT 1112.1100 256.7500 1112.4000 256.8200 ;
    END
  END dmaslaveout[22]
  PIN dmaslaveout[21]
    DIRECTION OUTPUT ;
    USE SIGNAL ;
    PORT
      LAYER Metal2 ;
        RECT 966.8650 0.0000 966.9350 0.2900 ;
    END
  END dmaslaveout[21]
  PIN dmaslaveout[20]
    DIRECTION OUTPUT ;
    USE SIGNAL ;
    PORT
      LAYER Metal2 ;
        RECT 969.8650 0.0000 969.9350 0.2900 ;
    END
  END dmaslaveout[20]
  PIN dmaslaveout[19]
    DIRECTION OUTPUT ;
    USE SIGNAL ;
    PORT
      LAYER Metal4 ;
        RECT 973.0650 0.0000 973.1350 0.2900 ;
    END
  END dmaslaveout[19]
  PIN dmaslaveout[18]
    DIRECTION OUTPUT ;
    USE SIGNAL ;
    PORT
      LAYER Metal2 ;
        RECT 971.8650 0.0000 971.9350 0.2900 ;
    END
  END dmaslaveout[18]
  PIN dmaslaveout[17]
    DIRECTION OUTPUT ;
    USE SIGNAL ;
    PORT
      LAYER Metal4 ;
        RECT 976.8650 0.0000 976.9350 0.2900 ;
    END
  END dmaslaveout[17]
  PIN dmaslaveout[16]
    DIRECTION OUTPUT ;
    USE SIGNAL ;
    PORT
      LAYER Metal5 ;
        RECT 1112.1100 309.9500 1112.4000 310.0200 ;
    END
  END dmaslaveout[16]
  PIN dmaslaveout[15]
    DIRECTION OUTPUT ;
    USE SIGNAL ;
    PORT
      LAYER Metal4 ;
        RECT 975.8650 0.0000 975.9350 0.2900 ;
    END
  END dmaslaveout[15]
  PIN dmaslaveout[14]
    DIRECTION OUTPUT ;
    USE SIGNAL ;
    PORT
      LAYER Metal2 ;
        RECT 980.6650 0.0000 980.7350 0.2900 ;
    END
  END dmaslaveout[14]
  PIN dmaslaveout[13]
    DIRECTION OUTPUT ;
    USE SIGNAL ;
    PORT
      LAYER Metal3 ;
        RECT 1112.1100 352.5100 1112.4000 352.5800 ;
    END
  END dmaslaveout[13]
  PIN dmaslaveout[12]
    DIRECTION OUTPUT ;
    USE SIGNAL ;
    PORT
      LAYER Metal2 ;
        RECT 976.2650 0.0000 976.3350 0.2900 ;
    END
  END dmaslaveout[12]
  PIN dmaslaveout[11]
    DIRECTION OUTPUT ;
    USE SIGNAL ;
    PORT
      LAYER Metal2 ;
        RECT 981.2650 0.0000 981.3350 0.2900 ;
    END
  END dmaslaveout[11]
  PIN dmaslaveout[10]
    DIRECTION OUTPUT ;
    USE SIGNAL ;
    PORT
      LAYER Metal3 ;
        RECT 1112.1100 367.7100 1112.4000 367.7800 ;
    END
  END dmaslaveout[10]
  PIN dmaslaveout[9]
    DIRECTION OUTPUT ;
    USE SIGNAL ;
    PORT
      LAYER Metal6 ;
        RECT 958.2650 0.0000 958.3350 0.2900 ;
    END
  END dmaslaveout[9]
  PIN dmaslaveout[8]
    DIRECTION OUTPUT ;
    USE SIGNAL ;
    PORT
      LAYER Metal2 ;
        RECT 962.4650 0.0000 962.5350 0.2900 ;
    END
  END dmaslaveout[8]
  PIN dmaslaveout[7]
    DIRECTION OUTPUT ;
    USE SIGNAL ;
    PORT
      LAYER Metal2 ;
        RECT 961.8650 0.0000 961.9350 0.2900 ;
    END
  END dmaslaveout[7]
  PIN dmaslaveout[6]
    DIRECTION OUTPUT ;
    USE SIGNAL ;
    PORT
      LAYER Metal3 ;
        RECT 1112.1100 384.8100 1112.4000 384.8800 ;
    END
  END dmaslaveout[6]
  PIN dmaslaveout[5]
    DIRECTION OUTPUT ;
    USE SIGNAL ;
    PORT
      LAYER Metal2 ;
        RECT 958.0650 0.0000 958.1350 0.2900 ;
    END
  END dmaslaveout[5]
  PIN dmaslaveout[4]
    DIRECTION OUTPUT ;
    USE SIGNAL ;
    PORT
      LAYER Metal2 ;
        RECT 955.6650 0.0000 955.7350 0.2900 ;
    END
  END dmaslaveout[4]
  PIN dmaslaveout[3]
    DIRECTION OUTPUT ;
    USE SIGNAL ;
    PORT
      LAYER Metal2 ;
        RECT 956.2650 0.0000 956.3350 0.2900 ;
    END
  END dmaslaveout[3]
  PIN dmaslaveout[2]
    DIRECTION OUTPUT ;
    USE SIGNAL ;
    PORT
      LAYER Metal2 ;
        RECT 953.8650 0.0000 953.9350 0.2900 ;
    END
  END dmaslaveout[2]
  PIN dmaslaveout[1]
    DIRECTION OUTPUT ;
    USE SIGNAL ;
    PORT
      LAYER Metal2 ;
        RECT 957.2650 0.0000 957.3350 0.2900 ;
    END
  END dmaslaveout[1]
  PIN dmaslaveout[0]
    DIRECTION OUTPUT ;
    USE SIGNAL ;
    PORT
      LAYER Metal2 ;
        RECT 1005.0650 0.0000 1005.1350 0.2900 ;
    END
  END dmaslaveout[0]
  PIN utmi_opmode_2pad[1]
    DIRECTION OUTPUT ;
    USE SIGNAL ;
    PORT
      LAYER Metal9 ;
        RECT 0.0000 1321.1300 0.2900 1321.2000 ;
    END
  END utmi_opmode_2pad[1]
  PIN utmi_opmode_2pad[0]
    DIRECTION OUTPUT ;
    USE SIGNAL ;
    PORT
      LAYER Metal7 ;
        RECT 0.0000 1257.8600 0.2900 1257.9300 ;
    END
  END utmi_opmode_2pad[0]
  PIN utmi_linestate_2core[1]
    DIRECTION INPUT ;
    USE SIGNAL ;
    PORT
      LAYER Metal9 ;
        RECT 0.0000 1191.5500 0.2900 1191.6200 ;
    END
  END utmi_linestate_2core[1]
  PIN utmi_linestate_2core[0]
    DIRECTION INPUT ;
    USE SIGNAL ;
    PORT
      LAYER Metal9 ;
        RECT 0.0000 1128.0900 0.2900 1128.1600 ;
    END
  END utmi_linestate_2core[0]
  PIN utmi_datain_2core[7]
    DIRECTION INPUT ;
    USE SIGNAL ;
    PORT
      LAYER Metal9 ;
        RECT 0.0000 1074.1300 0.2900 1074.2000 ;
    END
  END utmi_datain_2core[7]
  PIN utmi_datain_2core[6]
    DIRECTION INPUT ;
    USE SIGNAL ;
    PORT
      LAYER Metal9 ;
        RECT 0.0000 1011.0500 0.2900 1011.1200 ;
    END
  END utmi_datain_2core[6]
  PIN utmi_datain_2core[5]
    DIRECTION INPUT ;
    USE SIGNAL ;
    PORT
      LAYER Metal9 ;
        RECT 0.0000 884.5100 0.2900 884.5800 ;
    END
  END utmi_datain_2core[5]
  PIN utmi_datain_2core[4]
    DIRECTION INPUT ;
    USE SIGNAL ;
    PORT
      LAYER Metal9 ;
        RECT 0.0000 821.4300 0.2900 821.5000 ;
    END
  END utmi_datain_2core[4]
  PIN utmi_datain_2core[3]
    DIRECTION INPUT ;
    USE SIGNAL ;
    PORT
      LAYER Metal7 ;
        RECT 0.0000 758.2550 0.2900 758.3250 ;
    END
  END utmi_datain_2core[3]
  PIN utmi_datain_2core[2]
    DIRECTION INPUT ;
    USE SIGNAL ;
    PORT
      LAYER Metal9 ;
        RECT 0.0000 695.2700 0.2900 695.3400 ;
    END
  END utmi_datain_2core[2]
  PIN utmi_datain_2core[1]
    DIRECTION INPUT ;
    USE SIGNAL ;
    PORT
      LAYER Metal9 ;
        RECT 0.0000 632.1900 0.2900 632.2600 ;
    END
  END utmi_datain_2core[1]
  PIN utmi_datain_2core[0]
    DIRECTION INPUT ;
    USE SIGNAL ;
    PORT
      LAYER Metal9 ;
        RECT 0.0000 569.1100 0.2900 569.1800 ;
    END
  END utmi_datain_2core[0]
  PIN utmi_dataout_2pad[7]
    DIRECTION OUTPUT ;
    USE SIGNAL ;
    PORT
      LAYER Metal9 ;
        RECT 0.0000 1068.8100 0.2900 1068.8800 ;
    END
  END utmi_dataout_2pad[7]
  PIN utmi_dataout_2pad[6]
    DIRECTION OUTPUT ;
    USE SIGNAL ;
    PORT
      LAYER Metal9 ;
        RECT 0.0000 1005.3500 0.2900 1005.4200 ;
    END
  END utmi_dataout_2pad[6]
  PIN utmi_dataout_2pad[5]
    DIRECTION OUTPUT ;
    USE SIGNAL ;
    PORT
      LAYER Metal3 ;
        RECT 0.0000 879.1900 0.2900 879.2600 ;
    END
  END utmi_dataout_2pad[5]
  PIN utmi_dataout_2pad[4]
    DIRECTION OUTPUT ;
    USE SIGNAL ;
    PORT
      LAYER Metal9 ;
        RECT 0.0000 816.1100 0.2900 816.1800 ;
    END
  END utmi_dataout_2pad[4]
  PIN utmi_dataout_2pad[3]
    DIRECTION OUTPUT ;
    USE SIGNAL ;
    PORT
      LAYER Metal9 ;
        RECT 0.0000 753.0300 0.2900 753.1000 ;
    END
  END utmi_dataout_2pad[3]
  PIN utmi_dataout_2pad[2]
    DIRECTION OUTPUT ;
    USE SIGNAL ;
    PORT
      LAYER Metal9 ;
        RECT 0.0000 689.5700 0.2900 689.6400 ;
    END
  END utmi_dataout_2pad[2]
  PIN utmi_dataout_2pad[1]
    DIRECTION OUTPUT ;
    USE SIGNAL ;
    PORT
      LAYER Metal9 ;
        RECT 0.0000 626.4900 0.2900 626.5600 ;
    END
  END utmi_dataout_2pad[1]
  PIN utmi_dataout_2pad[0]
    DIRECTION OUTPUT ;
    USE SIGNAL ;
    PORT
      LAYER Metal9 ;
        RECT 0.0000 563.4100 0.2900 563.4800 ;
    END
  END utmi_dataout_2pad[0]
  PIN ide_cs_n_2pad[1]
    DIRECTION OUTPUT ;
    USE SIGNAL ;
    PORT
      LAYER Metal9 ;
        RECT 1112.1100 45.8500 1112.4000 45.9200 ;
    END
  END ide_cs_n_2pad[1]
  PIN ide_cs_n_2pad[0]
    DIRECTION OUTPUT ;
    USE SIGNAL ;
    PORT
      LAYER Metal9 ;
        RECT 1112.1100 2654.5500 1112.4000 2654.6200 ;
    END
  END ide_cs_n_2pad[0]
  PIN ide_da_2pad[2]
    DIRECTION OUTPUT ;
    USE SIGNAL ;
    PORT
      LAYER Metal9 ;
        RECT 0.0000 13.1700 0.2900 13.2400 ;
    END
  END ide_da_2pad[2]
  PIN ide_da_2pad[1]
    DIRECTION OUTPUT ;
    USE SIGNAL ;
    PORT
      LAYER Metal2 ;
        RECT 754.2650 0.0000 754.3350 0.2900 ;
    END
  END ide_da_2pad[1]
  PIN ide_da_2pad[0]
    DIRECTION OUTPUT ;
    USE SIGNAL ;
    PORT
      LAYER Metal2 ;
        RECT 752.8650 0.0000 752.9350 0.2900 ;
    END
  END ide_da_2pad[0]
  PIN ide_dd_2pad[15]
    DIRECTION OUTPUT ;
    USE SIGNAL ;
    PORT
      LAYER Metal9 ;
        RECT 0.0000 310.7100 0.2900 310.7800 ;
    END
  END ide_dd_2pad[15]
  PIN ide_dd_2pad[14]
    DIRECTION OUTPUT ;
    USE SIGNAL ;
    PORT
      LAYER Metal9 ;
        RECT 0.0000 247.6300 0.2900 247.7000 ;
    END
  END ide_dd_2pad[14]
  PIN ide_dd_2pad[13]
    DIRECTION OUTPUT ;
    USE SIGNAL ;
    PORT
      LAYER Metal9 ;
        RECT 0.0000 184.5500 0.2900 184.6200 ;
    END
  END ide_dd_2pad[13]
  PIN ide_dd_2pad[12]
    DIRECTION OUTPUT ;
    USE SIGNAL ;
    PORT
      LAYER Metal9 ;
        RECT 0.0000 121.4700 0.2900 121.5400 ;
    END
  END ide_dd_2pad[12]
  PIN ide_dd_2pad[11]
    DIRECTION OUTPUT ;
    USE SIGNAL ;
    PORT
      LAYER Metal3 ;
        RECT 0.0000 58.0100 0.2900 58.0800 ;
    END
  END ide_dd_2pad[11]
  PIN ide_dd_2pad[10]
    DIRECTION OUTPUT ;
    USE SIGNAL ;
    PORT
      LAYER Metal2 ;
        RECT 554.0650 0.0000 554.1350 0.2900 ;
    END
  END ide_dd_2pad[10]
  PIN ide_dd_2pad[9]
    DIRECTION OUTPUT ;
    USE SIGNAL ;
    PORT
      LAYER Metal2 ;
        RECT 553.0650 0.0000 553.1350 0.2900 ;
    END
  END ide_dd_2pad[9]
  PIN ide_dd_2pad[8]
    DIRECTION OUTPUT ;
    USE SIGNAL ;
    PORT
      LAYER Metal4 ;
        RECT 553.8650 0.0000 553.9350 0.2900 ;
    END
  END ide_dd_2pad[8]
  PIN ide_dd_2pad[7]
    DIRECTION OUTPUT ;
    USE SIGNAL ;
    PORT
      LAYER Metal2 ;
        RECT 558.8650 0.0000 558.9350 0.2900 ;
    END
  END ide_dd_2pad[7]
  PIN ide_dd_2pad[6]
    DIRECTION OUTPUT ;
    USE SIGNAL ;
    PORT
      LAYER Metal9 ;
        RECT 0.0000 5.9500 0.2900 6.0200 ;
    END
  END ide_dd_2pad[6]
  PIN ide_dd_2pad[5]
    DIRECTION OUTPUT ;
    USE SIGNAL ;
    PORT
      LAYER Metal3 ;
        RECT 0.0000 5.5700 0.2900 5.6400 ;
    END
  END ide_dd_2pad[5]
  PIN ide_dd_2pad[4]
    DIRECTION OUTPUT ;
    USE SIGNAL ;
    PORT
      LAYER Metal3 ;
        RECT 0.0000 6.1400 0.2900 6.2100 ;
    END
  END ide_dd_2pad[4]
  PIN ide_dd_2pad[3]
    DIRECTION OUTPUT ;
    USE SIGNAL ;
    PORT
      LAYER Metal5 ;
        RECT 0.0000 5.5700 0.2900 5.6400 ;
    END
  END ide_dd_2pad[3]
  PIN ide_dd_2pad[2]
    DIRECTION OUTPUT ;
    USE SIGNAL ;
    PORT
      LAYER Metal2 ;
        RECT 749.0650 0.0000 749.1350 0.2900 ;
    END
  END ide_dd_2pad[2]
  PIN ide_dd_2pad[1]
    DIRECTION OUTPUT ;
    USE SIGNAL ;
    PORT
      LAYER Metal9 ;
        RECT 0.0000 8.9900 0.2900 9.0600 ;
    END
  END ide_dd_2pad[1]
  PIN ide_dd_2pad[0]
    DIRECTION OUTPUT ;
    USE SIGNAL ;
    PORT
      LAYER Metal3 ;
        RECT 0.0000 8.6100 0.2900 8.6800 ;
    END
  END ide_dd_2pad[0]
  PIN ide_dd_2core[15]
    DIRECTION INPUT ;
    USE SIGNAL ;
    PORT
      LAYER Metal9 ;
        RECT 0.0000 316.4100 0.2900 316.4800 ;
    END
  END ide_dd_2core[15]
  PIN ide_dd_2core[14]
    DIRECTION INPUT ;
    USE SIGNAL ;
    PORT
      LAYER Metal9 ;
        RECT 0.0000 253.3300 0.2900 253.4000 ;
    END
  END ide_dd_2core[14]
  PIN ide_dd_2core[13]
    DIRECTION INPUT ;
    USE SIGNAL ;
    PORT
      LAYER Metal9 ;
        RECT 0.0000 190.2500 0.2900 190.3200 ;
    END
  END ide_dd_2core[13]
  PIN ide_dd_2core[12]
    DIRECTION INPUT ;
    USE SIGNAL ;
    PORT
      LAYER Metal9 ;
        RECT 0.0000 126.7900 0.2900 126.8600 ;
    END
  END ide_dd_2core[12]
  PIN ide_dd_2core[11]
    DIRECTION INPUT ;
    USE SIGNAL ;
    PORT
      LAYER Metal3 ;
        RECT 0.0000 63.7100 0.2900 63.7800 ;
    END
  END ide_dd_2core[11]
  PIN ide_dd_2core[10]
    DIRECTION INPUT ;
    USE SIGNAL ;
    PORT
      LAYER Metal3 ;
        RECT 0.0000 1.0100 0.2900 1.0800 ;
    END
  END ide_dd_2core[10]
  PIN ide_dd_2core[9]
    DIRECTION INPUT ;
    USE SIGNAL ;
    PORT
      LAYER Metal2 ;
        RECT 528.8650 0.0000 528.9350 0.2900 ;
    END
  END ide_dd_2core[9]
  PIN ide_dd_2core[8]
    DIRECTION INPUT ;
    USE SIGNAL ;
    PORT
      LAYER Metal2 ;
        RECT 521.8650 0.0000 521.9350 0.2900 ;
    END
  END ide_dd_2core[8]
  PIN ide_dd_2core[7]
    DIRECTION INPUT ;
    USE SIGNAL ;
    PORT
      LAYER Metal2 ;
        RECT 527.8650 0.0000 527.9350 0.2900 ;
    END
  END ide_dd_2core[7]
  PIN ide_dd_2core[6]
    DIRECTION INPUT ;
    USE SIGNAL ;
    PORT
      LAYER Metal9 ;
        RECT 0.0000 48.5100 0.2900 48.5800 ;
    END
  END ide_dd_2core[6]
  PIN ide_dd_2core[5]
    DIRECTION INPUT ;
    USE SIGNAL ;
    PORT
      LAYER Metal9 ;
        RECT 0.0000 51.9300 0.2900 52.0000 ;
    END
  END ide_dd_2core[5]
  PIN ide_dd_2core[4]
    DIRECTION INPUT ;
    USE SIGNAL ;
    PORT
      LAYER Metal2 ;
        RECT 13.4650 0.0000 13.5350 0.2900 ;
    END
  END ide_dd_2core[4]
  PIN ide_dd_2core[3]
    DIRECTION INPUT ;
    USE SIGNAL ;
    PORT
      LAYER Metal2 ;
        RECT 771.2650 0.0000 771.3350 0.2900 ;
    END
  END ide_dd_2core[3]
  PIN ide_dd_2core[2]
    DIRECTION INPUT ;
    USE SIGNAL ;
    PORT
      LAYER Metal2 ;
        RECT 746.2650 0.0000 746.3350 0.2900 ;
    END
  END ide_dd_2core[2]
  PIN ide_dd_2core[1]
    DIRECTION INPUT ;
    USE SIGNAL ;
    PORT
      LAYER Metal9 ;
        RECT 0.0000 15.0700 0.2900 15.1400 ;
    END
  END ide_dd_2core[1]
  PIN ide_dd_2core[0]
    DIRECTION INPUT ;
    USE SIGNAL ;
    PORT
      LAYER Metal2 ;
        RECT 747.0650 0.0000 747.1350 0.2900 ;
    END
  END ide_dd_2core[0]
  PIN vid_b_2pad[7]
    DIRECTION OUTPUT ;
    USE SIGNAL ;
    PORT
      LAYER Metal3 ;
        RECT 1112.1100 922.7000 1112.4000 922.7700 ;
    END
  END vid_b_2pad[7]
  PIN vid_b_2pad[6]
    DIRECTION OUTPUT ;
    USE SIGNAL ;
    PORT
      LAYER Metal3 ;
        RECT 1112.1100 888.5000 1112.4000 888.5700 ;
    END
  END vid_b_2pad[6]
  PIN vid_b_2pad[5]
    DIRECTION OUTPUT ;
    USE SIGNAL ;
    PORT
      LAYER Metal3 ;
        RECT 1112.1100 881.6600 1112.4000 881.7300 ;
    END
  END vid_b_2pad[5]
  PIN vid_b_2pad[4]
    DIRECTION OUTPUT ;
    USE SIGNAL ;
    PORT
      LAYER Metal3 ;
        RECT 1112.1100 902.1800 1112.4000 902.2500 ;
    END
  END vid_b_2pad[4]
  PIN vid_b_2pad[3]
    DIRECTION OUTPUT ;
    USE SIGNAL ;
    PORT
      LAYER Metal3 ;
        RECT 1112.1100 906.9300 1112.4000 907.0000 ;
    END
  END vid_b_2pad[3]
  PIN vid_b_2pad[2]
    DIRECTION OUTPUT ;
    USE SIGNAL ;
    PORT
      LAYER Metal3 ;
        RECT 1112.1100 893.2500 1112.4000 893.3200 ;
    END
  END vid_b_2pad[2]
  PIN vid_b_2pad[1]
    DIRECTION OUTPUT ;
    USE SIGNAL ;
    PORT
      LAYER Metal3 ;
        RECT 1112.1100 686.7200 1112.4000 686.7900 ;
    END
  END vid_b_2pad[1]
  PIN vid_b_2pad[0]
    DIRECTION OUTPUT ;
    USE SIGNAL ;
    PORT
      LAYER Metal3 ;
        RECT 1112.1100 879.5700 1112.4000 879.6400 ;
    END
  END vid_b_2pad[0]
  PIN vid_g_2pad[7]
    DIRECTION OUTPUT ;
    USE SIGNAL ;
    PORT
      LAYER Metal3 ;
        RECT 1112.1100 811.1700 1112.4000 811.2400 ;
    END
  END vid_g_2pad[7]
  PIN vid_g_2pad[6]
    DIRECTION OUTPUT ;
    USE SIGNAL ;
    PORT
      LAYER Metal3 ;
        RECT 1112.1100 1023.2100 1112.4000 1023.2800 ;
    END
  END vid_g_2pad[6]
  PIN vid_g_2pad[5]
    DIRECTION OUTPUT ;
    USE SIGNAL ;
    PORT
      LAYER Metal3 ;
        RECT 1112.1100 1045.8200 1112.4000 1045.8900 ;
    END
  END vid_g_2pad[5]
  PIN vid_g_2pad[4]
    DIRECTION OUTPUT ;
    USE SIGNAL ;
    PORT
      LAYER Metal3 ;
        RECT 1112.1100 1071.0900 1112.4000 1071.1600 ;
    END
  END vid_g_2pad[4]
  PIN vid_g_2pad[3]
    DIRECTION OUTPUT ;
    USE SIGNAL ;
    PORT
      LAYER Metal3 ;
        RECT 1112.1100 1059.5000 1112.4000 1059.5700 ;
    END
  END vid_g_2pad[3]
  PIN vid_g_2pad[2]
    DIRECTION OUTPUT ;
    USE SIGNAL ;
    PORT
      LAYER Metal3 ;
        RECT 1112.1100 1019.7900 1112.4000 1019.8600 ;
    END
  END vid_g_2pad[2]
  PIN vid_g_2pad[1]
    DIRECTION OUTPUT ;
    USE SIGNAL ;
    PORT
      LAYER Metal5 ;
        RECT 1112.1100 686.7200 1112.4000 686.7900 ;
    END
  END vid_g_2pad[1]
  PIN vid_g_2pad[0]
    DIRECTION OUTPUT ;
    USE SIGNAL ;
    PORT
      LAYER Metal3 ;
        RECT 1112.1100 1012.9500 1112.4000 1013.0200 ;
    END
  END vid_g_2pad[0]
  PIN vid_r_2pad[7]
    DIRECTION OUTPUT ;
    USE SIGNAL ;
    PORT
      LAYER Metal3 ;
        RECT 1112.1100 797.4900 1112.4000 797.5600 ;
    END
  END vid_r_2pad[7]
  PIN vid_r_2pad[6]
    DIRECTION OUTPUT ;
    USE SIGNAL ;
    PORT
      LAYER Metal3 ;
        RECT 1112.1100 910.3500 1112.4000 910.4200 ;
    END
  END vid_r_2pad[6]
  PIN vid_r_2pad[5]
    DIRECTION OUTPUT ;
    USE SIGNAL ;
    PORT
      LAYER Metal5 ;
        RECT 1112.1100 886.4100 1112.4000 886.4800 ;
    END
  END vid_r_2pad[5]
  PIN vid_r_2pad[4]
    DIRECTION OUTPUT ;
    USE SIGNAL ;
    PORT
      LAYER Metal3 ;
        RECT 1112.1100 886.4100 1112.4000 886.4800 ;
    END
  END vid_r_2pad[4]
  PIN vid_r_2pad[3]
    DIRECTION OUTPUT ;
    USE SIGNAL ;
    PORT
      LAYER Metal3 ;
        RECT 1112.1100 924.0300 1112.4000 924.1000 ;
    END
  END vid_r_2pad[3]
  PIN vid_r_2pad[2]
    DIRECTION OUTPUT ;
    USE SIGNAL ;
    PORT
      LAYER Metal3 ;
        RECT 1112.1100 971.9100 1112.4000 971.9800 ;
    END
  END vid_r_2pad[2]
  PIN vid_r_2pad[1]
    DIRECTION OUTPUT ;
    USE SIGNAL ;
    PORT
      LAYER Metal3 ;
        RECT 1112.1100 1021.8800 1112.4000 1021.9500 ;
    END
  END vid_r_2pad[1]
  PIN vid_r_2pad[0]
    DIRECTION OUTPUT ;
    USE SIGNAL ;
    PORT
      LAYER Metal3 ;
        RECT 1112.1100 1016.3700 1112.4000 1016.4400 ;
    END
  END vid_r_2pad[0]
  PIN vid_d_2core[31]
    DIRECTION INPUT ;
    USE SIGNAL ;
    PORT
      LAYER Metal9 ;
        RECT 0.0000 2643.9100 0.2900 2643.9800 ;
    END
  END vid_d_2core[31]
  PIN vid_d_2core[30]
    DIRECTION INPUT ;
    USE SIGNAL ;
    PORT
      LAYER Metal7 ;
        RECT 0.0000 2580.5450 0.2900 2580.6150 ;
    END
  END vid_d_2core[30]
  PIN vid_d_2core[29]
    DIRECTION INPUT ;
    USE SIGNAL ;
    PORT
      LAYER Metal9 ;
        RECT 0.0000 2517.7500 0.2900 2517.8200 ;
    END
  END vid_d_2core[29]
  PIN vid_d_2core[28]
    DIRECTION INPUT ;
    USE SIGNAL ;
    PORT
      LAYER Metal7 ;
        RECT 0.0000 2454.2900 0.2900 2454.3600 ;
    END
  END vid_d_2core[28]
  PIN vid_d_2core[27]
    DIRECTION INPUT ;
    USE SIGNAL ;
    PORT
      LAYER Metal9 ;
        RECT 0.0000 2391.2100 0.2900 2391.2800 ;
    END
  END vid_d_2core[27]
  PIN vid_d_2core[26]
    DIRECTION INPUT ;
    USE SIGNAL ;
    PORT
      LAYER Metal9 ;
        RECT 0.0000 2328.1300 0.2900 2328.2000 ;
    END
  END vid_d_2core[26]
  PIN vid_d_2core[25]
    DIRECTION INPUT ;
    USE SIGNAL ;
    PORT
      LAYER Metal9 ;
        RECT 0.0000 2265.0500 0.2900 2265.1200 ;
    END
  END vid_d_2core[25]
  PIN vid_d_2core[24]
    DIRECTION INPUT ;
    USE SIGNAL ;
    PORT
      LAYER Metal7 ;
        RECT 0.0000 2201.7800 0.2900 2201.8500 ;
    END
  END vid_d_2core[24]
  PIN vid_d_2core[23]
    DIRECTION INPUT ;
    USE SIGNAL ;
    PORT
      LAYER Metal9 ;
        RECT 0.0000 2138.8900 0.2900 2138.9600 ;
    END
  END vid_d_2core[23]
  PIN vid_d_2core[22]
    DIRECTION INPUT ;
    USE SIGNAL ;
    PORT
      LAYER Metal9 ;
        RECT 0.0000 2012.3500 0.2900 2012.4200 ;
    END
  END vid_d_2core[22]
  PIN vid_d_2core[21]
    DIRECTION INPUT ;
    USE SIGNAL ;
    PORT
      LAYER Metal9 ;
        RECT 1112.1100 1350.0100 1112.4000 1350.0800 ;
    END
  END vid_d_2core[21]
  PIN vid_d_2core[20]
    DIRECTION INPUT ;
    USE SIGNAL ;
    PORT
      LAYER Metal9 ;
        RECT 1112.1100 1831.8500 1112.4000 1831.9200 ;
    END
  END vid_d_2core[20]
  PIN vid_d_2core[19]
    DIRECTION INPUT ;
    USE SIGNAL ;
    PORT
      LAYER Metal8 ;
        RECT 516.6650 3171.7600 516.7350 3172.0500 ;
    END
  END vid_d_2core[19]
  PIN vid_d_2core[18]
    DIRECTION INPUT ;
    USE SIGNAL ;
    PORT
      LAYER Metal2 ;
        RECT 1094.6650 3171.7600 1094.7350 3172.0500 ;
    END
  END vid_d_2core[18]
  PIN vid_d_2core[17]
    DIRECTION INPUT ;
    USE SIGNAL ;
    PORT
      LAYER Metal9 ;
        RECT 1112.1100 2602.4900 1112.4000 2602.5600 ;
    END
  END vid_d_2core[17]
  PIN vid_d_2core[16]
    DIRECTION INPUT ;
    USE SIGNAL ;
    PORT
      LAYER Metal4 ;
        RECT 1107.8650 3171.7600 1107.9350 3172.0500 ;
    END
  END vid_d_2core[16]
  PIN vid_d_2core[15]
    DIRECTION INPUT ;
    USE SIGNAL ;
    PORT
      LAYER Metal8 ;
        RECT 1024.6650 3171.7600 1024.7350 3172.0500 ;
    END
  END vid_d_2core[15]
  PIN vid_d_2core[14]
    DIRECTION INPUT ;
    USE SIGNAL ;
    PORT
      LAYER Metal9 ;
        RECT 1112.1100 2407.5500 1112.4000 2407.6200 ;
    END
  END vid_d_2core[14]
  PIN vid_d_2core[13]
    DIRECTION INPUT ;
    USE SIGNAL ;
    PORT
      LAYER Metal9 ;
        RECT 1112.1100 2616.1700 1112.4000 2616.2400 ;
    END
  END vid_d_2core[13]
  PIN vid_d_2core[12]
    DIRECTION INPUT ;
    USE SIGNAL ;
    PORT
      LAYER Metal8 ;
        RECT 406.0650 0.0000 406.1350 0.2900 ;
    END
  END vid_d_2core[12]
  PIN vid_d_2core[11]
    DIRECTION INPUT ;
    USE SIGNAL ;
    PORT
      LAYER Metal2 ;
        RECT 387.2650 0.0000 387.3350 0.2900 ;
    END
  END vid_d_2core[11]
  PIN vid_d_2core[10]
    DIRECTION INPUT ;
    USE SIGNAL ;
    PORT
      LAYER Metal9 ;
        RECT 0.0000 370.3700 0.2900 370.4400 ;
    END
  END vid_d_2core[10]
  PIN vid_d_2core[9]
    DIRECTION INPUT ;
    USE SIGNAL ;
    PORT
      LAYER Metal9 ;
        RECT 0.0000 938.8500 0.2900 938.9200 ;
    END
  END vid_d_2core[9]
  PIN vid_d_2core[8]
    DIRECTION INPUT ;
    USE SIGNAL ;
    PORT
      LAYER Metal9 ;
        RECT 0.0000 1507.3300 0.2900 1507.4000 ;
    END
  END vid_d_2core[8]
  PIN vid_d_2core[7]
    DIRECTION INPUT ;
    USE SIGNAL ;
    PORT
      LAYER Metal7 ;
        RECT 0.0000 2075.5250 0.2900 2075.5950 ;
    END
  END vid_d_2core[7]
  PIN vid_d_2core[6]
    DIRECTION INPUT ;
    USE SIGNAL ;
    PORT
      LAYER Metal9 ;
        RECT 0.0000 2770.0700 0.2900 2770.1400 ;
    END
  END vid_d_2core[6]
  PIN vid_d_2core[5]
    DIRECTION INPUT ;
    USE SIGNAL ;
    PORT
      LAYER Metal4 ;
        RECT 974.0650 0.0000 974.1350 0.2900 ;
    END
  END vid_d_2core[5]
  PIN vid_d_2core[4]
    DIRECTION INPUT ;
    USE SIGNAL ;
    PORT
      LAYER Metal2 ;
        RECT 1032.6650 0.0000 1032.7350 0.2900 ;
    END
  END vid_d_2core[4]
  PIN vid_d_2core[3]
    DIRECTION INPUT ;
    USE SIGNAL ;
    PORT
      LAYER Metal9 ;
        RECT 1112.1100 72.4500 1112.4000 72.5200 ;
    END
  END vid_d_2core[3]
  PIN vid_d_2core[2]
    DIRECTION INPUT ;
    USE SIGNAL ;
    PORT
      LAYER Metal9 ;
        RECT 1112.1100 1847.0500 1112.4000 1847.1200 ;
    END
  END vid_d_2core[2]
  PIN vid_d_2core[1]
    DIRECTION INPUT ;
    USE SIGNAL ;
    PORT
      LAYER Metal6 ;
        RECT 1107.2650 0.0000 1107.3350 0.2900 ;
    END
  END vid_d_2core[1]
  PIN vid_d_2core[0]
    DIRECTION INPUT ;
    USE SIGNAL ;
    PORT
      LAYER Metal9 ;
        RECT 1112.1100 206.2100 1112.4000 206.2800 ;
    END
  END vid_d_2core[0]
  PIN vid_a_2pad\[0\]
    DIRECTION OUTPUT ;
    USE SIGNAL ;
    PORT
      LAYER Metal9 ;
        RECT 1112.1100 1915.0700 1112.4000 1915.1400 ;
    END
  END vid_a_2pad\[0\]
  PIN vid_a_2pad\[1\]
    DIRECTION OUTPUT ;
    USE SIGNAL ;
    PORT
      LAYER Metal9 ;
        RECT 1112.1100 2350.9300 1112.4000 2351.0000 ;
    END
  END vid_a_2pad\[1\]
  PIN vid_a_2pad\[2\]
    DIRECTION OUTPUT ;
    USE SIGNAL ;
    PORT
      LAYER Metal9 ;
        RECT 1112.1100 2352.8300 1112.4000 2352.9000 ;
    END
  END vid_a_2pad\[2\]
  PIN vid_a_2pad\[3\]
    DIRECTION OUTPUT ;
    USE SIGNAL ;
    PORT
      LAYER Metal3 ;
        RECT 1112.1100 2353.2100 1112.4000 2353.2800 ;
    END
  END vid_a_2pad\[3\]
  PIN vid_a_2pad\[4\]
    DIRECTION OUTPUT ;
    USE SIGNAL ;
    PORT
      LAYER Metal9 ;
        RECT 1112.1100 2353.5900 1112.4000 2353.6600 ;
    END
  END vid_a_2pad\[4\]
  PIN vid_a_2pad\[5\]
    DIRECTION OUTPUT ;
    USE SIGNAL ;
    PORT
      LAYER Metal3 ;
        RECT 1112.1100 2353.9700 1112.4000 2354.0400 ;
    END
  END vid_a_2pad\[5\]
  PIN vid_a_2pad\[6\]
    DIRECTION OUTPUT ;
    USE SIGNAL ;
    PORT
      LAYER Metal9 ;
        RECT 1112.1100 2354.3500 1112.4000 2354.4200 ;
    END
  END vid_a_2pad\[6\]
  PIN vid_a_2pad\[7\]
    DIRECTION OUTPUT ;
    USE SIGNAL ;
    PORT
      LAYER Metal9 ;
        RECT 1112.1100 2356.2500 1112.4000 2356.3200 ;
    END
  END vid_a_2pad\[7\]
  PIN vid_a_2pad\[8\]
    DIRECTION OUTPUT ;
    USE SIGNAL ;
    PORT
      LAYER Metal8 ;
        RECT 1071.6650 3171.7600 1071.7350 3172.0500 ;
    END
  END vid_a_2pad\[8\]
  PIN vid_a_2pad\[9\]
    DIRECTION OUTPUT ;
    USE SIGNAL ;
    PORT
      LAYER Metal2 ;
        RECT 1106.8650 3171.7600 1106.9350 3172.0500 ;
    END
  END vid_a_2pad\[9\]
  PIN FE_OFN13186_scanmode
    DIRECTION INPUT ;
    USE SIGNAL ;
    PORT
      LAYER Metal5 ;
        RECT 1112.1100 1607.0800 1112.4000 1607.1500 ;
    END
  END FE_OFN13186_scanmode
  PIN FE_OFN13187_scanmode
    DIRECTION INPUT ;
    USE SIGNAL ;
    PORT
      LAYER Metal3 ;
        RECT 1112.1100 1607.0800 1112.4000 1607.1500 ;
    END
  END FE_OFN13187_scanmode
  PIN FE_OFN13189_scanmode
    DIRECTION INPUT ;
    USE SIGNAL ;
    PORT
      LAYER Metal9 ;
        RECT 1112.1100 1607.2700 1112.4000 1607.3400 ;
    END
  END FE_OFN13189_scanmode
  PIN FE_OFN13190_scanmode
    DIRECTION INPUT ;
    USE SIGNAL ;
    PORT
      LAYER Metal7 ;
        RECT 1112.1100 1607.2700 1112.4000 1607.3400 ;
    END
  END FE_OFN13190_scanmode
  PIN FE_OFN13192_scanmode
    DIRECTION INPUT ;
    USE SIGNAL ;
    PORT
      LAYER Metal5 ;
        RECT 1112.1100 1607.4600 1112.4000 1607.5300 ;
    END
  END FE_OFN13192_scanmode
  PIN FE_OFN13193_scanmode
    DIRECTION INPUT ;
    USE SIGNAL ;
    PORT
      LAYER Metal3 ;
        RECT 1112.1100 1607.4600 1112.4000 1607.5300 ;
    END
  END FE_OFN13193_scanmode
  PIN vid_pclk_2core__L10_N1
    DIRECTION INPUT ;
    USE SIGNAL ;
    PORT
      LAYER Metal3 ;
        RECT 1112.1100 1748.0600 1112.4000 1748.1300 ;
    END
  END vid_pclk_2core__L10_N1
  PIN vid_pclk_2core__L10_N2
    DIRECTION INPUT ;
    USE SIGNAL ;
    PORT
      LAYER Metal3 ;
        RECT 1112.1100 1002.5000 1112.4000 1002.5700 ;
    END
  END vid_pclk_2core__L10_N2
  PIN vid_pclk_2core__L10_N3
    DIRECTION INPUT ;
    USE SIGNAL ;
    PORT
      LAYER Metal3 ;
        RECT 1112.1100 937.5200 1112.4000 937.5900 ;
    END
  END vid_pclk_2core__L10_N3
  PIN clk_2core__L13_N1
    DIRECTION INPUT ;
    USE SIGNAL ;
    PORT
      LAYER Metal3 ;
        RECT 1112.1100 758.1600 1112.4000 758.2300 ;
    END
  END clk_2core__L13_N1
  PIN clk_2core__L13_N10
    DIRECTION INPUT ;
    USE SIGNAL ;
    PORT
      LAYER Metal3 ;
        RECT 1112.1100 753.4100 1112.4000 753.4800 ;
    END
  END clk_2core__L13_N10
  PIN clk_2core__L13_N11
    DIRECTION INPUT ;
    USE SIGNAL ;
    PORT
      LAYER Metal3 ;
        RECT 1112.1100 712.3700 1112.4000 712.4400 ;
    END
  END clk_2core__L13_N11
  PIN clk_2core__L13_N12
    DIRECTION INPUT ;
    USE SIGNAL ;
    PORT
      LAYER Metal3 ;
        RECT 1112.1100 708.9500 1112.4000 709.0200 ;
    END
  END clk_2core__L13_N12
  PIN clk_2core__L13_N13
    DIRECTION INPUT ;
    USE SIGNAL ;
    PORT
      LAYER Metal3 ;
        RECT 1112.1100 720.5400 1112.4000 720.6100 ;
    END
  END clk_2core__L13_N13
  PIN clk_2core__L13_N14
    DIRECTION INPUT ;
    USE SIGNAL ;
    PORT
      LAYER Metal3 ;
        RECT 1112.1100 732.8900 1112.4000 732.9600 ;
    END
  END clk_2core__L13_N14
  PIN clk_2core__L13_N15
    DIRECTION INPUT ;
    USE SIGNAL ;
    PORT
      LAYER Metal3 ;
        RECT 1112.1100 727.3800 1112.4000 727.4500 ;
    END
  END clk_2core__L13_N15
  PIN clk_2core__L13_N16
    DIRECTION INPUT ;
    USE SIGNAL ;
    PORT
      LAYER Metal3 ;
        RECT 1112.1100 749.9900 1112.4000 750.0600 ;
    END
  END clk_2core__L13_N16
  PIN clk_2core__L13_N17
    DIRECTION INPUT ;
    USE SIGNAL ;
    PORT
      LAYER Metal3 ;
        RECT 1112.1100 1322.4600 1112.4000 1322.5300 ;
    END
  END clk_2core__L13_N17
  PIN clk_2core__L13_N18
    DIRECTION INPUT ;
    USE SIGNAL ;
    PORT
      LAYER Metal3 ;
        RECT 1112.1100 1256.1500 1112.4000 1256.2200 ;
    END
  END clk_2core__L13_N18
  PIN clk_2core__L13_N19
    DIRECTION INPUT ;
    USE SIGNAL ;
    PORT
      LAYER Metal3 ;
        RECT 1112.1100 1182.2400 1112.4000 1182.3100 ;
    END
  END clk_2core__L13_N19
  PIN clk_2core__L13_N2
    DIRECTION INPUT ;
    USE SIGNAL ;
    PORT
      LAYER Metal3 ;
        RECT 1112.1100 778.6800 1112.4000 778.7500 ;
    END
  END clk_2core__L13_N2
  PIN clk_2core__L13_N20
    DIRECTION INPUT ;
    USE SIGNAL ;
    PORT
      LAYER Metal3 ;
        RECT 1112.1100 1143.2900 1112.4000 1143.3600 ;
    END
  END clk_2core__L13_N20
  PIN clk_2core__L13_N21
    DIRECTION INPUT ;
    USE SIGNAL ;
    PORT
      LAYER Metal3 ;
        RECT 1112.1100 1095.4100 1112.4000 1095.4800 ;
    END
  END clk_2core__L13_N21
  PIN clk_2core__L13_N22
    DIRECTION INPUT ;
    USE SIGNAL ;
    PORT
      LAYER Metal3 ;
        RECT 1112.1100 1366.9200 1112.4000 1366.9900 ;
    END
  END clk_2core__L13_N22
  PIN clk_2core__L13_N23
    DIRECTION INPUT ;
    USE SIGNAL ;
    PORT
      LAYER Metal3 ;
        RECT 1112.1100 1161.7200 1112.4000 1161.7900 ;
    END
  END clk_2core__L13_N23
  PIN clk_2core__L13_N24
    DIRECTION INPUT ;
    USE SIGNAL ;
    PORT
      LAYER Metal3 ;
        RECT 1112.1100 1310.8700 1112.4000 1310.9400 ;
    END
  END clk_2core__L13_N24
  PIN clk_2core__L13_N25
    DIRECTION INPUT ;
    USE SIGNAL ;
    PORT
      LAYER Metal3 ;
        RECT 1112.1100 1332.7200 1112.4000 1332.7900 ;
    END
  END clk_2core__L13_N25
  PIN clk_2core__L13_N29
    DIRECTION INPUT ;
    USE SIGNAL ;
    PORT
      LAYER Metal3 ;
        RECT 1112.1100 316.9800 1112.4000 317.0500 ;
    END
  END clk_2core__L13_N29
  PIN clk_2core__L13_N3
    DIRECTION INPUT ;
    USE SIGNAL ;
    PORT
      LAYER Metal3 ;
        RECT 1112.1100 799.2000 1112.4000 799.2700 ;
    END
  END clk_2core__L13_N3
  PIN clk_2core__L13_N30
    DIRECTION INPUT ;
    USE SIGNAL ;
    PORT
      LAYER Metal3 ;
        RECT 1112.1100 217.8000 1112.4000 217.8700 ;
    END
  END clk_2core__L13_N30
  PIN clk_2core__L13_N31
    DIRECTION INPUT ;
    USE SIGNAL ;
    PORT
      LAYER Metal3 ;
        RECT 1112.1100 224.6400 1112.4000 224.7100 ;
    END
  END clk_2core__L13_N31
  PIN clk_2core__L13_N32
    DIRECTION INPUT ;
    USE SIGNAL ;
    PORT
      LAYER Metal3 ;
        RECT 1112.1100 200.7000 1112.4000 200.7700 ;
    END
  END clk_2core__L13_N32
  PIN clk_2core__L13_N33
    DIRECTION INPUT ;
    USE SIGNAL ;
    PORT
      LAYER Metal3 ;
        RECT 1112.1100 265.6800 1112.4000 265.7500 ;
    END
  END clk_2core__L13_N33
  PIN clk_2core__L13_N34
    DIRECTION INPUT ;
    USE SIGNAL ;
    PORT
      LAYER Metal2 ;
        RECT 1051.8650 0.0000 1051.9350 0.2900 ;
    END
  END clk_2core__L13_N34
  PIN clk_2core__L13_N36
    DIRECTION INPUT ;
    USE SIGNAL ;
    PORT
      LAYER Metal3 ;
        RECT 1112.1100 238.3200 1112.4000 238.3900 ;
    END
  END clk_2core__L13_N36
  PIN clk_2core__L13_N37
    DIRECTION INPUT ;
    USE SIGNAL ;
    PORT
      LAYER Metal3 ;
        RECT 1112.1100 288.2900 1112.4000 288.3600 ;
    END
  END clk_2core__L13_N37
  PIN clk_2core__L13_N38
    DIRECTION INPUT ;
    USE SIGNAL ;
    PORT
      LAYER Metal3 ;
        RECT 1112.1100 258.8400 1112.4000 258.9100 ;
    END
  END clk_2core__L13_N38
  PIN clk_2core__L13_N39
    DIRECTION INPUT ;
    USE SIGNAL ;
    PORT
      LAYER Metal3 ;
        RECT 1112.1100 231.4800 1112.4000 231.5500 ;
    END
  END clk_2core__L13_N39
  PIN clk_2core__L13_N4
    DIRECTION INPUT ;
    USE SIGNAL ;
    PORT
      LAYER Metal3 ;
        RECT 1112.1100 768.4200 1112.4000 768.4900 ;
    END
  END clk_2core__L13_N4
  PIN clk_2core__L13_N40
    DIRECTION INPUT ;
    USE SIGNAL ;
    PORT
      LAYER Metal3 ;
        RECT 1112.1100 298.5500 1112.4000 298.6200 ;
    END
  END clk_2core__L13_N40
  PIN clk_2core__L13_N41
    DIRECTION INPUT ;
    USE SIGNAL ;
    PORT
      LAYER Metal3 ;
        RECT 1112.1100 250.6700 1112.4000 250.7400 ;
    END
  END clk_2core__L13_N41
  PIN clk_2core__L13_N42
    DIRECTION INPUT ;
    USE SIGNAL ;
    PORT
      LAYER Metal3 ;
        RECT 1112.1100 272.5200 1112.4000 272.5900 ;
    END
  END clk_2core__L13_N42
  PIN clk_2core__L13_N43
    DIRECTION INPUT ;
    USE SIGNAL ;
    PORT
      LAYER Metal3 ;
        RECT 1112.1100 303.3000 1112.4000 303.3700 ;
    END
  END clk_2core__L13_N43
  PIN clk_2core__L13_N44
    DIRECTION INPUT ;
    USE SIGNAL ;
    PORT
      LAYER Metal3 ;
        RECT 1112.1100 293.0400 1112.4000 293.1100 ;
    END
  END clk_2core__L13_N44
  PIN clk_2core__L13_N45
    DIRECTION INPUT ;
    USE SIGNAL ;
    PORT
      LAYER Metal3 ;
        RECT 1112.1100 310.1400 1112.4000 310.2100 ;
    END
  END clk_2core__L13_N45
  PIN clk_2core__L13_N46
    DIRECTION INPUT ;
    USE SIGNAL ;
    PORT
      LAYER Metal3 ;
        RECT 1112.1100 308.8100 1112.4000 308.8800 ;
    END
  END clk_2core__L13_N46
  PIN clk_2core__L13_N47
    DIRECTION INPUT ;
    USE SIGNAL ;
    PORT
      LAYER Metal3 ;
        RECT 1112.1100 281.4500 1112.4000 281.5200 ;
    END
  END clk_2core__L13_N47
  PIN clk_2core__L13_N5
    DIRECTION INPUT ;
    USE SIGNAL ;
    PORT
      LAYER Metal5 ;
        RECT 1112.1100 749.9900 1112.4000 750.0600 ;
    END
  END clk_2core__L13_N5
  PIN clk_2core__L13_N6
    DIRECTION INPUT ;
    USE SIGNAL ;
    PORT
      LAYER Metal3 ;
        RECT 1112.1100 771.8400 1112.4000 771.9100 ;
    END
  END clk_2core__L13_N6
  PIN clk_2core__L13_N7
    DIRECTION INPUT ;
    USE SIGNAL ;
    PORT
      LAYER Metal3 ;
        RECT 1112.1100 792.3600 1112.4000 792.4300 ;
    END
  END clk_2core__L13_N7
  PIN clk_2core__L13_N8
    DIRECTION INPUT ;
    USE SIGNAL ;
    PORT
      LAYER Metal3 ;
        RECT 1112.1100 806.0400 1112.4000 806.1100 ;
    END
  END clk_2core__L13_N8
  PIN clk_2core__L13_N9
    DIRECTION INPUT ;
    USE SIGNAL ;
    PORT
      LAYER Metal3 ;
        RECT 1112.1100 715.7900 1112.4000 715.8600 ;
    END
  END clk_2core__L13_N9
  PIN clk_2core__L14_N78
    DIRECTION INPUT ;
    USE SIGNAL ;
    PORT
      LAYER Metal3 ;
        RECT 1112.1100 1813.6100 1112.4000 1813.6800 ;
    END
  END clk_2core__L14_N78
  PIN clk_2core__L14_N81
    DIRECTION INPUT ;
    USE SIGNAL ;
    PORT
      LAYER Metal3 ;
        RECT 1112.1100 1890.1800 1112.4000 1890.2500 ;
    END
  END clk_2core__L14_N81
  PIN clk_2core__L14_N82
    DIRECTION INPUT ;
    USE SIGNAL ;
    PORT
      LAYER Metal3 ;
        RECT 1112.1100 1837.5500 1112.4000 1837.6200 ;
    END
  END clk_2core__L14_N82
  PIN clk_2core__L14_N83
    DIRECTION INPUT ;
    USE SIGNAL ;
    PORT
      LAYER Metal3 ;
        RECT 1112.1100 1893.6000 1112.4000 1893.6700 ;
    END
  END clk_2core__L14_N83
  PIN clk_2core__L14_N84
    DIRECTION INPUT ;
    USE SIGNAL ;
    PORT
      LAYER Metal3 ;
        RECT 1112.1100 1623.4200 1112.4000 1623.4900 ;
    END
  END clk_2core__L14_N84
  PIN clk_2core__L14_N85
    DIRECTION INPUT ;
    USE SIGNAL ;
    PORT
      LAYER Metal3 ;
        RECT 1112.1100 1676.8100 1112.4000 1676.8800 ;
    END
  END clk_2core__L14_N85
  PIN clk_2core__L14_N87
    DIRECTION INPUT ;
    USE SIGNAL ;
    PORT
      LAYER Metal3 ;
        RECT 1112.1100 1674.7200 1112.4000 1674.7900 ;
    END
  END clk_2core__L14_N87
  PIN clk_2core__L14_N88
    DIRECTION INPUT ;
    USE SIGNAL ;
    PORT
      LAYER Metal3 ;
        RECT 1112.1100 1664.4600 1112.4000 1664.5300 ;
    END
  END clk_2core__L14_N88
  PIN clk_2core__L14_N89
    DIRECTION INPUT ;
    USE SIGNAL ;
    PORT
      LAYER Metal3 ;
        RECT 1112.1100 1667.8800 1112.4000 1667.9500 ;
    END
  END clk_2core__L14_N89
  PIN clk_2core__L14_N90
    DIRECTION INPUT ;
    USE SIGNAL ;
    PORT
      LAYER Metal3 ;
        RECT 1112.1100 1671.3000 1112.4000 1671.3700 ;
    END
  END clk_2core__L14_N90
  PIN clk_2core__L14_N91
    DIRECTION INPUT ;
    USE SIGNAL ;
    PORT
      LAYER Metal3 ;
        RECT 1112.1100 1399.7900 1112.4000 1399.8600 ;
    END
  END clk_2core__L14_N91
  PIN clk_2core__L14_N94
    DIRECTION INPUT ;
    USE SIGNAL ;
    PORT
      LAYER Metal3 ;
        RECT 1112.1100 1492.1300 1112.4000 1492.2000 ;
    END
  END clk_2core__L14_N94
  PIN clk_2core__L14_N97
    DIRECTION INPUT ;
    USE SIGNAL ;
    PORT
      LAYER Metal3 ;
        RECT 1112.1100 1410.0500 1112.4000 1410.1200 ;
    END
  END clk_2core__L14_N97
  PIN clk_2core__L15_N0
    DIRECTION INPUT ;
    USE SIGNAL ;
    PORT
      LAYER Metal3 ;
        RECT 1112.1100 394.3100 1112.4000 394.3800 ;
    END
  END clk_2core__L15_N0
  PIN clk_2core__L15_N1
    DIRECTION INPUT ;
    USE SIGNAL ;
    PORT
      LAYER Metal3 ;
        RECT 1112.1100 378.5400 1112.4000 378.6100 ;
    END
  END clk_2core__L15_N1
  PIN clk_2core__L15_N10
    DIRECTION INPUT ;
    USE SIGNAL ;
    PORT
      LAYER Metal3 ;
        RECT 1112.1100 494.8200 1112.4000 494.8900 ;
    END
  END clk_2core__L15_N10
  PIN clk_2core__L15_N100
    DIRECTION INPUT ;
    USE SIGNAL ;
    PORT
      LAYER Metal3 ;
        RECT 1112.1100 1562.4300 1112.4000 1562.5000 ;
    END
  END clk_2core__L15_N100
  PIN clk_2core__L15_N101
    DIRECTION INPUT ;
    USE SIGNAL ;
    PORT
      LAYER Metal3 ;
        RECT 1112.1100 1515.5000 1112.4000 1515.5700 ;
    END
  END clk_2core__L15_N101
  PIN clk_2core__L15_N11
    DIRECTION INPUT ;
    USE SIGNAL ;
    PORT
      LAYER Metal3 ;
        RECT 1112.1100 514.0100 1112.4000 514.0800 ;
    END
  END clk_2core__L15_N11
  PIN clk_2core__L15_N12
    DIRECTION INPUT ;
    USE SIGNAL ;
    PORT
      LAYER Metal3 ;
        RECT 1112.1100 549.5400 1112.4000 549.6100 ;
    END
  END clk_2core__L15_N12
  PIN clk_2core__L15_N128
    DIRECTION INPUT ;
    USE SIGNAL ;
    PORT
      LAYER Metal3 ;
        RECT 1112.1100 762.1500 1112.4000 762.2200 ;
    END
  END clk_2core__L15_N128
  PIN clk_2core__L15_N129
    DIRECTION INPUT ;
    USE SIGNAL ;
    PORT
      LAYER Metal3 ;
        RECT 1112.1100 577.4700 1112.4000 577.5400 ;
    END
  END clk_2core__L15_N129
  PIN clk_2core__L15_N13
    DIRECTION INPUT ;
    USE SIGNAL ;
    PORT
      LAYER Metal3 ;
        RECT 1112.1100 539.2800 1112.4000 539.3500 ;
    END
  END clk_2core__L15_N13
  PIN clk_2core__L15_N14
    DIRECTION INPUT ;
    USE SIGNAL ;
    PORT
      LAYER Metal3 ;
        RECT 1112.1100 544.7900 1112.4000 544.8600 ;
    END
  END clk_2core__L15_N14
  PIN clk_2core__L15_N15
    DIRECTION INPUT ;
    USE SIGNAL ;
    PORT
      LAYER Metal3 ;
        RECT 1112.1100 487.9800 1112.4000 488.0500 ;
    END
  END clk_2core__L15_N15
  PIN clk_2core__L15_N16
    DIRECTION INPUT ;
    USE SIGNAL ;
    PORT
      LAYER Metal3 ;
        RECT 1112.1100 503.7500 1112.4000 503.8200 ;
    END
  END clk_2core__L15_N16
  PIN clk_2core__L15_N167
    DIRECTION INPUT ;
    USE SIGNAL ;
    PORT
      LAYER Metal3 ;
        RECT 1112.1100 1864.9100 1112.4000 1864.9800 ;
    END
  END clk_2core__L15_N167
  PIN clk_2core__L15_N168
    DIRECTION INPUT ;
    USE SIGNAL ;
    PORT
      LAYER Metal3 ;
        RECT 1112.1100 1524.2400 1112.4000 1524.3100 ;
    END
  END clk_2core__L15_N168
  PIN clk_2core__L15_N169
    DIRECTION INPUT ;
    USE SIGNAL ;
    PORT
      LAYER Metal3 ;
        RECT 1112.1100 1543.4300 1112.4000 1543.5000 ;
    END
  END clk_2core__L15_N169
  PIN clk_2core__L15_N17
    DIRECTION INPUT ;
    USE SIGNAL ;
    PORT
      LAYER Metal3 ;
        RECT 1112.1100 552.9600 1112.4000 553.0300 ;
    END
  END clk_2core__L15_N17
  PIN clk_2core__L15_N170
    DIRECTION INPUT ;
    USE SIGNAL ;
    PORT
      LAYER Metal3 ;
        RECT 1112.1100 1517.4000 1112.4000 1517.4700 ;
    END
  END clk_2core__L15_N170
  PIN clk_2core__L15_N171
    DIRECTION INPUT ;
    USE SIGNAL ;
    PORT
      LAYER Metal5 ;
        RECT 1112.1100 1517.4000 1112.4000 1517.4700 ;
    END
  END clk_2core__L15_N171
  PIN clk_2core__L15_N172
    DIRECTION INPUT ;
    USE SIGNAL ;
    PORT
      LAYER Metal3 ;
        RECT 1112.1100 1868.3300 1112.4000 1868.4000 ;
    END
  END clk_2core__L15_N172
  PIN clk_2core__L15_N173
    DIRECTION INPUT ;
    USE SIGNAL ;
    PORT
      LAYER Metal7 ;
        RECT 1112.1100 2600.2100 1112.4000 2600.2800 ;
    END
  END clk_2core__L15_N173
  PIN clk_2core__L15_N174
    DIRECTION INPUT ;
    USE SIGNAL ;
    PORT
      LAYER Metal3 ;
        RECT 1112.1100 2796.6700 1112.4000 2796.7400 ;
    END
  END clk_2core__L15_N174
  PIN clk_2core__L15_N175
    DIRECTION INPUT ;
    USE SIGNAL ;
    PORT
      LAYER Metal7 ;
        RECT 1112.1100 2643.2450 1112.4000 2643.3150 ;
    END
  END clk_2core__L15_N175
  PIN clk_2core__L15_N176
    DIRECTION INPUT ;
    USE SIGNAL ;
    PORT
      LAYER Metal7 ;
        RECT 1112.1100 2637.8300 1112.4000 2637.9000 ;
    END
  END clk_2core__L15_N176
  PIN clk_2core__L15_N177
    DIRECTION INPUT ;
    USE SIGNAL ;
    PORT
      LAYER Metal7 ;
        RECT 1112.1100 2797.1450 1112.4000 2797.2150 ;
    END
  END clk_2core__L15_N177
  PIN clk_2core__L15_N178
    DIRECTION INPUT ;
    USE SIGNAL ;
    PORT
      LAYER Metal7 ;
        RECT 1112.1100 2620.7300 1112.4000 2620.8000 ;
    END
  END clk_2core__L15_N178
  PIN clk_2core__L15_N179
    DIRECTION INPUT ;
    USE SIGNAL ;
    PORT
      LAYER Metal3 ;
        RECT 1112.1100 2608.5700 1112.4000 2608.6400 ;
    END
  END clk_2core__L15_N179
  PIN clk_2core__L15_N18
    DIRECTION INPUT ;
    USE SIGNAL ;
    PORT
      LAYER Metal3 ;
        RECT 1112.1100 371.7000 1112.4000 371.7700 ;
    END
  END clk_2core__L15_N18
  PIN clk_2core__L15_N180
    DIRECTION INPUT ;
    USE SIGNAL ;
    PORT
      LAYER Metal3 ;
        RECT 1112.1100 1438.7400 1112.4000 1438.8100 ;
    END
  END clk_2core__L15_N180
  PIN clk_2core__L15_N181
    DIRECTION INPUT ;
    USE SIGNAL ;
    PORT
      LAYER Metal3 ;
        RECT 1112.1100 1526.3300 1112.4000 1526.4000 ;
    END
  END clk_2core__L15_N181
  PIN clk_2core__L15_N182
    DIRECTION INPUT ;
    USE SIGNAL ;
    PORT
      LAYER Metal3 ;
        RECT 1112.1100 1498.9700 1112.4000 1499.0400 ;
    END
  END clk_2core__L15_N182
  PIN clk_2core__L15_N183
    DIRECTION INPUT ;
    USE SIGNAL ;
    PORT
      LAYER Metal3 ;
        RECT 1112.1100 1507.1400 1112.4000 1507.2100 ;
    END
  END clk_2core__L15_N183
  PIN clk_2core__L15_N19
    DIRECTION INPUT ;
    USE SIGNAL ;
    PORT
      LAYER Metal3 ;
        RECT 1112.1100 484.5600 1112.4000 484.6300 ;
    END
  END clk_2core__L15_N19
  PIN clk_2core__L15_N2
    DIRECTION INPUT ;
    USE SIGNAL ;
    PORT
      LAYER Metal3 ;
        RECT 1112.1100 453.7800 1112.4000 453.8500 ;
    END
  END clk_2core__L15_N2
  PIN clk_2core__L15_N20
    DIRECTION INPUT ;
    USE SIGNAL ;
    PORT
      LAYER Metal3 ;
        RECT 1112.1100 508.5000 1112.4000 508.5700 ;
    END
  END clk_2core__L15_N20
  PIN clk_2core__L15_N21
    DIRECTION INPUT ;
    USE SIGNAL ;
    PORT
      LAYER Metal3 ;
        RECT 1112.1100 412.7400 1112.4000 412.8100 ;
    END
  END clk_2core__L15_N21
  PIN clk_2core__L15_N22
    DIRECTION INPUT ;
    USE SIGNAL ;
    PORT
      LAYER Metal3 ;
        RECT 1112.1100 498.2400 1112.4000 498.3100 ;
    END
  END clk_2core__L15_N22
  PIN clk_2core__L15_N23
    DIRECTION INPUT ;
    USE SIGNAL ;
    PORT
      LAYER Metal3 ;
        RECT 1112.1100 429.8400 1112.4000 429.9100 ;
    END
  END clk_2core__L15_N23
  PIN clk_2core__L15_N24
    DIRECTION INPUT ;
    USE SIGNAL ;
    PORT
      LAYER Metal3 ;
        RECT 1112.1100 405.9000 1112.4000 405.9700 ;
    END
  END clk_2core__L15_N24
  PIN clk_2core__L15_N25
    DIRECTION INPUT ;
    USE SIGNAL ;
    PORT
      LAYER Metal3 ;
        RECT 1112.1100 607.6800 1112.4000 607.7500 ;
    END
  END clk_2core__L15_N25
  PIN clk_2core__L15_N26
    DIRECTION INPUT ;
    USE SIGNAL ;
    PORT
      LAYER Metal3 ;
        RECT 1112.1100 650.8100 1112.4000 650.8800 ;
    END
  END clk_2core__L15_N26
  PIN clk_2core__L15_N27
    DIRECTION INPUT ;
    USE SIGNAL ;
    PORT
      LAYER Metal3 ;
        RECT 1112.1100 590.5800 1112.4000 590.6500 ;
    END
  END clk_2core__L15_N27
  PIN clk_2core__L15_N28
    DIRECTION INPUT ;
    USE SIGNAL ;
    PORT
      LAYER Metal3 ;
        RECT 1112.1100 600.8400 1112.4000 600.9100 ;
    END
  END clk_2core__L15_N28
  PIN clk_2core__L15_N29
    DIRECTION INPUT ;
    USE SIGNAL ;
    PORT
      LAYER Metal3 ;
        RECT 1112.1100 621.3600 1112.4000 621.4300 ;
    END
  END clk_2core__L15_N29
  PIN clk_2core__L15_N3
    DIRECTION INPUT ;
    USE SIGNAL ;
    PORT
      LAYER Metal3 ;
        RECT 1112.1100 425.0900 1112.4000 425.1600 ;
    END
  END clk_2core__L15_N3
  PIN clk_2core__L15_N30
    DIRECTION INPUT ;
    USE SIGNAL ;
    PORT
      LAYER Metal3 ;
        RECT 1112.1100 635.0400 1112.4000 635.1100 ;
    END
  END clk_2core__L15_N30
  PIN clk_2core__L15_N31
    DIRECTION INPUT ;
    USE SIGNAL ;
    PORT
      LAYER Metal3 ;
        RECT 1112.1100 678.1700 1112.4000 678.2400 ;
    END
  END clk_2core__L15_N31
  PIN clk_2core__L15_N32
    DIRECTION INPUT ;
    USE SIGNAL ;
    PORT
      LAYER Metal3 ;
        RECT 1112.1100 657.6500 1112.4000 657.7200 ;
    END
  END clk_2core__L15_N32
  PIN clk_2core__L15_N33
    DIRECTION INPUT ;
    USE SIGNAL ;
    PORT
      LAYER Metal3 ;
        RECT 1112.1100 674.7500 1112.4000 674.8200 ;
    END
  END clk_2core__L15_N33
  PIN clk_2core__L15_N34
    DIRECTION INPUT ;
    USE SIGNAL ;
    PORT
      LAYER Metal3 ;
        RECT 1112.1100 531.1100 1112.4000 531.1800 ;
    END
  END clk_2core__L15_N34
  PIN clk_2core__L15_N35
    DIRECTION INPUT ;
    USE SIGNAL ;
    PORT
      LAYER Metal3 ;
        RECT 1112.1100 534.5300 1112.4000 534.6000 ;
    END
  END clk_2core__L15_N35
  PIN clk_2core__L15_N36
    DIRECTION INPUT ;
    USE SIGNAL ;
    PORT
      LAYER Metal3 ;
        RECT 1112.1100 570.0600 1112.4000 570.1300 ;
    END
  END clk_2core__L15_N36
  PIN clk_2core__L15_N37
    DIRECTION INPUT ;
    USE SIGNAL ;
    PORT
      LAYER Metal3 ;
        RECT 1112.1100 517.4300 1112.4000 517.5000 ;
    END
  END clk_2core__L15_N37
  PIN clk_2core__L15_N38
    DIRECTION INPUT ;
    USE SIGNAL ;
    PORT
      LAYER Metal3 ;
        RECT 1112.1100 477.7200 1112.4000 477.7900 ;
    END
  END clk_2core__L15_N38
  PIN clk_2core__L15_N39
    DIRECTION INPUT ;
    USE SIGNAL ;
    PORT
      LAYER Metal3 ;
        RECT 1112.1100 481.1400 1112.4000 481.2100 ;
    END
  END clk_2core__L15_N39
  PIN clk_2core__L15_N4
    DIRECTION INPUT ;
    USE SIGNAL ;
    PORT
      LAYER Metal3 ;
        RECT 1112.1100 399.0600 1112.4000 399.1300 ;
    END
  END clk_2core__L15_N4
  PIN clk_2core__L15_N40
    DIRECTION INPUT ;
    USE SIGNAL ;
    PORT
      LAYER Metal3 ;
        RECT 1112.1100 474.3000 1112.4000 474.3700 ;
    END
  END clk_2core__L15_N40
  PIN clk_2core__L15_N41
    DIRECTION INPUT ;
    USE SIGNAL ;
    PORT
      LAYER Metal3 ;
        RECT 1112.1100 518.7600 1112.4000 518.8300 ;
    END
  END clk_2core__L15_N41
  PIN clk_2core__L15_N42
    DIRECTION INPUT ;
    USE SIGNAL ;
    PORT
      LAYER Metal3 ;
        RECT 1112.1100 616.6100 1112.4000 616.6800 ;
    END
  END clk_2core__L15_N42
  PIN clk_2core__L15_N5
    DIRECTION INPUT ;
    USE SIGNAL ;
    PORT
      LAYER Metal3 ;
        RECT 1112.1100 387.4700 1112.4000 387.5400 ;
    END
  END clk_2core__L15_N5
  PIN clk_2core__L15_N6
    DIRECTION INPUT ;
    USE SIGNAL ;
    PORT
      LAYER Metal3 ;
        RECT 1112.1100 381.9600 1112.4000 382.0300 ;
    END
  END clk_2core__L15_N6
  PIN clk_2core__L15_N61
    DIRECTION INPUT ;
    USE SIGNAL ;
    PORT
      LAYER Metal2 ;
        RECT 800.8650 0.0000 800.9350 0.2900 ;
    END
  END clk_2core__L15_N61
  PIN clk_2core__L15_N62
    DIRECTION INPUT ;
    USE SIGNAL ;
    PORT
      LAYER Metal2 ;
        RECT 871.8650 0.0000 871.9350 0.2900 ;
    END
  END clk_2core__L15_N62
  PIN clk_2core__L15_N63
    DIRECTION INPUT ;
    USE SIGNAL ;
    PORT
      LAYER Metal2 ;
        RECT 898.8650 0.0000 898.9350 0.2900 ;
    END
  END clk_2core__L15_N63
  PIN clk_2core__L15_N64
    DIRECTION INPUT ;
    USE SIGNAL ;
    PORT
      LAYER Metal2 ;
        RECT 865.4650 0.0000 865.5350 0.2900 ;
    END
  END clk_2core__L15_N64
  PIN clk_2core__L15_N65
    DIRECTION INPUT ;
    USE SIGNAL ;
    PORT
      LAYER Metal2 ;
        RECT 835.0650 0.0000 835.1350 0.2900 ;
    END
  END clk_2core__L15_N65
  PIN clk_2core__L15_N66
    DIRECTION INPUT ;
    USE SIGNAL ;
    PORT
      LAYER Metal2 ;
        RECT 819.2650 0.0000 819.3350 0.2900 ;
    END
  END clk_2core__L15_N66
  PIN clk_2core__L15_N67
    DIRECTION INPUT ;
    USE SIGNAL ;
    PORT
      LAYER Metal2 ;
        RECT 905.0650 0.0000 905.1350 0.2900 ;
    END
  END clk_2core__L15_N67
  PIN clk_2core__L15_N68
    DIRECTION INPUT ;
    USE SIGNAL ;
    PORT
      LAYER Metal2 ;
        RECT 916.0650 0.0000 916.1350 0.2900 ;
    END
  END clk_2core__L15_N68
  PIN clk_2core__L15_N69
    DIRECTION INPUT ;
    USE SIGNAL ;
    PORT
      LAYER Metal2 ;
        RECT 856.2650 0.0000 856.3350 0.2900 ;
    END
  END clk_2core__L15_N69
  PIN clk_2core__L15_N7
    DIRECTION INPUT ;
    USE SIGNAL ;
    PORT
      LAYER Metal3 ;
        RECT 1112.1100 368.2800 1112.4000 368.3500 ;
    END
  END clk_2core__L15_N7
  PIN clk_2core__L15_N70
    DIRECTION INPUT ;
    USE SIGNAL ;
    PORT
      LAYER Metal2 ;
        RECT 576.6650 0.0000 576.7350 0.2900 ;
    END
  END clk_2core__L15_N70
  PIN clk_2core__L15_N71
    DIRECTION INPUT ;
    USE SIGNAL ;
    PORT
      LAYER Metal2 ;
        RECT 600.6650 0.0000 600.7350 0.2900 ;
    END
  END clk_2core__L15_N71
  PIN clk_2core__L15_N72
    DIRECTION INPUT ;
    USE SIGNAL ;
    PORT
      LAYER Metal2 ;
        RECT 603.0650 0.0000 603.1350 0.2900 ;
    END
  END clk_2core__L15_N72
  PIN clk_2core__L15_N73
    DIRECTION INPUT ;
    USE SIGNAL ;
    PORT
      LAYER Metal2 ;
        RECT 750.4650 0.0000 750.5350 0.2900 ;
    END
  END clk_2core__L15_N73
  PIN clk_2core__L15_N74
    DIRECTION INPUT ;
    USE SIGNAL ;
    PORT
      LAYER Metal2 ;
        RECT 617.2650 0.0000 617.3350 0.2900 ;
    END
  END clk_2core__L15_N74
  PIN clk_2core__L15_N75
    DIRECTION INPUT ;
    USE SIGNAL ;
    PORT
      LAYER Metal2 ;
        RECT 633.0650 0.0000 633.1350 0.2900 ;
    END
  END clk_2core__L15_N75
  PIN clk_2core__L15_N76
    DIRECTION INPUT ;
    USE SIGNAL ;
    PORT
      LAYER Metal2 ;
        RECT 745.2650 0.0000 745.3350 0.2900 ;
    END
  END clk_2core__L15_N76
  PIN clk_2core__L15_N8
    DIRECTION INPUT ;
    USE SIGNAL ;
    PORT
      LAYER Metal3 ;
        RECT 1112.1100 375.1200 1112.4000 375.1900 ;
    END
  END clk_2core__L15_N8
  PIN clk_2core__L15_N85
    DIRECTION INPUT ;
    USE SIGNAL ;
    PORT
      LAYER Metal7 ;
        RECT 1112.1100 3009.1850 1112.4000 3009.2550 ;
    END
  END clk_2core__L15_N85
  PIN clk_2core__L15_N86
    DIRECTION INPUT ;
    USE SIGNAL ;
    PORT
      LAYER Metal7 ;
        RECT 1112.1100 2835.6200 1112.4000 2835.6900 ;
    END
  END clk_2core__L15_N86
  PIN clk_2core__L15_N87
    DIRECTION INPUT ;
    USE SIGNAL ;
    PORT
      LAYER Metal3 ;
        RECT 1112.1100 3013.4600 1112.4000 3013.5300 ;
    END
  END clk_2core__L15_N87
  PIN clk_2core__L15_N88
    DIRECTION INPUT ;
    USE SIGNAL ;
    PORT
      LAYER Metal7 ;
        RECT 1112.1100 2438.0450 1112.4000 2438.1150 ;
    END
  END clk_2core__L15_N88
  PIN clk_2core__L15_N89
    DIRECTION INPUT ;
    USE SIGNAL ;
    PORT
      LAYER Metal7 ;
        RECT 1112.1100 2660.3450 1112.4000 2660.4150 ;
    END
  END clk_2core__L15_N89
  PIN clk_2core__L15_N9
    DIRECTION INPUT ;
    USE SIGNAL ;
    PORT
      LAYER Metal3 ;
        RECT 1112.1100 524.2700 1112.4000 524.3400 ;
    END
  END clk_2core__L15_N9
  PIN clk_2core__L15_N90
    DIRECTION INPUT ;
    USE SIGNAL ;
    PORT
      LAYER Metal7 ;
        RECT 1112.1100 2739.0050 1112.4000 2739.0750 ;
    END
  END clk_2core__L15_N90
  PIN clk_2core__L15_N91
    DIRECTION INPUT ;
    USE SIGNAL ;
    PORT
      LAYER Metal7 ;
        RECT 1112.1100 2760.3800 1112.4000 2760.4500 ;
    END
  END clk_2core__L15_N91
  PIN clk_2core__L15_N92
    DIRECTION INPUT ;
    USE SIGNAL ;
    PORT
      LAYER Metal7 ;
        RECT 1112.1100 2815.1000 1112.4000 2815.1700 ;
    END
  END clk_2core__L15_N92
  PIN clk_2core__L15_N93
    DIRECTION INPUT ;
    USE SIGNAL ;
    PORT
      LAYER Metal7 ;
        RECT 1112.1100 2408.1200 1112.4000 2408.1900 ;
    END
  END clk_2core__L15_N93
  PIN clk_2core__L15_N94
    DIRECTION INPUT ;
    USE SIGNAL ;
    PORT
      LAYER Metal7 ;
        RECT 1112.1100 2497.0400 1112.4000 2497.1100 ;
    END
  END clk_2core__L15_N94
  PIN clk_2core__L15_N95
    DIRECTION INPUT ;
    USE SIGNAL ;
    PORT
      LAYER Metal7 ;
        RECT 1112.1100 2661.2000 1112.4000 2661.2700 ;
    END
  END clk_2core__L15_N95
  PIN clk_2core__L15_N96
    DIRECTION INPUT ;
    USE SIGNAL ;
    PORT
      LAYER Metal3 ;
        RECT 1112.1100 1757.3700 1112.4000 1757.4400 ;
    END
  END clk_2core__L15_N96
  PIN clk_2core__L15_N97
    DIRECTION INPUT ;
    USE SIGNAL ;
    PORT
      LAYER Metal3 ;
        RECT 1112.1100 1905.9500 1112.4000 1906.0200 ;
    END
  END clk_2core__L15_N97
  PIN clk_2core__L15_N98
    DIRECTION INPUT ;
    USE SIGNAL ;
    PORT
      LAYER Metal3 ;
        RECT 1112.1100 1907.2800 1112.4000 1907.3500 ;
    END
  END clk_2core__L15_N98
  PIN clk_2core__L15_N99
    DIRECTION INPUT ;
    USE SIGNAL ;
    PORT
      LAYER Metal3 ;
        RECT 1112.1100 1237.5300 1112.4000 1237.6000 ;
    END
  END clk_2core__L15_N99
  PIN clk_2core__L16_N100
    DIRECTION INPUT ;
    USE SIGNAL ;
    PORT
      LAYER Metal3 ;
        RECT 1112.1100 864.1800 1112.4000 864.2500 ;
    END
  END clk_2core__L16_N100
  PIN clk_2core__L16_N101
    DIRECTION INPUT ;
    USE SIGNAL ;
    PORT
      LAYER Metal3 ;
        RECT 1112.1100 890.2100 1112.4000 890.2800 ;
    END
  END clk_2core__L16_N101
  PIN clk_2core__L16_N102
    DIRECTION INPUT ;
    USE SIGNAL ;
    PORT
      LAYER Metal3 ;
        RECT 1112.1100 939.4200 1112.4000 939.4900 ;
    END
  END clk_2core__L16_N102
  PIN clk_2core__L16_N103
    DIRECTION INPUT ;
    USE SIGNAL ;
    PORT
      LAYER Metal3 ;
        RECT 1112.1100 884.7000 1112.4000 884.7700 ;
    END
  END clk_2core__L16_N103
  PIN clk_2core__L16_N104
    DIRECTION INPUT ;
    USE SIGNAL ;
    PORT
      LAYER Metal3 ;
        RECT 1112.1100 927.8300 1112.4000 927.9000 ;
    END
  END clk_2core__L16_N104
  PIN clk_2core__L16_N105
    DIRECTION INPUT ;
    USE SIGNAL ;
    PORT
      LAYER Metal3 ;
        RECT 1112.1100 941.5100 1112.4000 941.5800 ;
    END
  END clk_2core__L16_N105
  PIN clk_2core__L16_N106
    DIRECTION INPUT ;
    USE SIGNAL ;
    PORT
      LAYER Metal3 ;
        RECT 1112.1100 999.6500 1112.4000 999.7200 ;
    END
  END clk_2core__L16_N106
  PIN clk_2core__L16_N107
    DIRECTION INPUT ;
    USE SIGNAL ;
    PORT
      LAYER Metal3 ;
        RECT 1112.1100 1064.6300 1112.4000 1064.7000 ;
    END
  END clk_2core__L16_N107
  PIN clk_2core__L16_N108
    DIRECTION INPUT ;
    USE SIGNAL ;
    PORT
      LAYER Metal3 ;
        RECT 1112.1100 1062.5400 1112.4000 1062.6100 ;
    END
  END clk_2core__L16_N108
  PIN clk_2core__L16_N109
    DIRECTION INPUT ;
    USE SIGNAL ;
    PORT
      LAYER Metal3 ;
        RECT 1112.1100 989.3900 1112.4000 989.4600 ;
    END
  END clk_2core__L16_N109
  PIN clk_2core__L16_N11
    DIRECTION INPUT ;
    USE SIGNAL ;
    PORT
      LAYER Metal3 ;
        RECT 1112.1100 2312.9300 1112.4000 2313.0000 ;
    END
  END clk_2core__L16_N11
  PIN clk_2core__L16_N110
    DIRECTION INPUT ;
    USE SIGNAL ;
    PORT
      LAYER Metal3 ;
        RECT 1112.1100 1011.2400 1112.4000 1011.3100 ;
    END
  END clk_2core__L16_N110
  PIN clk_2core__L16_N111
    DIRECTION INPUT ;
    USE SIGNAL ;
    PORT
      LAYER Metal3 ;
        RECT 1112.1100 1044.1100 1112.4000 1044.1800 ;
    END
  END clk_2core__L16_N111
  PIN clk_2core__L16_N112
    DIRECTION INPUT ;
    USE SIGNAL ;
    PORT
      LAYER Metal3 ;
        RECT 1112.1100 955.1900 1112.4000 955.2600 ;
    END
  END clk_2core__L16_N112
  PIN clk_2core__L16_N113
    DIRECTION INPUT ;
    USE SIGNAL ;
    PORT
      LAYER Metal3 ;
        RECT 1112.1100 1055.7000 1112.4000 1055.7700 ;
    END
  END clk_2core__L16_N113
  PIN clk_2core__L16_N114
    DIRECTION INPUT ;
    USE SIGNAL ;
    PORT
      LAYER Metal3 ;
        RECT 1112.1100 1050.9500 1112.4000 1051.0200 ;
    END
  END clk_2core__L16_N114
  PIN clk_2core__L16_N115
    DIRECTION INPUT ;
    USE SIGNAL ;
    PORT
      LAYER Metal5 ;
        RECT 1112.1100 941.5100 1112.4000 941.5800 ;
    END
  END clk_2core__L16_N115
  PIN clk_2core__L16_N116
    DIRECTION INPUT ;
    USE SIGNAL ;
    PORT
      LAYER Metal3 ;
        RECT 1112.1100 1290.3500 1112.4000 1290.4200 ;
    END
  END clk_2core__L16_N116
  PIN clk_2core__L16_N117
    DIRECTION INPUT ;
    USE SIGNAL ;
    PORT
      LAYER Metal3 ;
        RECT 1112.1100 1300.6100 1112.4000 1300.6800 ;
    END
  END clk_2core__L16_N117
  PIN clk_2core__L16_N118
    DIRECTION INPUT ;
    USE SIGNAL ;
    PORT
      LAYER Metal3 ;
        RECT 1112.1100 1304.0300 1112.4000 1304.1000 ;
    END
  END clk_2core__L16_N118
  PIN clk_2core__L16_N119
    DIRECTION INPUT ;
    USE SIGNAL ;
    PORT
      LAYER Metal3 ;
        RECT 1112.1100 1293.7700 1112.4000 1293.8400 ;
    END
  END clk_2core__L16_N119
  PIN clk_2core__L16_N12
    DIRECTION INPUT ;
    USE SIGNAL ;
    PORT
      LAYER Metal3 ;
        RECT 1112.1100 2323.1900 1112.4000 2323.2600 ;
    END
  END clk_2core__L16_N12
  PIN clk_2core__L16_N120
    DIRECTION INPUT ;
    USE SIGNAL ;
    PORT
      LAYER Metal3 ;
        RECT 1112.1100 1230.1200 1112.4000 1230.1900 ;
    END
  END clk_2core__L16_N120
  PIN clk_2core__L16_N121
    DIRECTION INPUT ;
    USE SIGNAL ;
    PORT
      LAYER Metal3 ;
        RECT 1112.1100 828.6500 1112.4000 828.7200 ;
    END
  END clk_2core__L16_N121
  PIN clk_2core__L16_N122
    DIRECTION INPUT ;
    USE SIGNAL ;
    PORT
      LAYER Metal3 ;
        RECT 1112.1100 1250.6400 1112.4000 1250.7100 ;
    END
  END clk_2core__L16_N122
  PIN clk_2core__L16_N123
    DIRECTION INPUT ;
    USE SIGNAL ;
    PORT
      LAYER Metal3 ;
        RECT 1112.1100 816.3000 1112.4000 816.3700 ;
    END
  END clk_2core__L16_N123
  PIN clk_2core__L16_N124
    DIRECTION INPUT ;
    USE SIGNAL ;
    PORT
      LAYER Metal3 ;
        RECT 1112.1100 1024.9200 1112.4000 1024.9900 ;
    END
  END clk_2core__L16_N124
  PIN clk_2core__L16_N125
    DIRECTION INPUT ;
    USE SIGNAL ;
    PORT
      LAYER Metal3 ;
        RECT 1112.1100 982.5500 1112.4000 982.6200 ;
    END
  END clk_2core__L16_N125
  PIN clk_2core__L16_N126
    DIRECTION INPUT ;
    USE SIGNAL ;
    PORT
      LAYER Metal3 ;
        RECT 1112.1100 949.6800 1112.4000 949.7500 ;
    END
  END clk_2core__L16_N126
  PIN clk_2core__L16_N127
    DIRECTION INPUT ;
    USE SIGNAL ;
    PORT
      LAYER Metal3 ;
        RECT 1112.1100 994.1400 1112.4000 994.2100 ;
    END
  END clk_2core__L16_N127
  PIN clk_2core__L16_N128
    DIRECTION INPUT ;
    USE SIGNAL ;
    PORT
      LAYER Metal3 ;
        RECT 1112.1100 953.1000 1112.4000 953.1700 ;
    END
  END clk_2core__L16_N128
  PIN clk_2core__L16_N129
    DIRECTION INPUT ;
    USE SIGNAL ;
    PORT
      LAYER Metal3 ;
        RECT 1112.1100 936.0000 1112.4000 936.0700 ;
    END
  END clk_2core__L16_N129
  PIN clk_2core__L16_N13
    DIRECTION INPUT ;
    USE SIGNAL ;
    PORT
      LAYER Metal3 ;
        RECT 1112.1100 2275.3100 1112.4000 2275.3800 ;
    END
  END clk_2core__L16_N13
  PIN clk_2core__L16_N130
    DIRECTION INPUT ;
    USE SIGNAL ;
    PORT
      LAYER Metal3 ;
        RECT 1112.1100 1038.6000 1112.4000 1038.6700 ;
    END
  END clk_2core__L16_N130
  PIN clk_2core__L16_N131
    DIRECTION INPUT ;
    USE SIGNAL ;
    PORT
      LAYER Metal3 ;
        RECT 1112.1100 1035.1800 1112.4000 1035.2500 ;
    END
  END clk_2core__L16_N131
  PIN clk_2core__L16_N132
    DIRECTION INPUT ;
    USE SIGNAL ;
    PORT
      LAYER Metal3 ;
        RECT 1112.1100 840.2400 1112.4000 840.3100 ;
    END
  END clk_2core__L16_N132
  PIN clk_2core__L16_N133
    DIRECTION INPUT ;
    USE SIGNAL ;
    PORT
      LAYER Metal3 ;
        RECT 1112.1100 852.5900 1112.4000 852.6600 ;
    END
  END clk_2core__L16_N133
  PIN clk_2core__L16_N134
    DIRECTION INPUT ;
    USE SIGNAL ;
    PORT
      LAYER Metal3 ;
        RECT 1112.1100 897.0500 1112.4000 897.1200 ;
    END
  END clk_2core__L16_N134
  PIN clk_2core__L16_N135
    DIRECTION INPUT ;
    USE SIGNAL ;
    PORT
      LAYER Metal3 ;
        RECT 1112.1100 874.4400 1112.4000 874.5100 ;
    END
  END clk_2core__L16_N135
  PIN clk_2core__L16_N136
    DIRECTION INPUT ;
    USE SIGNAL ;
    PORT
      LAYER Metal3 ;
        RECT 1112.1100 833.4000 1112.4000 833.4700 ;
    END
  END clk_2core__L16_N136
  PIN clk_2core__L16_N137
    DIRECTION INPUT ;
    USE SIGNAL ;
    PORT
      LAYER Metal3 ;
        RECT 1112.1100 869.6900 1112.4000 869.7600 ;
    END
  END clk_2core__L16_N137
  PIN clk_2core__L16_N138
    DIRECTION INPUT ;
    USE SIGNAL ;
    PORT
      LAYER Metal3 ;
        RECT 1112.1100 877.8600 1112.4000 877.9300 ;
    END
  END clk_2core__L16_N138
  PIN clk_2core__L16_N139
    DIRECTION INPUT ;
    USE SIGNAL ;
    PORT
      LAYER Metal3 ;
        RECT 1112.1100 821.8100 1112.4000 821.8800 ;
    END
  END clk_2core__L16_N139
  PIN clk_2core__L16_N14
    DIRECTION INPUT ;
    USE SIGNAL ;
    PORT
      LAYER Metal3 ;
        RECT 1112.1100 2333.4500 1112.4000 2333.5200 ;
    END
  END clk_2core__L16_N14
  PIN clk_2core__L16_N140
    DIRECTION INPUT ;
    USE SIGNAL ;
    PORT
      LAYER Metal3 ;
        RECT 1112.1100 881.2800 1112.4000 881.3500 ;
    END
  END clk_2core__L16_N140
  PIN clk_2core__L16_N15
    DIRECTION INPUT ;
    USE SIGNAL ;
    PORT
      LAYER Metal3 ;
        RECT 1112.1100 2340.2900 1112.4000 2340.3600 ;
    END
  END clk_2core__L16_N15
  PIN clk_2core__L16_N16
    DIRECTION INPUT ;
    USE SIGNAL ;
    PORT
      LAYER Metal3 ;
        RECT 1112.1100 1777.3200 1112.4000 1777.3900 ;
    END
  END clk_2core__L16_N16
  PIN clk_2core__L16_N17
    DIRECTION INPUT ;
    USE SIGNAL ;
    PORT
      LAYER Metal3 ;
        RECT 1112.1100 1772.5700 1112.4000 1772.6400 ;
    END
  END clk_2core__L16_N17
  PIN clk_2core__L16_N18
    DIRECTION INPUT ;
    USE SIGNAL ;
    PORT
      LAYER Metal3 ;
        RECT 1112.1100 1784.1600 1112.4000 1784.2300 ;
    END
  END clk_2core__L16_N18
  PIN clk_2core__L16_N19
    DIRECTION INPUT ;
    USE SIGNAL ;
    PORT
      LAYER Metal3 ;
        RECT 1112.1100 1794.4200 1112.4000 1794.4900 ;
    END
  END clk_2core__L16_N19
  PIN clk_2core__L16_N20
    DIRECTION INPUT ;
    USE SIGNAL ;
    PORT
      LAYER Metal3 ;
        RECT 1112.1100 1801.2600 1112.4000 1801.3300 ;
    END
  END clk_2core__L16_N20
  PIN clk_2core__L16_N21
    DIRECTION INPUT ;
    USE SIGNAL ;
    PORT
      LAYER Metal3 ;
        RECT 1112.1100 1797.8400 1112.4000 1797.9100 ;
    END
  END clk_2core__L16_N21
  PIN clk_2core__L16_N22
    DIRECTION INPUT ;
    USE SIGNAL ;
    PORT
      LAYER Metal3 ;
        RECT 1112.1100 1789.6700 1112.4000 1789.7400 ;
    END
  END clk_2core__L16_N22
  PIN clk_2core__L16_N23
    DIRECTION INPUT ;
    USE SIGNAL ;
    PORT
      LAYER Metal3 ;
        RECT 1112.1100 1817.0300 1112.4000 1817.1000 ;
    END
  END clk_2core__L16_N23
  PIN clk_2core__L16_N24
    DIRECTION INPUT ;
    USE SIGNAL ;
    PORT
      LAYER Metal3 ;
        RECT 1112.1100 1821.7800 1112.4000 1821.8500 ;
    END
  END clk_2core__L16_N24
  PIN clk_2core__L16_N25
    DIRECTION INPUT ;
    USE SIGNAL ;
    PORT
      LAYER Metal3 ;
        RECT 1112.1100 2011.9700 1112.4000 2012.0400 ;
    END
  END clk_2core__L16_N25
  PIN clk_2core__L16_N26
    DIRECTION INPUT ;
    USE SIGNAL ;
    PORT
      LAYER Metal3 ;
        RECT 1112.1100 2015.3900 1112.4000 2015.4600 ;
    END
  END clk_2core__L16_N26
  PIN clk_2core__L16_N27
    DIRECTION INPUT ;
    USE SIGNAL ;
    PORT
      LAYER Metal3 ;
        RECT 1112.1100 1888.8500 1112.4000 1888.9200 ;
    END
  END clk_2core__L16_N27
  PIN clk_2core__L16_N28
    DIRECTION INPUT ;
    USE SIGNAL ;
    PORT
      LAYER Metal3 ;
        RECT 1112.1100 1984.6100 1112.4000 1984.6800 ;
    END
  END clk_2core__L16_N28
  PIN clk_2core__L16_N29
    DIRECTION INPUT ;
    USE SIGNAL ;
    PORT
      LAYER Metal3 ;
        RECT 1112.1100 1711.0100 1112.4000 1711.0800 ;
    END
  END clk_2core__L16_N29
  PIN clk_2core__L16_N30
    DIRECTION INPUT ;
    USE SIGNAL ;
    PORT
      LAYER Metal3 ;
        RECT 1112.1100 1721.2700 1112.4000 1721.3400 ;
    END
  END clk_2core__L16_N30
  PIN clk_2core__L16_N31
    DIRECTION INPUT ;
    USE SIGNAL ;
    PORT
      LAYER Metal3 ;
        RECT 1112.1100 1697.3300 1112.4000 1697.4000 ;
    END
  END clk_2core__L16_N31
  PIN clk_2core__L16_N32
    DIRECTION INPUT ;
    USE SIGNAL ;
    PORT
      LAYER Metal3 ;
        RECT 1112.1100 1654.2000 1112.4000 1654.2700 ;
    END
  END clk_2core__L16_N32
  PIN clk_2core__L16_N33
    DIRECTION INPUT ;
    USE SIGNAL ;
    PORT
      LAYER Metal3 ;
        RECT 1112.1100 1722.6000 1112.4000 1722.6700 ;
    END
  END clk_2core__L16_N33
  PIN clk_2core__L16_N34
    DIRECTION INPUT ;
    USE SIGNAL ;
    PORT
      LAYER Metal3 ;
        RECT 1112.1100 1690.4900 1112.4000 1690.5600 ;
    END
  END clk_2core__L16_N34
  PIN clk_2core__L16_N35
    DIRECTION INPUT ;
    USE SIGNAL ;
    PORT
      LAYER Metal3 ;
        RECT 1112.1100 1659.7100 1112.4000 1659.7800 ;
    END
  END clk_2core__L16_N35
  PIN clk_2core__L16_N36
    DIRECTION INPUT ;
    USE SIGNAL ;
    PORT
      LAYER Metal3 ;
        RECT 1112.1100 1702.0800 1112.4000 1702.1500 ;
    END
  END clk_2core__L16_N36
  PIN clk_2core__L16_N37
    DIRECTION INPUT ;
    USE SIGNAL ;
    PORT
      LAYER Metal3 ;
        RECT 1112.1100 1683.6500 1112.4000 1683.7200 ;
    END
  END clk_2core__L16_N37
  PIN clk_2core__L16_N38
    DIRECTION INPUT ;
    USE SIGNAL ;
    PORT
      LAYER Metal3 ;
        RECT 1112.1100 1678.1400 1112.4000 1678.2100 ;
    END
  END clk_2core__L16_N38
  PIN clk_2core__L16_N39
    DIRECTION INPUT ;
    USE SIGNAL ;
    PORT
      LAYER Metal3 ;
        RECT 1112.1100 1732.8600 1112.4000 1732.9300 ;
    END
  END clk_2core__L16_N39
  PIN clk_2core__L16_N40
    DIRECTION INPUT ;
    USE SIGNAL ;
    PORT
      LAYER Metal3 ;
        RECT 1112.1100 1765.7300 1112.4000 1765.8000 ;
    END
  END clk_2core__L16_N40
  PIN clk_2core__L16_N41
    DIRECTION INPUT ;
    USE SIGNAL ;
    PORT
      LAYER Metal3 ;
        RECT 1112.1100 1738.3700 1112.4000 1738.4400 ;
    END
  END clk_2core__L16_N41
  PIN clk_2core__L16_N42
    DIRECTION INPUT ;
    USE SIGNAL ;
    PORT
      LAYER Metal3 ;
        RECT 1112.1100 1758.8900 1112.4000 1758.9600 ;
    END
  END clk_2core__L16_N42
  PIN clk_2core__L16_N43
    DIRECTION INPUT ;
    USE SIGNAL ;
    PORT
      LAYER Metal3 ;
        RECT 1112.1100 1773.9000 1112.4000 1773.9700 ;
    END
  END clk_2core__L16_N43
  PIN clk_2core__L16_N44
    DIRECTION INPUT ;
    USE SIGNAL ;
    PORT
      LAYER Metal3 ;
        RECT 1112.1100 1729.4400 1112.4000 1729.5100 ;
    END
  END clk_2core__L16_N44
  PIN clk_2core__L16_N45
    DIRECTION INPUT ;
    USE SIGNAL ;
    PORT
      LAYER Metal3 ;
        RECT 1112.1100 1669.9700 1112.4000 1670.0400 ;
    END
  END clk_2core__L16_N45
  PIN clk_2core__L16_N46
    DIRECTION INPUT ;
    USE SIGNAL ;
    PORT
      LAYER Metal3 ;
        RECT 1112.1100 1259.5700 1112.4000 1259.6400 ;
    END
  END clk_2core__L16_N46
  PIN clk_2core__L16_N47
    DIRECTION INPUT ;
    USE SIGNAL ;
    PORT
      LAYER Metal3 ;
        RECT 1112.1100 1305.3600 1112.4000 1305.4300 ;
    END
  END clk_2core__L16_N47
  PIN clk_2core__L16_N48
    DIRECTION INPUT ;
    USE SIGNAL ;
    PORT
      LAYER Metal3 ;
        RECT 1112.1100 1281.4200 1112.4000 1281.4900 ;
    END
  END clk_2core__L16_N48
  PIN clk_2core__L16_N49
    DIRECTION INPUT ;
    USE SIGNAL ;
    PORT
      LAYER Metal3 ;
        RECT 1112.1100 1273.2500 1112.4000 1273.3200 ;
    END
  END clk_2core__L16_N49
  PIN clk_2core__L16_N50
    DIRECTION INPUT ;
    USE SIGNAL ;
    PORT
      LAYER Metal3 ;
        RECT 1112.1100 1315.6200 1112.4000 1315.6900 ;
    END
  END clk_2core__L16_N50
  PIN clk_2core__L16_N51
    DIRECTION INPUT ;
    USE SIGNAL ;
    PORT
      LAYER Metal3 ;
        RECT 1112.1100 1298.5200 1112.4000 1298.5900 ;
    END
  END clk_2core__L16_N51
  PIN clk_2core__L16_N52
    DIRECTION INPUT ;
    USE SIGNAL ;
    PORT
      LAYER Metal3 ;
        RECT 1112.1100 1264.3200 1112.4000 1264.3900 ;
    END
  END clk_2core__L16_N52
  PIN clk_2core__L16_N53
    DIRECTION INPUT ;
    USE SIGNAL ;
    PORT
      LAYER Metal3 ;
        RECT 1112.1100 1266.4100 1112.4000 1266.4800 ;
    END
  END clk_2core__L16_N53
  PIN clk_2core__L16_N54
    DIRECTION INPUT ;
    USE SIGNAL ;
    PORT
      LAYER Metal3 ;
        RECT 1112.1100 1242.4700 1112.4000 1242.5400 ;
    END
  END clk_2core__L16_N54
  PIN clk_2core__L16_N55
    DIRECTION INPUT ;
    USE SIGNAL ;
    PORT
      LAYER Metal3 ;
        RECT 1112.1100 1119.3500 1112.4000 1119.4200 ;
    END
  END clk_2core__L16_N55
  PIN clk_2core__L16_N56
    DIRECTION INPUT ;
    USE SIGNAL ;
    PORT
      LAYER Metal3 ;
        RECT 1112.1100 1156.9700 1112.4000 1157.0400 ;
    END
  END clk_2core__L16_N56
  PIN clk_2core__L16_N57
    DIRECTION INPUT ;
    USE SIGNAL ;
    PORT
      LAYER Metal3 ;
        RECT 1112.1100 1189.0800 1112.4000 1189.1500 ;
    END
  END clk_2core__L16_N57
  PIN clk_2core__L16_N58
    DIRECTION INPUT ;
    USE SIGNAL ;
    PORT
      LAYER Metal3 ;
        RECT 1112.1100 1115.9300 1112.4000 1116.0000 ;
    END
  END clk_2core__L16_N58
  PIN clk_2core__L16_N59
    DIRECTION INPUT ;
    USE SIGNAL ;
    PORT
      LAYER Metal3 ;
        RECT 1112.1100 1151.4600 1112.4000 1151.5300 ;
    END
  END clk_2core__L16_N59
  PIN clk_2core__L16_N60
    DIRECTION INPUT ;
    USE SIGNAL ;
    PORT
      LAYER Metal3 ;
        RECT 1112.1100 1175.4000 1112.4000 1175.4700 ;
    END
  END clk_2core__L16_N60
  PIN clk_2core__L16_N61
    DIRECTION INPUT ;
    USE SIGNAL ;
    PORT
      LAYER Metal3 ;
        RECT 1112.1100 1124.1000 1112.4000 1124.1700 ;
    END
  END clk_2core__L16_N61
  PIN clk_2core__L16_N62
    DIRECTION INPUT ;
    USE SIGNAL ;
    PORT
      LAYER Metal3 ;
        RECT 1112.1100 1194.5900 1112.4000 1194.6600 ;
    END
  END clk_2core__L16_N62
  PIN clk_2core__L16_N63
    DIRECTION INPUT ;
    USE SIGNAL ;
    PORT
      LAYER Metal3 ;
        RECT 1112.1100 1150.1300 1112.4000 1150.2000 ;
    END
  END clk_2core__L16_N63
  PIN clk_2core__L16_N64
    DIRECTION INPUT ;
    USE SIGNAL ;
    PORT
      LAYER Metal3 ;
        RECT 1112.1100 1134.3600 1112.4000 1134.4300 ;
    END
  END clk_2core__L16_N64
  PIN clk_2core__L16_N65
    DIRECTION INPUT ;
    USE SIGNAL ;
    PORT
      LAYER Metal3 ;
        RECT 1112.1100 1102.2500 1112.4000 1102.3200 ;
    END
  END clk_2core__L16_N65
  PIN clk_2core__L16_N66
    DIRECTION INPUT ;
    USE SIGNAL ;
    PORT
      LAYER Metal3 ;
        RECT 1112.1100 1129.6100 1112.4000 1129.6800 ;
    END
  END clk_2core__L16_N66
  PIN clk_2core__L16_N67
    DIRECTION INPUT ;
    USE SIGNAL ;
    PORT
      LAYER Metal3 ;
        RECT 1112.1100 1110.4200 1112.4000 1110.4900 ;
    END
  END clk_2core__L16_N67
  PIN clk_2core__L16_N68
    DIRECTION INPUT ;
    USE SIGNAL ;
    PORT
      LAYER Metal3 ;
        RECT 1112.1100 1139.8700 1112.4000 1139.9400 ;
    END
  END clk_2core__L16_N68
  PIN clk_2core__L16_N69
    DIRECTION INPUT ;
    USE SIGNAL ;
    PORT
      LAYER Metal3 ;
        RECT 1112.1100 1165.1400 1112.4000 1165.2100 ;
    END
  END clk_2core__L16_N69
  PIN clk_2core__L16_N70
    DIRECTION INPUT ;
    USE SIGNAL ;
    PORT
      LAYER Metal3 ;
        RECT 1112.1100 1178.8200 1112.4000 1178.8900 ;
    END
  END clk_2core__L16_N70
  PIN clk_2core__L16_N71
    DIRECTION INPUT ;
    USE SIGNAL ;
    PORT
      LAYER Metal3 ;
        RECT 1112.1100 1170.6500 1112.4000 1170.7200 ;
    END
  END clk_2core__L16_N71
  PIN clk_2core__L16_N72
    DIRECTION INPUT ;
    USE SIGNAL ;
    PORT
      LAYER Metal3 ;
        RECT 1112.1100 1509.2300 1112.4000 1509.3000 ;
    END
  END clk_2core__L16_N72
  PIN clk_2core__L16_N73
    DIRECTION INPUT ;
    USE SIGNAL ;
    PORT
      LAYER Metal3 ;
        RECT 1112.1100 1599.4800 1112.4000 1599.5500 ;
    END
  END clk_2core__L16_N73
  PIN clk_2core__L16_N74
    DIRECTION INPUT ;
    USE SIGNAL ;
    PORT
      LAYER Metal3 ;
        RECT 1112.1100 1594.7300 1112.4000 1594.8000 ;
    END
  END clk_2core__L16_N74
  PIN clk_2core__L16_N75
    DIRECTION INPUT ;
    USE SIGNAL ;
    PORT
      LAYER Metal3 ;
        RECT 1112.1100 1536.5900 1112.4000 1536.6600 ;
    END
  END clk_2core__L16_N75
  PIN clk_2core__L16_N76
    DIRECTION INPUT ;
    USE SIGNAL ;
    PORT
      LAYER Metal3 ;
        RECT 1112.1100 1565.2800 1112.4000 1565.3500 ;
    END
  END clk_2core__L16_N76
  PIN clk_2core__L16_N77
    DIRECTION INPUT ;
    USE SIGNAL ;
    PORT
      LAYER Metal3 ;
        RECT 1112.1100 1589.2200 1112.4000 1589.2900 ;
    END
  END clk_2core__L16_N77
  PIN clk_2core__L16_N78
    DIRECTION INPUT ;
    USE SIGNAL ;
    PORT
      LAYER Metal3 ;
        RECT 1112.1100 1572.1200 1112.4000 1572.1900 ;
    END
  END clk_2core__L16_N78
  PIN clk_2core__L16_N79
    DIRECTION INPUT ;
    USE SIGNAL ;
    PORT
      LAYER Metal3 ;
        RECT 1112.1100 1578.9600 1112.4000 1579.0300 ;
    END
  END clk_2core__L16_N79
  PIN clk_2core__L16_N80
    DIRECTION INPUT ;
    USE SIGNAL ;
    PORT
      LAYER Metal3 ;
        RECT 1112.1100 1584.4700 1112.4000 1584.5400 ;
    END
  END clk_2core__L16_N80
  PIN clk_2core__L16_N81
    DIRECTION INPUT ;
    USE SIGNAL ;
    PORT
      LAYER Metal3 ;
        RECT 1112.1100 1452.4200 1112.4000 1452.4900 ;
    END
  END clk_2core__L16_N81
  PIN clk_2core__L16_N82
    DIRECTION INPUT ;
    USE SIGNAL ;
    PORT
      LAYER Metal3 ;
        RECT 1112.1100 1527.6600 1112.4000 1527.7300 ;
    END
  END clk_2core__L16_N82
  PIN clk_2core__L16_N83
    DIRECTION INPUT ;
    USE SIGNAL ;
    PORT
      LAYER Metal3 ;
        RECT 1112.1100 1505.8100 1112.4000 1505.8800 ;
    END
  END clk_2core__L16_N83
  PIN clk_2core__L16_N84
    DIRECTION INPUT ;
    USE SIGNAL ;
    PORT
      LAYER Metal3 ;
        RECT 1112.1100 1513.9800 1112.4000 1514.0500 ;
    END
  END clk_2core__L16_N84
  PIN clk_2core__L16_N85
    DIRECTION INPUT ;
    USE SIGNAL ;
    PORT
      LAYER Metal3 ;
        RECT 1112.1100 1457.9300 1112.4000 1458.0000 ;
    END
  END clk_2core__L16_N85
  PIN clk_2core__L16_N86
    DIRECTION INPUT ;
    USE SIGNAL ;
    PORT
      LAYER Metal3 ;
        RECT 1112.1100 1502.3900 1112.4000 1502.4600 ;
    END
  END clk_2core__L16_N86
  PIN clk_2core__L16_N87
    DIRECTION INPUT ;
    USE SIGNAL ;
    PORT
      LAYER Metal3 ;
        RECT 1112.1100 1483.2000 1112.4000 1483.2700 ;
    END
  END clk_2core__L16_N87
  PIN clk_2core__L16_N88
    DIRECTION INPUT ;
    USE SIGNAL ;
    PORT
      LAYER Metal3 ;
        RECT 1112.1100 1490.0400 1112.4000 1490.1100 ;
    END
  END clk_2core__L16_N88
  PIN clk_2core__L16_N89
    DIRECTION INPUT ;
    USE SIGNAL ;
    PORT
      LAYER Metal3 ;
        RECT 1112.1100 1014.6600 1112.4000 1014.7300 ;
    END
  END clk_2core__L16_N89
  PIN clk_2core__L16_N90
    DIRECTION INPUT ;
    USE SIGNAL ;
    PORT
      LAYER Metal3 ;
        RECT 1112.1100 1004.4000 1112.4000 1004.4700 ;
    END
  END clk_2core__L16_N90
  PIN clk_2core__L16_N91
    DIRECTION INPUT ;
    USE SIGNAL ;
    PORT
      LAYER Metal3 ;
        RECT 1112.1100 1031.7600 1112.4000 1031.8300 ;
    END
  END clk_2core__L16_N91
  PIN clk_2core__L16_N92
    DIRECTION INPUT ;
    USE SIGNAL ;
    PORT
      LAYER Metal3 ;
        RECT 1112.1100 1007.8200 1112.4000 1007.8900 ;
    END
  END clk_2core__L16_N92
  PIN clk_2core__L16_N93
    DIRECTION INPUT ;
    USE SIGNAL ;
    PORT
      LAYER Metal3 ;
        RECT 1112.1100 1020.1700 1112.4000 1020.2400 ;
    END
  END clk_2core__L16_N93
  PIN clk_2core__L16_N94
    DIRECTION INPUT ;
    USE SIGNAL ;
    PORT
      LAYER Metal3 ;
        RECT 1112.1100 956.5200 1112.4000 956.5900 ;
    END
  END clk_2core__L16_N94
  PIN clk_2core__L16_N95
    DIRECTION INPUT ;
    USE SIGNAL ;
    PORT
      LAYER Metal3 ;
        RECT 1112.1100 948.3500 1112.4000 948.4200 ;
    END
  END clk_2core__L16_N95
  PIN clk_2core__L16_N96
    DIRECTION INPUT ;
    USE SIGNAL ;
    PORT
      LAYER Metal3 ;
        RECT 1112.1100 966.7800 1112.4000 966.8500 ;
    END
  END clk_2core__L16_N96
  PIN clk_2core__L16_N97
    DIRECTION INPUT ;
    USE SIGNAL ;
    PORT
      LAYER Metal3 ;
        RECT 1112.1100 1028.3400 1112.4000 1028.4100 ;
    END
  END clk_2core__L16_N97
  PIN clk_2core__L16_N98
    DIRECTION INPUT ;
    USE SIGNAL ;
    PORT
      LAYER Metal3 ;
        RECT 1112.1100 859.4300 1112.4000 859.5000 ;
    END
  END clk_2core__L16_N98
  PIN clk_2core__L16_N99
    DIRECTION INPUT ;
    USE SIGNAL ;
    PORT
      LAYER Metal3 ;
        RECT 1112.1100 959.9400 1112.4000 960.0100 ;
    END
  END clk_2core__L16_N99
  PIN clk_2core__L17_N0
    DIRECTION INPUT ;
    USE SIGNAL ;
    PORT
      LAYER Metal3 ;
        RECT 1112.1100 1223.2800 1112.4000 1223.3500 ;
    END
  END clk_2core__L17_N0
  PIN clk_2core__L17_N1
    DIRECTION INPUT ;
    USE SIGNAL ;
    PORT
      LAYER Metal3 ;
        RECT 1112.1100 1226.7000 1112.4000 1226.7700 ;
    END
  END clk_2core__L17_N1
  PIN clk_2core__L17_N2
    DIRECTION INPUT ;
    USE SIGNAL ;
    PORT
      LAYER Metal3 ;
        RECT 1112.1100 1233.5400 1112.4000 1233.6100 ;
    END
  END clk_2core__L17_N2
  PIN clk_2core__L17_N3
    DIRECTION INPUT ;
    USE SIGNAL ;
    PORT
      LAYER Metal3 ;
        RECT 1112.1100 1216.4400 1112.4000 1216.5100 ;
    END
  END clk_2core__L17_N3
  PIN clk_2core__L17_N4
    DIRECTION INPUT ;
    USE SIGNAL ;
    PORT
      LAYER Metal3 ;
        RECT 1112.1100 1208.2700 1112.4000 1208.3400 ;
    END
  END clk_2core__L17_N4
  PIN clk_2core__L17_N5
    DIRECTION INPUT ;
    USE SIGNAL ;
    PORT
      LAYER Metal3 ;
        RECT 1112.1100 1083.0600 1112.4000 1083.1300 ;
    END
  END clk_2core__L17_N5
  PIN utmi_phy_clk_2core__L6_N1
    DIRECTION INPUT ;
    USE SIGNAL ;
    PORT
      LAYER Metal2 ;
        RECT 468.6650 0.0000 468.7350 0.2900 ;
    END
  END utmi_phy_clk_2core__L6_N1
  PIN utmi_phy_clk_2core__L6_N10
    DIRECTION INPUT ;
    USE SIGNAL ;
    PORT
      LAYER Metal2 ;
        RECT 537.2650 0.0000 537.3350 0.2900 ;
    END
  END utmi_phy_clk_2core__L6_N10
  PIN utmi_phy_clk_2core__L6_N11
    DIRECTION INPUT ;
    USE SIGNAL ;
    PORT
      LAYER Metal2 ;
        RECT 535.0650 0.0000 535.1350 0.2900 ;
    END
  END utmi_phy_clk_2core__L6_N11
  PIN utmi_phy_clk_2core__L6_N12
    DIRECTION INPUT ;
    USE SIGNAL ;
    PORT
      LAYER Metal2 ;
        RECT 539.4650 0.0000 539.5350 0.2900 ;
    END
  END utmi_phy_clk_2core__L6_N12
  PIN utmi_phy_clk_2core__L6_N13
    DIRECTION INPUT ;
    USE SIGNAL ;
    PORT
      LAYER Metal2 ;
        RECT 530.0650 0.0000 530.1350 0.2900 ;
    END
  END utmi_phy_clk_2core__L6_N13
  PIN utmi_phy_clk_2core__L6_N14
    DIRECTION INPUT ;
    USE SIGNAL ;
    PORT
      LAYER Metal2 ;
        RECT 482.4650 0.0000 482.5350 0.2900 ;
    END
  END utmi_phy_clk_2core__L6_N14
  PIN utmi_phy_clk_2core__L6_N15
    DIRECTION INPUT ;
    USE SIGNAL ;
    PORT
      LAYER Metal2 ;
        RECT 608.0650 0.0000 608.1350 0.2900 ;
    END
  END utmi_phy_clk_2core__L6_N15
  PIN utmi_phy_clk_2core__L6_N16
    DIRECTION INPUT ;
    USE SIGNAL ;
    PORT
      LAYER Metal2 ;
        RECT 621.6650 0.0000 621.7350 0.2900 ;
    END
  END utmi_phy_clk_2core__L6_N16
  PIN utmi_phy_clk_2core__L6_N17
    DIRECTION INPUT ;
    USE SIGNAL ;
    PORT
      LAYER Metal2 ;
        RECT 595.8650 0.0000 595.9350 0.2900 ;
    END
  END utmi_phy_clk_2core__L6_N17
  PIN utmi_phy_clk_2core__L6_N18
    DIRECTION INPUT ;
    USE SIGNAL ;
    PORT
      LAYER Metal2 ;
        RECT 586.8650 0.0000 586.9350 0.2900 ;
    END
  END utmi_phy_clk_2core__L6_N18
  PIN utmi_phy_clk_2core__L6_N19
    DIRECTION INPUT ;
    USE SIGNAL ;
    PORT
      LAYER Metal2 ;
        RECT 640.2650 0.0000 640.3350 0.2900 ;
    END
  END utmi_phy_clk_2core__L6_N19
  PIN utmi_phy_clk_2core__L6_N2
    DIRECTION INPUT ;
    USE SIGNAL ;
    PORT
      LAYER Metal8 ;
        RECT 391.8650 0.0000 391.9350 0.2900 ;
    END
  END utmi_phy_clk_2core__L6_N2
  PIN utmi_phy_clk_2core__L6_N20
    DIRECTION INPUT ;
    USE SIGNAL ;
    PORT
      LAYER Metal2 ;
        RECT 655.2650 0.0000 655.3350 0.2900 ;
    END
  END utmi_phy_clk_2core__L6_N20
  PIN utmi_phy_clk_2core__L6_N21
    DIRECTION INPUT ;
    USE SIGNAL ;
    PORT
      LAYER Metal4 ;
        RECT 655.4650 0.0000 655.5350 0.2900 ;
    END
  END utmi_phy_clk_2core__L6_N21
  PIN utmi_phy_clk_2core__L6_N22
    DIRECTION INPUT ;
    USE SIGNAL ;
    PORT
      LAYER Metal2 ;
        RECT 610.2650 0.0000 610.3350 0.2900 ;
    END
  END utmi_phy_clk_2core__L6_N22
  PIN utmi_phy_clk_2core__L6_N23
    DIRECTION INPUT ;
    USE SIGNAL ;
    PORT
      LAYER Metal2 ;
        RECT 697.6650 0.0000 697.7350 0.2900 ;
    END
  END utmi_phy_clk_2core__L6_N23
  PIN utmi_phy_clk_2core__L6_N24
    DIRECTION INPUT ;
    USE SIGNAL ;
    PORT
      LAYER Metal2 ;
        RECT 672.0650 0.0000 672.1350 0.2900 ;
    END
  END utmi_phy_clk_2core__L6_N24
  PIN utmi_phy_clk_2core__L6_N25
    DIRECTION INPUT ;
    USE SIGNAL ;
    PORT
      LAYER Metal2 ;
        RECT 691.4650 0.0000 691.5350 0.2900 ;
    END
  END utmi_phy_clk_2core__L6_N25
  PIN utmi_phy_clk_2core__L6_N26
    DIRECTION INPUT ;
    USE SIGNAL ;
    PORT
      LAYER Metal4 ;
        RECT 697.6650 0.0000 697.7350 0.2900 ;
    END
  END utmi_phy_clk_2core__L6_N26
  PIN utmi_phy_clk_2core__L6_N27
    DIRECTION INPUT ;
    USE SIGNAL ;
    PORT
      LAYER Metal2 ;
        RECT 679.2650 0.0000 679.3350 0.2900 ;
    END
  END utmi_phy_clk_2core__L6_N27
  PIN utmi_phy_clk_2core__L6_N28
    DIRECTION INPUT ;
    USE SIGNAL ;
    PORT
      LAYER Metal2 ;
        RECT 645.6650 0.0000 645.7350 0.2900 ;
    END
  END utmi_phy_clk_2core__L6_N28
  PIN utmi_phy_clk_2core__L6_N29
    DIRECTION INPUT ;
    USE SIGNAL ;
    PORT
      LAYER Metal2 ;
        RECT 591.6650 0.0000 591.7350 0.2900 ;
    END
  END utmi_phy_clk_2core__L6_N29
  PIN utmi_phy_clk_2core__L6_N3
    DIRECTION INPUT ;
    USE SIGNAL ;
    PORT
      LAYER Metal3 ;
        RECT 1112.1100 854.4900 1112.4000 854.5600 ;
    END
  END utmi_phy_clk_2core__L6_N3
  PIN utmi_phy_clk_2core__L6_N30
    DIRECTION INPUT ;
    USE SIGNAL ;
    PORT
      LAYER Metal2 ;
        RECT 233.4650 0.0000 233.5350 0.2900 ;
    END
  END utmi_phy_clk_2core__L6_N30
  PIN utmi_phy_clk_2core__L6_N31
    DIRECTION INPUT ;
    USE SIGNAL ;
    PORT
      LAYER Metal2 ;
        RECT 455.6650 0.0000 455.7350 0.2900 ;
    END
  END utmi_phy_clk_2core__L6_N31
  PIN utmi_phy_clk_2core__L6_N4
    DIRECTION INPUT ;
    USE SIGNAL ;
    PORT
      LAYER Metal3 ;
        RECT 1112.1100 852.0200 1112.4000 852.0900 ;
    END
  END utmi_phy_clk_2core__L6_N4
  PIN utmi_phy_clk_2core__L6_N5
    DIRECTION INPUT ;
    USE SIGNAL ;
    PORT
      LAYER Metal2 ;
        RECT 501.8650 0.0000 501.9350 0.2900 ;
    END
  END utmi_phy_clk_2core__L6_N5
  PIN utmi_phy_clk_2core__L6_N6
    DIRECTION INPUT ;
    USE SIGNAL ;
    PORT
      LAYER Metal2 ;
        RECT 516.0650 0.0000 516.1350 0.2900 ;
    END
  END utmi_phy_clk_2core__L6_N6
  PIN utmi_phy_clk_2core__L6_N7
    DIRECTION INPUT ;
    USE SIGNAL ;
    PORT
      LAYER Metal2 ;
        RECT 506.0650 0.0000 506.1350 0.2900 ;
    END
  END utmi_phy_clk_2core__L6_N7
  PIN utmi_phy_clk_2core__L6_N8
    DIRECTION INPUT ;
    USE SIGNAL ;
    PORT
      LAYER Metal2 ;
        RECT 494.0650 0.0000 494.1350 0.2900 ;
    END
  END utmi_phy_clk_2core__L6_N8
  PIN utmi_phy_clk_2core__L6_N9
    DIRECTION INPUT ;
    USE SIGNAL ;
    PORT
      LAYER Metal4 ;
        RECT 482.2650 0.0000 482.3350 0.2900 ;
    END
  END utmi_phy_clk_2core__L6_N9
  PIN mii1_txclk_2core__L3_N0
    DIRECTION INPUT ;
    USE SIGNAL ;
    PORT
      LAYER Metal3 ;
        RECT 1112.1100 1545.3300 1112.4000 1545.4000 ;
    END
  END mii1_txclk_2core__L3_N0
  PIN mii1_txclk_2core__L3_N1
    DIRECTION INPUT ;
    USE SIGNAL ;
    PORT
      LAYER Metal3 ;
        RECT 1112.1100 1538.4900 1112.4000 1538.5600 ;
    END
  END mii1_txclk_2core__L3_N1
  PIN mii1_txclk_2core__L3_N10
    DIRECTION INPUT ;
    USE SIGNAL ;
    PORT
      LAYER Metal3 ;
        RECT 1112.1100 1915.6400 1112.4000 1915.7100 ;
    END
  END mii1_txclk_2core__L3_N10
  PIN mii1_txclk_2core__L3_N11
    DIRECTION INPUT ;
    USE SIGNAL ;
    PORT
      LAYER Metal3 ;
        RECT 1112.1100 1580.4800 1112.4000 1580.5500 ;
    END
  END mii1_txclk_2core__L3_N11
  PIN mii1_txclk_2core__L3_N12
    DIRECTION INPUT ;
    USE SIGNAL ;
    PORT
      LAYER Metal3 ;
        RECT 1112.1100 1597.5800 1112.4000 1597.6500 ;
    END
  END mii1_txclk_2core__L3_N12
  PIN mii1_txclk_2core__L3_N13
    DIRECTION INPUT ;
    USE SIGNAL ;
    PORT
      LAYER Metal3 ;
        RECT 1112.1100 1753.9500 1112.4000 1754.0200 ;
    END
  END mii1_txclk_2core__L3_N13
  PIN mii1_txclk_2core__L3_N14
    DIRECTION INPUT ;
    USE SIGNAL ;
    PORT
      LAYER Metal3 ;
        RECT 1112.1100 1761.7400 1112.4000 1761.8100 ;
    END
  END mii1_txclk_2core__L3_N14
  PIN mii1_txclk_2core__L3_N15
    DIRECTION INPUT ;
    USE SIGNAL ;
    PORT
      LAYER Metal3 ;
        RECT 1112.1100 1760.2200 1112.4000 1760.2900 ;
    END
  END mii1_txclk_2core__L3_N15
  PIN mii1_txclk_2core__L3_N16
    DIRECTION INPUT ;
    USE SIGNAL ;
    PORT
      LAYER Metal3 ;
        RECT 1112.1100 1382.1200 1112.4000 1382.1900 ;
    END
  END mii1_txclk_2core__L3_N16
  PIN mii1_txclk_2core__L3_N17
    DIRECTION INPUT ;
    USE SIGNAL ;
    PORT
      LAYER Metal3 ;
        RECT 1112.1100 1529.1800 1112.4000 1529.2500 ;
    END
  END mii1_txclk_2core__L3_N17
  PIN mii1_txclk_2core__L3_N18
    DIRECTION INPUT ;
    USE SIGNAL ;
    PORT
      LAYER Metal3 ;
        RECT 1112.1100 1511.1300 1112.4000 1511.2000 ;
    END
  END mii1_txclk_2core__L3_N18
  PIN mii1_txclk_2core__L3_N19
    DIRECTION INPUT ;
    USE SIGNAL ;
    PORT
      LAYER Metal3 ;
        RECT 1112.1100 1522.3400 1112.4000 1522.4100 ;
    END
  END mii1_txclk_2core__L3_N19
  PIN mii1_txclk_2core__L3_N2
    DIRECTION INPUT ;
    USE SIGNAL ;
    PORT
      LAYER Metal3 ;
        RECT 1112.1100 1539.4400 1112.4000 1539.5100 ;
    END
  END mii1_txclk_2core__L3_N2
  PIN mii1_txclk_2core__L3_N20
    DIRECTION INPUT ;
    USE SIGNAL ;
    PORT
      LAYER Metal3 ;
        RECT 1112.1100 1518.9200 1112.4000 1518.9900 ;
    END
  END mii1_txclk_2core__L3_N20
  PIN mii1_txclk_2core__L3_N3
    DIRECTION INPUT ;
    USE SIGNAL ;
    PORT
      LAYER Metal3 ;
        RECT 1112.1100 1531.6500 1112.4000 1531.7200 ;
    END
  END mii1_txclk_2core__L3_N3
  PIN mii1_txclk_2core__L3_N4
    DIRECTION INPUT ;
    USE SIGNAL ;
    PORT
      LAYER Metal3 ;
        RECT 1112.1100 1532.6000 1112.4000 1532.6700 ;
    END
  END mii1_txclk_2core__L3_N4
  PIN mii1_txclk_2core__L3_N5
    DIRECTION INPUT ;
    USE SIGNAL ;
    PORT
      LAYER Metal3 ;
        RECT 1112.1100 1979.6700 1112.4000 1979.7400 ;
    END
  END mii1_txclk_2core__L3_N5
  PIN mii1_txclk_2core__L3_N6
    DIRECTION INPUT ;
    USE SIGNAL ;
    PORT
      LAYER Metal3 ;
        RECT 1112.1100 1973.7800 1112.4000 1973.8500 ;
    END
  END mii1_txclk_2core__L3_N6
  PIN mii1_txclk_2core__L3_N7
    DIRECTION INPUT ;
    USE SIGNAL ;
    PORT
      LAYER Metal3 ;
        RECT 1112.1100 1963.5200 1112.4000 1963.5900 ;
    END
  END mii1_txclk_2core__L3_N7
  PIN mii1_txclk_2core__L3_N8
    DIRECTION INPUT ;
    USE SIGNAL ;
    PORT
      LAYER Metal3 ;
        RECT 1112.1100 1945.4700 1112.4000 1945.5400 ;
    END
  END mii1_txclk_2core__L3_N8
  PIN mii1_txclk_2core__L3_N9
    DIRECTION INPUT ;
    USE SIGNAL ;
    PORT
      LAYER Metal3 ;
        RECT 1112.1100 1932.7400 1112.4000 1932.8100 ;
    END
  END mii1_txclk_2core__L3_N9
  PIN mii1_rxclk_2core__L4_N0
    DIRECTION INPUT ;
    USE SIGNAL ;
    PORT
      LAYER Metal3 ;
        RECT 1112.1100 1949.8400 1112.4000 1949.9100 ;
    END
  END mii1_rxclk_2core__L4_N0
  PIN mii1_rxclk_2core__L4_N1
    DIRECTION INPUT ;
    USE SIGNAL ;
    PORT
      LAYER Metal3 ;
        RECT 1112.1100 2352.4500 1112.4000 2352.5200 ;
    END
  END mii1_rxclk_2core__L4_N1
  PIN mii1_rxclk_2core__L4_N10
    DIRECTION INPUT ;
    USE SIGNAL ;
    PORT
      LAYER Metal3 ;
        RECT 1112.1100 1778.8400 1112.4000 1778.9100 ;
    END
  END mii1_rxclk_2core__L4_N10
  PIN mii1_rxclk_2core__L4_N11
    DIRECTION INPUT ;
    USE SIGNAL ;
    PORT
      LAYER Metal3 ;
        RECT 1112.1100 1843.8200 1112.4000 1843.8900 ;
    END
  END mii1_rxclk_2core__L4_N11
  PIN mii1_rxclk_2core__L4_N2
    DIRECTION INPUT ;
    USE SIGNAL ;
    PORT
      LAYER Metal3 ;
        RECT 1112.1100 2369.5500 1112.4000 2369.6200 ;
    END
  END mii1_rxclk_2core__L4_N2
  PIN mii1_rxclk_2core__L4_N3
    DIRECTION INPUT ;
    USE SIGNAL ;
    PORT
      LAYER Metal3 ;
        RECT 1112.1100 1900.4400 1112.4000 1900.5100 ;
    END
  END mii1_rxclk_2core__L4_N3
  PIN mii1_rxclk_2core__L4_N4
    DIRECTION INPUT ;
    USE SIGNAL ;
    PORT
      LAYER Metal3 ;
        RECT 1112.1100 1894.1700 1112.4000 1894.2400 ;
    END
  END mii1_rxclk_2core__L4_N4
  PIN mii1_rxclk_2core__L4_N5
    DIRECTION INPUT ;
    USE SIGNAL ;
    PORT
      LAYER Metal3 ;
        RECT 1112.1100 1898.5400 1112.4000 1898.6100 ;
    END
  END mii1_rxclk_2core__L4_N5
  PIN mii1_rxclk_2core__L4_N6
    DIRECTION INPUT ;
    USE SIGNAL ;
    PORT
      LAYER Metal3 ;
        RECT 1112.1100 1860.9200 1112.4000 1860.9900 ;
    END
  END mii1_rxclk_2core__L4_N6
  PIN mii1_rxclk_2core__L4_N7
    DIRECTION INPUT ;
    USE SIGNAL ;
    PORT
      LAYER Metal3 ;
        RECT 1112.1100 1856.5500 1112.4000 1856.6200 ;
    END
  END mii1_rxclk_2core__L4_N7
  PIN mii1_rxclk_2core__L4_N8
    DIRECTION INPUT ;
    USE SIGNAL ;
    PORT
      LAYER Metal3 ;
        RECT 1112.1100 1854.0800 1112.4000 1854.1500 ;
    END
  END mii1_rxclk_2core__L4_N8
  PIN mii1_rxclk_2core__L4_N9
    DIRECTION INPUT ;
    USE SIGNAL ;
    PORT
      LAYER Metal3 ;
        RECT 1112.1100 1768.5800 1112.4000 1768.6500 ;
    END
  END mii1_rxclk_2core__L4_N9
  PIN mii2_txclk_2core__L7_N1
    DIRECTION INPUT ;
    USE SIGNAL ;
    PORT
      LAYER Metal3 ;
        RECT 1112.1100 1832.0400 1112.4000 1832.1100 ;
    END
  END mii2_txclk_2core__L7_N1
  PIN mii2_txclk_2core__L7_N2
    DIRECTION INPUT ;
    USE SIGNAL ;
    PORT
      LAYER Metal3 ;
        RECT 1112.1100 1827.2900 1112.4000 1827.3600 ;
    END
  END mii2_txclk_2core__L7_N2
  PIN mii2_txclk_2core__L7_N3
    DIRECTION INPUT ;
    USE SIGNAL ;
    PORT
      LAYER Metal3 ;
        RECT 1112.1100 1425.0600 1112.4000 1425.1300 ;
    END
  END mii2_txclk_2core__L7_N3
  PIN mii2_txclk_2core__L7_N4
    DIRECTION INPUT ;
    USE SIGNAL ;
    PORT
      LAYER Metal3 ;
        RECT 1112.1100 1327.4000 1112.4000 1327.4700 ;
    END
  END mii2_txclk_2core__L7_N4
  PIN mii2_txclk_2core__L7_N5
    DIRECTION INPUT ;
    USE SIGNAL ;
    PORT
      LAYER Metal5 ;
        RECT 1112.1100 544.7900 1112.4000 544.8600 ;
    END
  END mii2_txclk_2core__L7_N5
  PIN mii2_txclk_2core__L7_N6
    DIRECTION INPUT ;
    USE SIGNAL ;
    PORT
      LAYER Metal3 ;
        RECT 1112.1100 556.3800 1112.4000 556.4500 ;
    END
  END mii2_txclk_2core__L7_N6
  PIN mii2_txclk_2core__L7_N7
    DIRECTION INPUT ;
    USE SIGNAL ;
    PORT
      LAYER Metal3 ;
        RECT 1112.1100 932.5800 1112.4000 932.6500 ;
    END
  END mii2_txclk_2core__L7_N7
  PIN mii2_txclk_2core__L7_N8
    DIRECTION INPUT ;
    USE SIGNAL ;
    PORT
      LAYER Metal3 ;
        RECT 1112.1100 611.6700 1112.4000 611.7400 ;
    END
  END mii2_txclk_2core__L7_N8
  PIN mii2_rxclk_2core__L5_N8
    DIRECTION INPUT ;
    USE SIGNAL ;
    PORT
      LAYER Metal3 ;
        RECT 1112.1100 1593.2100 1112.4000 1593.2800 ;
    END
  END mii2_rxclk_2core__L5_N8
  PIN mii2_rxclk_2core__L6_N0
    DIRECTION INPUT ;
    USE SIGNAL ;
    PORT
      LAYER Metal3 ;
        RECT 1112.1100 824.6600 1112.4000 824.7300 ;
    END
  END mii2_rxclk_2core__L6_N0
  PIN mii2_rxclk_2core__L6_N1
    DIRECTION INPUT ;
    USE SIGNAL ;
    PORT
      LAYER Metal3 ;
        RECT 1112.1100 814.4000 1112.4000 814.4700 ;
    END
  END mii2_rxclk_2core__L6_N1
  PIN mii2_rxclk_2core__L6_N10
    DIRECTION INPUT ;
    USE SIGNAL ;
    PORT
      LAYER Metal3 ;
        RECT 1112.1100 2257.6400 1112.4000 2257.7100 ;
    END
  END mii2_rxclk_2core__L6_N10
  PIN mii2_rxclk_2core__L6_N11
    DIRECTION INPUT ;
    USE SIGNAL ;
    PORT
      LAYER Metal3 ;
        RECT 1112.1100 1610.3100 1112.4000 1610.3800 ;
    END
  END mii2_rxclk_2core__L6_N11
  PIN mii2_rxclk_2core__L6_N12
    DIRECTION INPUT ;
    USE SIGNAL ;
    PORT
      LAYER Metal3 ;
        RECT 1112.1100 1601.0000 1112.4000 1601.0700 ;
    END
  END mii2_rxclk_2core__L6_N12
  PIN mii2_rxclk_2core__L6_N13
    DIRECTION INPUT ;
    USE SIGNAL ;
    PORT
      LAYER Metal3 ;
        RECT 1112.1100 1590.7400 1112.4000 1590.8100 ;
    END
  END mii2_rxclk_2core__L6_N13
  PIN mii2_rxclk_2core__L6_N14
    DIRECTION INPUT ;
    USE SIGNAL ;
    PORT
      LAYER Metal3 ;
        RECT 1112.1100 1586.3700 1112.4000 1586.4400 ;
    END
  END mii2_rxclk_2core__L6_N14
  PIN mii2_rxclk_2core__L6_N15
    DIRECTION INPUT ;
    USE SIGNAL ;
    PORT
      LAYER Metal3 ;
        RECT 1112.1100 1888.2800 1112.4000 1888.3500 ;
    END
  END mii2_rxclk_2core__L6_N15
  PIN mii2_rxclk_2core__L6_N16
    DIRECTION INPUT ;
    USE SIGNAL ;
    PORT
      LAYER Metal3 ;
        RECT 1112.1100 1883.9100 1112.4000 1883.9800 ;
    END
  END mii2_rxclk_2core__L6_N16
  PIN mii2_rxclk_2core__L6_N17
    DIRECTION INPUT ;
    USE SIGNAL ;
    PORT
      LAYER Metal3 ;
        RECT 1112.1100 1880.4900 1112.4000 1880.5600 ;
    END
  END mii2_rxclk_2core__L6_N17
  PIN mii2_rxclk_2core__L6_N18
    DIRECTION INPUT ;
    USE SIGNAL ;
    PORT
      LAYER Metal3 ;
        RECT 1112.1100 1874.6000 1112.4000 1874.6700 ;
    END
  END mii2_rxclk_2core__L6_N18
  PIN mii2_rxclk_2core__L6_N19
    DIRECTION INPUT ;
    USE SIGNAL ;
    PORT
      LAYER Metal3 ;
        RECT 1112.1100 1840.4000 1112.4000 1840.4700 ;
    END
  END mii2_rxclk_2core__L6_N19
  PIN mii2_rxclk_2core__L6_N2
    DIRECTION INPUT ;
    USE SIGNAL ;
    PORT
      LAYER Metal3 ;
        RECT 1112.1100 803.1900 1112.4000 803.2600 ;
    END
  END mii2_rxclk_2core__L6_N2
  PIN mii2_rxclk_2core__L6_N20
    DIRECTION INPUT ;
    USE SIGNAL ;
    PORT
      LAYER Metal3 ;
        RECT 1112.1100 1842.8700 1112.4000 1842.9400 ;
    END
  END mii2_rxclk_2core__L6_N20
  PIN mii2_rxclk_2core__L6_N21
    DIRECTION INPUT ;
    USE SIGNAL ;
    PORT
      LAYER Metal3 ;
        RECT 1112.1100 1836.0300 1112.4000 1836.1000 ;
    END
  END mii2_rxclk_2core__L6_N21
  PIN mii2_rxclk_2core__L6_N22
    DIRECTION INPUT ;
    USE SIGNAL ;
    PORT
      LAYER Metal3 ;
        RECT 1112.1100 1829.1900 1112.4000 1829.2600 ;
    END
  END mii2_rxclk_2core__L6_N22
  PIN mii2_rxclk_2core__L6_N23
    DIRECTION INPUT ;
    USE SIGNAL ;
    PORT
      LAYER Metal3 ;
        RECT 1112.1100 2232.7500 1112.4000 2232.8200 ;
    END
  END mii2_rxclk_2core__L6_N23
  PIN mii2_rxclk_2core__L6_N24
    DIRECTION INPUT ;
    USE SIGNAL ;
    PORT
      LAYER Metal3 ;
        RECT 1112.1100 2229.3300 1112.4000 2229.4000 ;
    END
  END mii2_rxclk_2core__L6_N24
  PIN mii2_rxclk_2core__L6_N3
    DIRECTION INPUT ;
    USE SIGNAL ;
    PORT
      LAYER Metal3 ;
        RECT 1112.1100 787.0400 1112.4000 787.1100 ;
    END
  END mii2_rxclk_2core__L6_N3
  PIN mii2_rxclk_2core__L6_N4
    DIRECTION INPUT ;
    USE SIGNAL ;
    PORT
      LAYER Metal3 ;
        RECT 1112.1100 871.5900 1112.4000 871.6600 ;
    END
  END mii2_rxclk_2core__L6_N4
  PIN mii2_rxclk_2core__L6_N5
    DIRECTION INPUT ;
    USE SIGNAL ;
    PORT
      LAYER Metal3 ;
        RECT 1112.1100 867.6000 1112.4000 867.6700 ;
    END
  END mii2_rxclk_2core__L6_N5
  PIN mii2_rxclk_2core__L6_N6
    DIRECTION INPUT ;
    USE SIGNAL ;
    PORT
      LAYER Metal3 ;
        RECT 1112.1100 862.8500 1112.4000 862.9200 ;
    END
  END mii2_rxclk_2core__L6_N6
  PIN mii2_rxclk_2core__L6_N7
    DIRECTION INPUT ;
    USE SIGNAL ;
    PORT
      LAYER Metal3 ;
        RECT 1112.1100 858.8600 1112.4000 858.9300 ;
    END
  END mii2_rxclk_2core__L6_N7
  PIN mii2_rxclk_2core__L6_N8
    DIRECTION INPUT ;
    USE SIGNAL ;
    PORT
      LAYER Metal3 ;
        RECT 1112.1100 861.3300 1112.4000 861.4000 ;
    END
  END mii2_rxclk_2core__L6_N8
  PIN mii2_rxclk_2core__L6_N9
    DIRECTION INPUT ;
    USE SIGNAL ;
    PORT
      LAYER Metal3 ;
        RECT 1112.1100 2249.8500 1112.4000 2249.9200 ;
    END
  END mii2_rxclk_2core__L6_N9
  PIN vid_pclk_2core__N0
    DIRECTION INPUT ;
    USE SIGNAL ;
    PORT
      LAYER Metal3 ;
        RECT 1112.1100 1727.5400 1112.4000 1727.6100 ;
    END
  END vid_pclk_2core__N0
  PIN mii2_rxclk_2core__N11
    DIRECTION INPUT ;
    USE SIGNAL ;
    PORT
      LAYER Metal3 ;
        RECT 1112.1100 865.7000 1112.4000 865.7700 ;
    END
  END mii2_rxclk_2core__N11
  PIN FE_OFN13175_bist_start_2innercore
    DIRECTION INPUT ;
    USE SIGNAL ;
    PORT
      LAYER Metal2 ;
        RECT 808.6650 0.0000 808.7350 0.2900 ;
    END
  END FE_OFN13175_bist_start_2innercore
  PIN FE_OFN14126_vgaslavein_83
    DIRECTION INPUT ;
    USE SIGNAL ;
    PORT
      LAYER Metal3 ;
        RECT 1112.1100 182.8400 1112.4000 182.9100 ;
    END
  END FE_OFN14126_vgaslavein_83
  PIN FE_PT1_vgaslavein_83
    DIRECTION INPUT ;
    USE SIGNAL ;
    PORT
      LAYER Metal3 ;
        RECT 1112.1100 1.0100 1112.4000 1.0800 ;
    END
  END FE_PT1_vgaslavein_83
  PIN VSS
    DIRECTION INOUT ;
    USE GROUND ;
    PORT
      LAYER Metal9 ;
        RECT 1112.3300 3053.6700 1112.4000 3063.6700 ;
    END
    PORT
      LAYER Metal9 ;
        RECT 1112.3300 2933.6700 1112.4000 2943.6700 ;
    END
    PORT
      LAYER Metal9 ;
        RECT 1112.3300 2813.6700 1112.4000 2823.6700 ;
    END
    PORT
      LAYER Metal9 ;
        RECT 1112.3300 2693.6700 1112.4000 2703.6700 ;
    END
    PORT
      LAYER Metal9 ;
        RECT 1112.3300 2573.6700 1112.4000 2583.6700 ;
    END
    PORT
      LAYER Metal9 ;
        RECT 1112.3300 2453.6700 1112.4000 2463.6700 ;
    END
    PORT
      LAYER Metal9 ;
        RECT 1112.3300 2333.6700 1112.4000 2343.6700 ;
    END
    PORT
      LAYER Metal9 ;
        RECT 1112.3300 2213.6700 1112.4000 2223.6700 ;
    END
    PORT
      LAYER Metal9 ;
        RECT 0.0000 2213.6700 0.0700 2223.6700 ;
    END
    PORT
      LAYER Metal9 ;
        RECT 1112.3300 2093.6700 1112.4000 2103.6700 ;
    END
    PORT
      LAYER Metal9 ;
        RECT 1112.3300 1973.6700 1112.4000 1983.6700 ;
    END
    PORT
      LAYER Metal9 ;
        RECT 1112.3300 1853.6700 1112.4000 1863.6700 ;
    END
    PORT
      LAYER Metal9 ;
        RECT 1112.3300 1733.6700 1112.4000 1743.6700 ;
    END
    PORT
      LAYER Metal9 ;
        RECT 1112.3300 1613.6700 1112.4000 1623.6700 ;
    END
    PORT
      LAYER Metal9 ;
        RECT 1112.3300 1493.6700 1112.4000 1503.6700 ;
    END
    PORT
      LAYER Metal9 ;
        RECT 1112.3300 1373.6700 1112.4000 1383.6700 ;
    END
    PORT
      LAYER Metal9 ;
        RECT 1112.3300 1253.6700 1112.4000 1263.6700 ;
    END
    PORT
      LAYER Metal9 ;
        RECT 1112.3300 1133.6700 1112.4000 1143.6700 ;
    END
    PORT
      LAYER Metal9 ;
        RECT 1112.3300 1013.6700 1112.4000 1023.6700 ;
    END
    PORT
      LAYER Metal8 ;
        RECT 1080.0000 3171.9800 1090.0000 3172.0500 ;
    END
    PORT
      LAYER Metal8 ;
        RECT 960.0000 3171.9800 970.0000 3172.0500 ;
    END
    PORT
      LAYER Metal8 ;
        RECT 840.0000 3171.9800 850.0000 3172.0500 ;
    END
    PORT
      LAYER Metal8 ;
        RECT 720.0000 3171.9800 730.0000 3172.0500 ;
    END
    PORT
      LAYER Metal8 ;
        RECT 600.0000 3171.9800 610.0000 3172.0500 ;
    END
    PORT
      LAYER Metal8 ;
        RECT 480.0000 3171.9800 490.0000 3172.0500 ;
    END
    PORT
      LAYER Metal8 ;
        RECT 360.0000 3171.9800 370.0000 3172.0500 ;
    END
    PORT
      LAYER Metal8 ;
        RECT 240.0000 3171.9800 250.0000 3172.0500 ;
    END
    PORT
      LAYER Metal8 ;
        RECT 120.0000 3171.9800 130.0000 3172.0500 ;
    END
    PORT
      LAYER Metal9 ;
        RECT 0.0000 3053.6700 0.0700 3063.6700 ;
    END
    PORT
      LAYER Metal9 ;
        RECT 0.0000 2933.6700 0.0700 2943.6700 ;
    END
    PORT
      LAYER Metal9 ;
        RECT 0.0000 2813.6700 0.0700 2823.6700 ;
    END
    PORT
      LAYER Metal9 ;
        RECT 0.0000 2693.6700 0.0700 2703.6700 ;
    END
    PORT
      LAYER Metal9 ;
        RECT 0.0000 2573.6700 0.0700 2583.6700 ;
    END
    PORT
      LAYER Metal9 ;
        RECT 0.0000 2453.6700 0.0700 2463.6700 ;
    END
    PORT
      LAYER Metal9 ;
        RECT 0.0000 2333.6700 0.0700 2343.6700 ;
    END
    PORT
      LAYER Metal9 ;
        RECT 0.0000 2093.6700 0.0700 2103.6700 ;
    END
    PORT
      LAYER Metal9 ;
        RECT 0.0000 1973.6700 0.0700 1983.6700 ;
    END
    PORT
      LAYER Metal9 ;
        RECT 0.0000 1853.6700 0.0700 1863.6700 ;
    END
    PORT
      LAYER Metal9 ;
        RECT 0.0000 1733.6700 0.0700 1743.6700 ;
    END
    PORT
      LAYER Metal9 ;
        RECT 0.0000 1613.6700 0.0700 1623.6700 ;
    END
    PORT
      LAYER Metal9 ;
        RECT 0.0000 1493.6700 0.0700 1503.6700 ;
    END
    PORT
      LAYER Metal9 ;
        RECT 0.0000 1373.6700 0.0700 1383.6700 ;
    END
    PORT
      LAYER Metal9 ;
        RECT 0.0000 1253.6700 0.0700 1263.6700 ;
    END
    PORT
      LAYER Metal9 ;
        RECT 0.0000 1133.6700 0.0700 1143.6700 ;
    END
    PORT
      LAYER Metal9 ;
        RECT 0.0000 1013.6700 0.0700 1023.6700 ;
    END
    PORT
      LAYER Metal8 ;
        RECT 1080.0000 0.0000 1090.0000 0.0700 ;
    END
    PORT
      LAYER Metal8 ;
        RECT 960.0000 0.0000 970.0000 0.0700 ;
    END
    PORT
      LAYER Metal8 ;
        RECT 840.0000 0.0000 850.0000 0.0700 ;
    END
    PORT
      LAYER Metal9 ;
        RECT 1112.3300 893.6700 1112.4000 903.6700 ;
    END
    PORT
      LAYER Metal9 ;
        RECT 1112.3300 773.6700 1112.4000 783.6700 ;
    END
    PORT
      LAYER Metal9 ;
        RECT 1112.3300 653.6700 1112.4000 663.6700 ;
    END
    PORT
      LAYER Metal9 ;
        RECT 1112.3300 533.6700 1112.4000 543.6700 ;
    END
    PORT
      LAYER Metal9 ;
        RECT 0.0000 533.6700 0.0700 543.6700 ;
    END
    PORT
      LAYER Metal9 ;
        RECT 1112.3300 413.6700 1112.4000 423.6700 ;
    END
    PORT
      LAYER Metal9 ;
        RECT 1112.3300 293.6700 1112.4000 303.6700 ;
    END
    PORT
      LAYER Metal9 ;
        RECT 1112.3300 173.6700 1112.4000 183.6700 ;
    END
    PORT
      LAYER Metal9 ;
        RECT 0.0000 173.6700 0.0700 183.6700 ;
    END
    PORT
      LAYER Metal9 ;
        RECT 1112.3300 53.6700 1112.4000 63.6700 ;
    END
    PORT
      LAYER Metal8 ;
        RECT 720.0000 0.0000 730.0000 0.0700 ;
    END
    PORT
      LAYER Metal8 ;
        RECT 600.0000 0.0000 610.0000 0.0700 ;
    END
    PORT
      LAYER Metal8 ;
        RECT 480.0000 0.0000 490.0000 0.0700 ;
    END
    PORT
      LAYER Metal9 ;
        RECT 0.0000 893.6700 0.0700 903.6700 ;
    END
    PORT
      LAYER Metal9 ;
        RECT 0.0000 773.6700 0.0700 783.6700 ;
    END
    PORT
      LAYER Metal9 ;
        RECT 0.0000 653.6700 0.0700 663.6700 ;
    END
    PORT
      LAYER Metal9 ;
        RECT 0.0000 413.6700 0.0700 423.6700 ;
    END
    PORT
      LAYER Metal9 ;
        RECT 0.0000 293.6700 0.0700 303.6700 ;
    END
    PORT
      LAYER Metal8 ;
        RECT 360.0000 0.0000 370.0000 0.0700 ;
    END
    PORT
      LAYER Metal8 ;
        RECT 240.0000 0.0000 250.0000 0.0700 ;
    END
    PORT
      LAYER Metal8 ;
        RECT 120.0000 0.0000 130.0000 0.0700 ;
    END
    PORT
      LAYER Metal9 ;
        RECT 0.0000 53.6700 0.0700 63.6700 ;
    END
  END VSS
  PIN VDD
    DIRECTION INOUT ;
    USE POWER ;
    PORT
      LAYER Metal9 ;
        RECT 1112.3300 3033.6700 1112.4000 3043.6700 ;
    END
    PORT
      LAYER Metal9 ;
        RECT 1112.3300 2913.6700 1112.4000 2923.6700 ;
    END
    PORT
      LAYER Metal9 ;
        RECT 1112.3300 2793.6700 1112.4000 2803.6700 ;
    END
    PORT
      LAYER Metal9 ;
        RECT 1112.3300 2673.6700 1112.4000 2683.6700 ;
    END
    PORT
      LAYER Metal9 ;
        RECT 1112.3300 2553.6700 1112.4000 2563.6700 ;
    END
    PORT
      LAYER Metal9 ;
        RECT 1112.3300 2433.6700 1112.4000 2443.6700 ;
    END
    PORT
      LAYER Metal9 ;
        RECT 1112.3300 2313.6700 1112.4000 2323.6700 ;
    END
    PORT
      LAYER Metal9 ;
        RECT 1112.3300 2193.6700 1112.4000 2203.6700 ;
    END
    PORT
      LAYER Metal9 ;
        RECT 1112.3300 2073.6700 1112.4000 2083.6700 ;
    END
    PORT
      LAYER Metal9 ;
        RECT 1112.3300 1953.6700 1112.4000 1963.6700 ;
    END
    PORT
      LAYER Metal9 ;
        RECT 1112.3300 1833.6700 1112.4000 1843.6700 ;
    END
    PORT
      LAYER Metal9 ;
        RECT 1112.3300 1713.6700 1112.4000 1723.6700 ;
    END
    PORT
      LAYER Metal9 ;
        RECT 1112.3300 1593.6700 1112.4000 1603.6700 ;
    END
    PORT
      LAYER Metal9 ;
        RECT 1112.3300 1473.6700 1112.4000 1483.6700 ;
    END
    PORT
      LAYER Metal9 ;
        RECT 1112.3300 1353.6700 1112.4000 1363.6700 ;
    END
    PORT
      LAYER Metal9 ;
        RECT 1112.3300 1233.6700 1112.4000 1243.6700 ;
    END
    PORT
      LAYER Metal9 ;
        RECT 1112.3300 1113.6700 1112.4000 1123.6700 ;
    END
    PORT
      LAYER Metal9 ;
        RECT 1112.3300 993.6700 1112.4000 1003.6700 ;
    END
    PORT
      LAYER Metal8 ;
        RECT 1060.0000 3171.9800 1070.0000 3172.0500 ;
    END
    PORT
      LAYER Metal8 ;
        RECT 940.0000 3171.9800 950.0000 3172.0500 ;
    END
    PORT
      LAYER Metal8 ;
        RECT 820.0000 3171.9800 830.0000 3172.0500 ;
    END
    PORT
      LAYER Metal8 ;
        RECT 700.0000 3171.9800 710.0000 3172.0500 ;
    END
    PORT
      LAYER Metal8 ;
        RECT 580.0000 3171.9800 590.0000 3172.0500 ;
    END
    PORT
      LAYER Metal8 ;
        RECT 460.0000 3171.9800 470.0000 3172.0500 ;
    END
    PORT
      LAYER Metal8 ;
        RECT 340.0000 3171.9800 350.0000 3172.0500 ;
    END
    PORT
      LAYER Metal8 ;
        RECT 220.0000 3171.9800 230.0000 3172.0500 ;
    END
    PORT
      LAYER Metal8 ;
        RECT 100.0000 3171.9800 110.0000 3172.0500 ;
    END
    PORT
      LAYER Metal9 ;
        RECT 0.0000 3033.6700 0.0700 3043.6700 ;
    END
    PORT
      LAYER Metal9 ;
        RECT 0.0000 2913.6700 0.0700 2923.6700 ;
    END
    PORT
      LAYER Metal9 ;
        RECT 0.0000 2793.6700 0.0700 2803.6700 ;
    END
    PORT
      LAYER Metal9 ;
        RECT 0.0000 2673.6700 0.0700 2683.6700 ;
    END
    PORT
      LAYER Metal9 ;
        RECT 0.0000 2553.6700 0.0700 2563.6700 ;
    END
    PORT
      LAYER Metal9 ;
        RECT 0.0000 2433.6700 0.0700 2443.6700 ;
    END
    PORT
      LAYER Metal9 ;
        RECT 0.0000 2313.6700 0.0700 2323.6700 ;
    END
    PORT
      LAYER Metal9 ;
        RECT 0.0000 2193.6700 0.0700 2203.6700 ;
    END
    PORT
      LAYER Metal9 ;
        RECT 0.0000 2073.6700 0.0700 2083.6700 ;
    END
    PORT
      LAYER Metal9 ;
        RECT 0.0000 1953.6700 0.0700 1963.6700 ;
    END
    PORT
      LAYER Metal9 ;
        RECT 0.0000 1833.6700 0.0700 1843.6700 ;
    END
    PORT
      LAYER Metal9 ;
        RECT 0.0000 1713.6700 0.0700 1723.6700 ;
    END
    PORT
      LAYER Metal9 ;
        RECT 0.0000 1593.6700 0.0700 1603.6700 ;
    END
    PORT
      LAYER Metal9 ;
        RECT 0.0000 1473.6700 0.0700 1483.6700 ;
    END
    PORT
      LAYER Metal9 ;
        RECT 0.0000 1353.6700 0.0700 1363.6700 ;
    END
    PORT
      LAYER Metal9 ;
        RECT 0.0000 1233.6700 0.0700 1243.6700 ;
    END
    PORT
      LAYER Metal9 ;
        RECT 0.0000 1113.6700 0.0700 1123.6700 ;
    END
    PORT
      LAYER Metal9 ;
        RECT 0.0000 993.6700 0.0700 1003.6700 ;
    END
    PORT
      LAYER Metal8 ;
        RECT 1060.0000 0.0000 1070.0000 0.0700 ;
    END
    PORT
      LAYER Metal8 ;
        RECT 940.0000 0.0000 950.0000 0.0700 ;
    END
    PORT
      LAYER Metal8 ;
        RECT 820.0000 0.0000 830.0000 0.0700 ;
    END
    PORT
      LAYER Metal9 ;
        RECT 1112.3300 873.6700 1112.4000 883.6700 ;
    END
    PORT
      LAYER Metal9 ;
        RECT 1112.3300 753.6700 1112.4000 763.6700 ;
    END
    PORT
      LAYER Metal9 ;
        RECT 1112.3300 633.6700 1112.4000 643.6700 ;
    END
    PORT
      LAYER Metal9 ;
        RECT 1112.3300 513.6700 1112.4000 523.6700 ;
    END
    PORT
      LAYER Metal9 ;
        RECT 1112.3300 393.6700 1112.4000 403.6700 ;
    END
    PORT
      LAYER Metal9 ;
        RECT 1112.3300 273.6700 1112.4000 283.6700 ;
    END
    PORT
      LAYER Metal9 ;
        RECT 1112.3300 153.6700 1112.4000 163.6700 ;
    END
    PORT
      LAYER Metal9 ;
        RECT 1112.3300 33.6700 1112.4000 43.6700 ;
    END
    PORT
      LAYER Metal8 ;
        RECT 700.0000 0.0000 710.0000 0.0700 ;
    END
    PORT
      LAYER Metal8 ;
        RECT 580.0000 0.0000 590.0000 0.0700 ;
    END
    PORT
      LAYER Metal9 ;
        RECT 0.0000 873.6700 0.0700 883.6700 ;
    END
    PORT
      LAYER Metal9 ;
        RECT 0.0000 753.6700 0.0700 763.6700 ;
    END
    PORT
      LAYER Metal9 ;
        RECT 0.0000 633.6700 0.0700 643.6700 ;
    END
    PORT
      LAYER Metal9 ;
        RECT 0.0000 513.6700 0.0700 523.6700 ;
    END
    PORT
      LAYER Metal9 ;
        RECT 0.0000 393.6700 0.0700 403.6700 ;
    END
    PORT
      LAYER Metal9 ;
        RECT 0.0000 273.6700 0.0700 283.6700 ;
    END
    PORT
      LAYER Metal8 ;
        RECT 340.0000 0.0000 350.0000 0.0700 ;
    END
    PORT
      LAYER Metal8 ;
        RECT 220.0000 0.0000 230.0000 0.0700 ;
    END
    PORT
      LAYER Metal8 ;
        RECT 100.0000 0.0000 110.0000 0.0700 ;
    END
    PORT
      LAYER Metal9 ;
        RECT 0.0000 153.6700 0.0700 163.6700 ;
    END
    PORT
      LAYER Metal9 ;
        RECT 0.0000 33.6700 0.0700 43.6700 ;
    END
    PORT
      LAYER Metal8 ;
        RECT 460.0000 0.0000 470.0000 0.0700 ;
    END
  END VDD
  OBS
    LAYER Metal9 ;
      RECT 0.0000 0.0000 1112.4000 605.9700 ;
      RECT 1.2500 605.9700 1112.4000 618.4700 ;
      RECT 0.0000 618.4700 1112.4000 3172.0500 ;
    LAYER Metal8 ;
      RECT 0.0000 0.0000 1112.4000 246.9550 ;
      RECT 1.2500 246.9550 1112.4000 254.4550 ;
      RECT 0.0000 254.4550 1112.4000 293.1550 ;
      RECT 1.2500 293.1550 1112.4000 300.6550 ;
      RECT 0.0000 300.6550 1112.4000 584.2550 ;
      RECT 1.2500 584.2550 1112.4000 591.7550 ;
      RECT 0.0000 591.7550 1112.4000 605.9700 ;
      RECT 1.2500 605.9700 1112.4000 618.4700 ;
      RECT 0.0000 618.4700 1112.4000 630.4550 ;
      RECT 1.2500 630.4550 1112.4000 637.9550 ;
      RECT 0.0000 637.9550 1112.4000 1525.2500 ;
      RECT 1.2500 1525.2500 1112.4000 1532.7500 ;
      RECT 0.0000 1532.7500 1112.4000 3172.0500 ;
    LAYER Metal7 ;
      RECT 0.0000 0.0000 1112.4000 246.9550 ;
      RECT 1.2500 246.9550 1112.4000 254.4550 ;
      RECT 0.0000 254.4550 1112.4000 293.1550 ;
      RECT 1.2500 293.1550 1112.4000 300.6550 ;
      RECT 0.0000 300.6550 1112.4000 584.2550 ;
      RECT 1.2500 584.2550 1112.4000 591.7550 ;
      RECT 0.0000 591.7550 1112.4000 630.4550 ;
      RECT 1.2500 630.4550 1112.4000 637.9550 ;
      RECT 0.0000 637.9550 1112.4000 1525.2500 ;
      RECT 1.2500 1525.2500 1112.4000 1532.7500 ;
      RECT 0.0000 1532.7500 1112.4000 3172.0500 ;
    LAYER Metal6 ;
      RECT 0.0000 0.0000 1112.4000 246.9550 ;
      RECT 1.2500 246.9550 1112.4000 254.4550 ;
      RECT 0.0000 254.4550 1112.4000 293.1550 ;
      RECT 1.2500 293.1550 1112.4000 300.6550 ;
      RECT 0.0000 300.6550 1112.4000 584.2550 ;
      RECT 1.2500 584.2550 1112.4000 591.7550 ;
      RECT 0.0000 591.7550 1112.4000 630.4550 ;
      RECT 1.2500 630.4550 1112.4000 637.9550 ;
      RECT 0.0000 637.9550 1112.4000 1525.2500 ;
      RECT 1.2500 1525.2500 1112.4000 1532.7500 ;
      RECT 0.0000 1532.7500 1112.4000 3172.0500 ;
    LAYER Metal5 ;
      RECT 0.0000 0.0000 1112.4000 246.9550 ;
      RECT 1.2500 246.9550 1112.4000 254.4550 ;
      RECT 0.0000 254.4550 1112.4000 293.1550 ;
      RECT 1.2500 293.1550 1112.4000 300.6550 ;
      RECT 0.0000 300.6550 1112.4000 584.2550 ;
      RECT 1.2500 584.2550 1112.4000 591.7550 ;
      RECT 0.0000 591.7550 1112.4000 630.4550 ;
      RECT 1.2500 630.4550 1112.4000 637.9550 ;
      RECT 0.0000 637.9550 1112.4000 1525.2500 ;
      RECT 1.2500 1525.2500 1112.4000 1532.7500 ;
      RECT 0.0000 1532.7500 1112.4000 3172.0500 ;
    LAYER Metal4 ;
      RECT 0.0000 0.0000 1112.4000 246.9550 ;
      RECT 1.2500 246.9550 1112.4000 254.4550 ;
      RECT 0.0000 254.4550 1112.4000 293.1550 ;
      RECT 1.2500 293.1550 1112.4000 300.6550 ;
      RECT 0.0000 300.6550 1112.4000 584.2550 ;
      RECT 1.2500 584.2550 1112.4000 591.7550 ;
      RECT 0.0000 591.7550 1112.4000 630.4550 ;
      RECT 1.2500 630.4550 1112.4000 637.9550 ;
      RECT 0.0000 637.9550 1112.4000 1525.2500 ;
      RECT 1.2500 1525.2500 1112.4000 1532.7500 ;
      RECT 0.0000 1532.7500 1112.4000 3172.0500 ;
    LAYER Metal3 ;
      RECT 0.0000 0.0000 1112.4000 246.9550 ;
      RECT 1.2500 246.9550 1112.4000 254.4550 ;
      RECT 0.0000 254.4550 1112.4000 293.1550 ;
      RECT 1.2500 293.1550 1112.4000 300.6550 ;
      RECT 0.0000 300.6550 1112.4000 584.2550 ;
      RECT 1.2500 584.2550 1112.4000 591.7550 ;
      RECT 0.0000 591.7550 1112.4000 630.4550 ;
      RECT 1.2500 630.4550 1112.4000 637.9550 ;
      RECT 0.0000 637.9550 1112.4000 1525.2500 ;
      RECT 1.2500 1525.2500 1112.4000 1532.7500 ;
      RECT 0.0000 1532.7500 1112.4000 3172.0500 ;
    LAYER Metal2 ;
      RECT 0.0000 0.0000 1112.4000 246.9550 ;
      RECT 1.2500 246.9550 1112.4000 254.4550 ;
      RECT 0.0000 254.4550 1112.4000 293.1550 ;
      RECT 1.2500 293.1550 1112.4000 293.8050 ;
      RECT 1.2500 293.8050 1112.4000 300.6550 ;
      RECT 0.0000 300.6550 1112.4000 584.2550 ;
      RECT 1.2500 584.2550 1112.4000 591.7550 ;
      RECT 0.0000 591.7550 1112.4000 630.4550 ;
      RECT 1.2500 630.4550 1112.4000 631.1050 ;
      RECT 1.2500 631.1050 1112.4000 637.9550 ;
      RECT 0.0000 637.9550 1112.4000 1525.2500 ;
      RECT 1.2500 1525.2500 1112.4000 1532.7500 ;
      RECT 0.0000 1532.7500 1112.4000 3172.0500 ;
    LAYER Metal1 ;
      RECT 0.0000 0.0000 1112.4000 246.9550 ;
      RECT 1.2500 246.9550 1112.4000 253.8050 ;
      RECT 0.0000 253.8050 1112.4000 293.8050 ;
      RECT 1.2500 293.8050 1112.4000 300.6550 ;
      RECT 0.0000 300.6550 1112.4000 584.2550 ;
      RECT 1.2500 584.2550 1112.4000 591.1050 ;
      RECT 0.0000 591.1050 1112.4000 631.1050 ;
      RECT 1.2500 631.1050 1112.4000 637.9550 ;
      RECT 0.0000 637.9550 1112.4000 1525.2500 ;
      RECT 1.2500 1525.2500 1112.4000 1532.1000 ;
      RECT 0.0000 1532.1000 1112.4000 3172.0500 ;
  END
END periph1

END LIBRARY
